VERSION 5.8 ;
BUSBITCHARS "[]" ;
DIVIDERCHAR "/" ;
UNITS
    DATABASE MICRONS 1000 ;
END UNITS

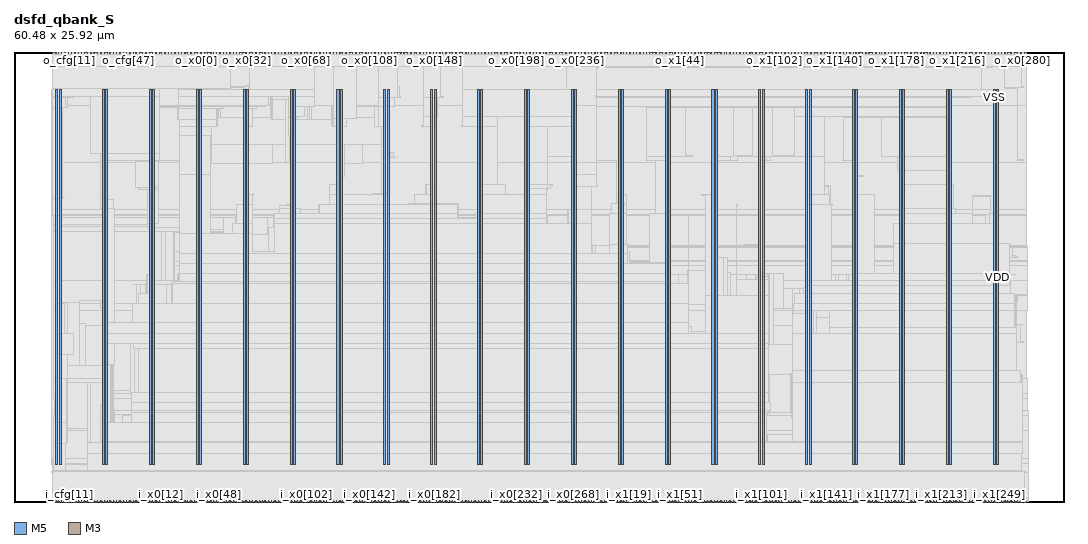
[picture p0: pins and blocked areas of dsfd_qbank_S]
MACRO dsfd_qbank_S
  FOREIGN dsfd_qbank_S 0 0 ;
  CLASS BLOCK ;
  SIZE 60.48 BY 25.92 ;
  PIN ck[0]
    DIRECTION INPUT ;
    USE SIGNAL ;
    PORT
      LAYER M5 ;
        RECT  30.24 0 30.264 0.084 ;
    END
  END ck[0]
  PIN i_cfg[0]
    DIRECTION INPUT ;
    USE SIGNAL ;
    PORT
      LAYER M5 ;
        RECT  2.208 0 2.232 0.084 ;
    END
  END i_cfg[0]
  PIN i_cfg[10]
    DIRECTION INPUT ;
    USE SIGNAL ;
    PORT
      LAYER M5 ;
        RECT  3.12 0 3.144 0.084 ;
    END
  END i_cfg[10]
  PIN i_cfg[11]
    DIRECTION INPUT ;
    USE SIGNAL ;
    PORT
      LAYER M3 ;
        RECT  3.204 0 3.222 0.038 ;
    END
  END i_cfg[11]
  PIN i_cfg[12]
    DIRECTION INPUT ;
    USE SIGNAL ;
    PORT
      LAYER M5 ;
        RECT  3.312 0 3.336 0.084 ;
    END
  END i_cfg[12]
  PIN i_cfg[13]
    DIRECTION INPUT ;
    USE SIGNAL ;
    PORT
      LAYER M3 ;
        RECT  3.42 0 3.438 0.038 ;
    END
  END i_cfg[13]
  PIN i_cfg[14]
    DIRECTION INPUT ;
    USE SIGNAL ;
    PORT
      LAYER M5 ;
        RECT  3.504 0 3.528 0.084 ;
    END
  END i_cfg[14]
  PIN i_cfg[15]
    DIRECTION INPUT ;
    USE SIGNAL ;
    PORT
      LAYER M3 ;
        RECT  3.6 0 3.618 0.038 ;
    END
  END i_cfg[15]
  PIN i_cfg[16]
    DIRECTION INPUT ;
    USE SIGNAL ;
    PORT
      LAYER M5 ;
        RECT  3.696 0 3.72 0.084 ;
    END
  END i_cfg[16]
  PIN i_cfg[17]
    DIRECTION INPUT ;
    USE SIGNAL ;
    PORT
      LAYER M3 ;
        RECT  3.78 0 3.798 0.038 ;
    END
  END i_cfg[17]
  PIN i_cfg[18]
    DIRECTION INPUT ;
    USE SIGNAL ;
    PORT
      LAYER M5 ;
        RECT  3.888 0 3.912 0.084 ;
    END
  END i_cfg[18]
  PIN i_cfg[19]
    DIRECTION INPUT ;
    USE SIGNAL ;
    PORT
      LAYER M3 ;
        RECT  3.996 0 4.014 0.038 ;
    END
  END i_cfg[19]
  PIN i_cfg[1]
    DIRECTION INPUT ;
    USE SIGNAL ;
    PORT
      LAYER M3 ;
        RECT  2.304 0 2.322 0.038 ;
    END
  END i_cfg[1]
  PIN i_cfg[20]
    DIRECTION INPUT ;
    USE SIGNAL ;
    PORT
      LAYER M5 ;
        RECT  4.032 0 4.056 0.084 ;
    END
  END i_cfg[20]
  PIN i_cfg[21]
    DIRECTION INPUT ;
    USE SIGNAL ;
    PORT
      LAYER M3 ;
        RECT  4.14 0 4.158 0.038 ;
    END
  END i_cfg[21]
  PIN i_cfg[22]
    DIRECTION INPUT ;
    USE SIGNAL ;
    PORT
      LAYER M5 ;
        RECT  4.224 0 4.248 0.084 ;
    END
  END i_cfg[22]
  PIN i_cfg[23]
    DIRECTION INPUT ;
    USE SIGNAL ;
    PORT
      LAYER M3 ;
        RECT  4.32 0 4.338 0.038 ;
    END
  END i_cfg[23]
  PIN i_cfg[24]
    DIRECTION INPUT ;
    USE SIGNAL ;
    PORT
      LAYER M5 ;
        RECT  4.416 0 4.44 0.084 ;
    END
  END i_cfg[24]
  PIN i_cfg[25]
    DIRECTION INPUT ;
    USE SIGNAL ;
    PORT
      LAYER M3 ;
        RECT  4.5 0 4.518 0.038 ;
    END
  END i_cfg[25]
  PIN i_cfg[26]
    DIRECTION INPUT ;
    USE SIGNAL ;
    PORT
      LAYER M5 ;
        RECT  4.608 0 4.632 0.084 ;
    END
  END i_cfg[26]
  PIN i_cfg[27]
    DIRECTION INPUT ;
    USE SIGNAL ;
    PORT
      LAYER M3 ;
        RECT  4.716 0 4.734 0.038 ;
    END
  END i_cfg[27]
  PIN i_cfg[28]
    DIRECTION INPUT ;
    USE SIGNAL ;
    PORT
      LAYER M5 ;
        RECT  4.8 0 4.824 0.084 ;
    END
  END i_cfg[28]
  PIN i_cfg[29]
    DIRECTION INPUT ;
    USE SIGNAL ;
    PORT
      LAYER M3 ;
        RECT  4.896 0 4.914 0.038 ;
    END
  END i_cfg[29]
  PIN i_cfg[2]
    DIRECTION INPUT ;
    USE SIGNAL ;
    PORT
      LAYER M5 ;
        RECT  2.4 0 2.424 0.084 ;
    END
  END i_cfg[2]
  PIN i_cfg[30]
    DIRECTION INPUT ;
    USE SIGNAL ;
    PORT
      LAYER M5 ;
        RECT  4.992 0 5.016 0.084 ;
    END
  END i_cfg[30]
  PIN i_cfg[31]
    DIRECTION INPUT ;
    USE SIGNAL ;
    PORT
      LAYER M3 ;
        RECT  5.076 0 5.094 0.038 ;
    END
  END i_cfg[31]
  PIN i_cfg[32]
    DIRECTION INPUT ;
    USE SIGNAL ;
    PORT
      LAYER M5 ;
        RECT  5.184 0 5.208 0.084 ;
    END
  END i_cfg[32]
  PIN i_cfg[33]
    DIRECTION INPUT ;
    USE SIGNAL ;
    PORT
      LAYER M3 ;
        RECT  5.292 0 5.31 0.038 ;
    END
  END i_cfg[33]
  PIN i_cfg[34]
    DIRECTION INPUT ;
    USE SIGNAL ;
    PORT
      LAYER M5 ;
        RECT  5.376 0 5.4 0.084 ;
    END
  END i_cfg[34]
  PIN i_cfg[35]
    DIRECTION INPUT ;
    USE SIGNAL ;
    PORT
      LAYER M3 ;
        RECT  5.472 0 5.49 0.038 ;
    END
  END i_cfg[35]
  PIN i_cfg[36]
    DIRECTION INPUT ;
    USE SIGNAL ;
    PORT
      LAYER M5 ;
        RECT  5.52 0 5.544 0.084 ;
    END
  END i_cfg[36]
  PIN i_cfg[37]
    DIRECTION INPUT ;
    USE SIGNAL ;
    PORT
      LAYER M3 ;
        RECT  5.616 0 5.634 0.038 ;
    END
  END i_cfg[37]
  PIN i_cfg[38]
    DIRECTION INPUT ;
    USE SIGNAL ;
    PORT
      LAYER M5 ;
        RECT  5.712 0 5.736 0.084 ;
    END
  END i_cfg[38]
  PIN i_cfg[39]
    DIRECTION INPUT ;
    USE SIGNAL ;
    PORT
      LAYER M3 ;
        RECT  5.796 0 5.814 0.038 ;
    END
  END i_cfg[39]
  PIN i_cfg[3]
    DIRECTION INPUT ;
    USE SIGNAL ;
    PORT
      LAYER M3 ;
        RECT  2.484 0 2.502 0.038 ;
    END
  END i_cfg[3]
  PIN i_cfg[40]
    DIRECTION INPUT ;
    USE SIGNAL ;
    PORT
      LAYER M5 ;
        RECT  5.904 0 5.928 0.084 ;
    END
  END i_cfg[40]
  PIN i_cfg[41]
    DIRECTION INPUT ;
    USE SIGNAL ;
    PORT
      LAYER M3 ;
        RECT  6.012 0 6.03 0.038 ;
    END
  END i_cfg[41]
  PIN i_cfg[42]
    DIRECTION INPUT ;
    USE SIGNAL ;
    PORT
      LAYER M5 ;
        RECT  6.096 0 6.12 0.084 ;
    END
  END i_cfg[42]
  PIN i_cfg[43]
    DIRECTION INPUT ;
    USE SIGNAL ;
    PORT
      LAYER M3 ;
        RECT  6.192 0 6.21 0.038 ;
    END
  END i_cfg[43]
  PIN i_cfg[44]
    DIRECTION INPUT ;
    USE SIGNAL ;
    PORT
      LAYER M5 ;
        RECT  6.288 0 6.312 0.084 ;
    END
  END i_cfg[44]
  PIN i_cfg[45]
    DIRECTION INPUT ;
    USE SIGNAL ;
    PORT
      LAYER M3 ;
        RECT  6.372 0 6.39 0.038 ;
    END
  END i_cfg[45]
  PIN i_cfg[46]
    DIRECTION INPUT ;
    USE SIGNAL ;
    PORT
      LAYER M5 ;
        RECT  6.48 0 6.504 0.084 ;
    END
  END i_cfg[46]
  PIN i_cfg[47]
    DIRECTION INPUT ;
    USE SIGNAL ;
    PORT
      LAYER M3 ;
        RECT  6.588 0 6.606 0.038 ;
    END
  END i_cfg[47]
  PIN i_cfg[48]
    DIRECTION INPUT ;
    USE SIGNAL ;
    PORT
      LAYER M5 ;
        RECT  6.672 0 6.696 0.084 ;
    END
  END i_cfg[48]
  PIN i_cfg[49]
    DIRECTION INPUT ;
    USE SIGNAL ;
    PORT
      LAYER M3 ;
        RECT  6.768 0 6.786 0.038 ;
    END
  END i_cfg[49]
  PIN i_cfg[4]
    DIRECTION INPUT ;
    USE SIGNAL ;
    PORT
      LAYER M5 ;
        RECT  2.544 0 2.568 0.084 ;
    END
  END i_cfg[4]
  PIN i_cfg[50]
    DIRECTION INPUT ;
    USE SIGNAL ;
    PORT
      LAYER M5 ;
        RECT  6.864 0 6.888 0.084 ;
    END
  END i_cfg[50]
  PIN i_cfg[51]
    DIRECTION INPUT ;
    USE SIGNAL ;
    PORT
      LAYER M3 ;
        RECT  6.948 0 6.966 0.038 ;
    END
  END i_cfg[51]
  PIN i_cfg[52]
    DIRECTION INPUT ;
    USE SIGNAL ;
    PORT
      LAYER M5 ;
        RECT  7.008 0 7.032 0.084 ;
    END
  END i_cfg[52]
  PIN i_cfg[53]
    DIRECTION INPUT ;
    USE SIGNAL ;
    PORT
      LAYER M3 ;
        RECT  7.092 0 7.11 0.038 ;
    END
  END i_cfg[53]
  PIN i_cfg[5]
    DIRECTION INPUT ;
    USE SIGNAL ;
    PORT
      LAYER M3 ;
        RECT  2.628 0 2.646 0.038 ;
    END
  END i_cfg[5]
  PIN i_cfg[6]
    DIRECTION INPUT ;
    USE SIGNAL ;
    PORT
      LAYER M5 ;
        RECT  2.736 0 2.76 0.084 ;
    END
  END i_cfg[6]
  PIN i_cfg[7]
    DIRECTION INPUT ;
    USE SIGNAL ;
    PORT
      LAYER M3 ;
        RECT  2.844 0 2.862 0.038 ;
    END
  END i_cfg[7]
  PIN i_cfg[8]
    DIRECTION INPUT ;
    USE SIGNAL ;
    PORT
      LAYER M5 ;
        RECT  2.928 0 2.952 0.084 ;
    END
  END i_cfg[8]
  PIN i_cfg[9]
    DIRECTION INPUT ;
    USE SIGNAL ;
    PORT
      LAYER M3 ;
        RECT  3.024 0 3.042 0.038 ;
    END
  END i_cfg[9]
  PIN i_go[0]
    DIRECTION INPUT ;
    USE SIGNAL ;
    PORT
      LAYER M5 ;
        RECT  7.2 0 7.224 0.084 ;
    END
  END i_go[0]
  PIN i_x0[0]
    DIRECTION INPUT ;
    USE SIGNAL ;
    PORT
      LAYER M3 ;
        RECT  7.308 0 7.326 0.038 ;
    END
  END i_x0[0]
  PIN i_x0[100]
    DIRECTION INPUT ;
    USE SIGNAL ;
    PORT
      LAYER M3 ;
        RECT  16.596 0 16.614 0.038 ;
    END
  END i_x0[100]
  PIN i_x0[101]
    DIRECTION INPUT ;
    USE SIGNAL ;
    PORT
      LAYER M5 ;
        RECT  16.704 0 16.728 0.084 ;
    END
  END i_x0[101]
  PIN i_x0[102]
    DIRECTION INPUT ;
    USE SIGNAL ;
    PORT
      LAYER M3 ;
        RECT  16.812 0 16.83 0.038 ;
    END
  END i_x0[102]
  PIN i_x0[103]
    DIRECTION INPUT ;
    USE SIGNAL ;
    PORT
      LAYER M5 ;
        RECT  16.896 0 16.92 0.084 ;
    END
  END i_x0[103]
  PIN i_x0[104]
    DIRECTION INPUT ;
    USE SIGNAL ;
    PORT
      LAYER M3 ;
        RECT  16.992 0 17.01 0.038 ;
    END
  END i_x0[104]
  PIN i_x0[105]
    DIRECTION INPUT ;
    USE SIGNAL ;
    PORT
      LAYER M5 ;
        RECT  17.088 0 17.112 0.084 ;
    END
  END i_x0[105]
  PIN i_x0[106]
    DIRECTION INPUT ;
    USE SIGNAL ;
    PORT
      LAYER M3 ;
        RECT  17.172 0 17.19 0.038 ;
    END
  END i_x0[106]
  PIN i_x0[107]
    DIRECTION INPUT ;
    USE SIGNAL ;
    PORT
      LAYER M5 ;
        RECT  17.28 0 17.304 0.084 ;
    END
  END i_x0[107]
  PIN i_x0[108]
    DIRECTION INPUT ;
    USE SIGNAL ;
    PORT
      LAYER M3 ;
        RECT  17.316 0 17.334 0.038 ;
    END
  END i_x0[108]
  PIN i_x0[109]
    DIRECTION INPUT ;
    USE SIGNAL ;
    PORT
      LAYER M5 ;
        RECT  17.424 0 17.448 0.084 ;
    END
  END i_x0[109]
  PIN i_x0[10]
    DIRECTION INPUT ;
    USE SIGNAL ;
    PORT
      LAYER M3 ;
        RECT  8.244 0 8.262 0.038 ;
    END
  END i_x0[10]
  PIN i_x0[110]
    DIRECTION INPUT ;
    USE SIGNAL ;
    PORT
      LAYER M3 ;
        RECT  17.532 0 17.55 0.038 ;
    END
  END i_x0[110]
  PIN i_x0[111]
    DIRECTION INPUT ;
    USE SIGNAL ;
    PORT
      LAYER M5 ;
        RECT  17.616 0 17.64 0.084 ;
    END
  END i_x0[111]
  PIN i_x0[112]
    DIRECTION INPUT ;
    USE SIGNAL ;
    PORT
      LAYER M3 ;
        RECT  17.712 0 17.73 0.038 ;
    END
  END i_x0[112]
  PIN i_x0[113]
    DIRECTION INPUT ;
    USE SIGNAL ;
    PORT
      LAYER M5 ;
        RECT  17.808 0 17.832 0.084 ;
    END
  END i_x0[113]
  PIN i_x0[114]
    DIRECTION INPUT ;
    USE SIGNAL ;
    PORT
      LAYER M3 ;
        RECT  17.892 0 17.91 0.038 ;
    END
  END i_x0[114]
  PIN i_x0[115]
    DIRECTION INPUT ;
    USE SIGNAL ;
    PORT
      LAYER M5 ;
        RECT  18 0 18.024 0.084 ;
    END
  END i_x0[115]
  PIN i_x0[116]
    DIRECTION INPUT ;
    USE SIGNAL ;
    PORT
      LAYER M3 ;
        RECT  18.108 0 18.126 0.038 ;
    END
  END i_x0[116]
  PIN i_x0[117]
    DIRECTION INPUT ;
    USE SIGNAL ;
    PORT
      LAYER M5 ;
        RECT  18.192 0 18.216 0.084 ;
    END
  END i_x0[117]
  PIN i_x0[118]
    DIRECTION INPUT ;
    USE SIGNAL ;
    PORT
      LAYER M3 ;
        RECT  18.288 0 18.306 0.038 ;
    END
  END i_x0[118]
  PIN i_x0[119]
    DIRECTION INPUT ;
    USE SIGNAL ;
    PORT
      LAYER M5 ;
        RECT  18.384 0 18.408 0.084 ;
    END
  END i_x0[119]
  PIN i_x0[11]
    DIRECTION INPUT ;
    USE SIGNAL ;
    PORT
      LAYER M5 ;
        RECT  8.352 0 8.376 0.084 ;
    END
  END i_x0[11]
  PIN i_x0[120]
    DIRECTION INPUT ;
    USE SIGNAL ;
    PORT
      LAYER M3 ;
        RECT  18.468 0 18.486 0.038 ;
    END
  END i_x0[120]
  PIN i_x0[121]
    DIRECTION INPUT ;
    USE SIGNAL ;
    PORT
      LAYER M5 ;
        RECT  18.576 0 18.6 0.084 ;
    END
  END i_x0[121]
  PIN i_x0[122]
    DIRECTION INPUT ;
    USE SIGNAL ;
    PORT
      LAYER M3 ;
        RECT  18.684 0 18.702 0.038 ;
    END
  END i_x0[122]
  PIN i_x0[123]
    DIRECTION INPUT ;
    USE SIGNAL ;
    PORT
      LAYER M5 ;
        RECT  18.768 0 18.792 0.084 ;
    END
  END i_x0[123]
  PIN i_x0[124]
    DIRECTION INPUT ;
    USE SIGNAL ;
    PORT
      LAYER M3 ;
        RECT  18.828 0 18.846 0.038 ;
    END
  END i_x0[124]
  PIN i_x0[125]
    DIRECTION INPUT ;
    USE SIGNAL ;
    PORT
      LAYER M5 ;
        RECT  18.912 0 18.936 0.084 ;
    END
  END i_x0[125]
  PIN i_x0[126]
    DIRECTION INPUT ;
    USE SIGNAL ;
    PORT
      LAYER M3 ;
        RECT  19.008 0 19.026 0.038 ;
    END
  END i_x0[126]
  PIN i_x0[127]
    DIRECTION INPUT ;
    USE SIGNAL ;
    PORT
      LAYER M5 ;
        RECT  19.104 0 19.128 0.084 ;
    END
  END i_x0[127]
  PIN i_x0[128]
    DIRECTION INPUT ;
    USE SIGNAL ;
    PORT
      LAYER M3 ;
        RECT  19.188 0 19.206 0.038 ;
    END
  END i_x0[128]
  PIN i_x0[129]
    DIRECTION INPUT ;
    USE SIGNAL ;
    PORT
      LAYER M5 ;
        RECT  19.296 0 19.32 0.084 ;
    END
  END i_x0[129]
  PIN i_x0[12]
    DIRECTION INPUT ;
    USE SIGNAL ;
    PORT
      LAYER M3 ;
        RECT  8.46 0 8.478 0.038 ;
    END
  END i_x0[12]
  PIN i_x0[130]
    DIRECTION INPUT ;
    USE SIGNAL ;
    PORT
      LAYER M3 ;
        RECT  19.404 0 19.422 0.038 ;
    END
  END i_x0[130]
  PIN i_x0[131]
    DIRECTION INPUT ;
    USE SIGNAL ;
    PORT
      LAYER M5 ;
        RECT  19.488 0 19.512 0.084 ;
    END
  END i_x0[131]
  PIN i_x0[132]
    DIRECTION INPUT ;
    USE SIGNAL ;
    PORT
      LAYER M3 ;
        RECT  19.584 0 19.602 0.038 ;
    END
  END i_x0[132]
  PIN i_x0[133]
    DIRECTION INPUT ;
    USE SIGNAL ;
    PORT
      LAYER M5 ;
        RECT  19.68 0 19.704 0.084 ;
    END
  END i_x0[133]
  PIN i_x0[134]
    DIRECTION INPUT ;
    USE SIGNAL ;
    PORT
      LAYER M3 ;
        RECT  19.764 0 19.782 0.038 ;
    END
  END i_x0[134]
  PIN i_x0[135]
    DIRECTION INPUT ;
    USE SIGNAL ;
    PORT
      LAYER M5 ;
        RECT  19.872 0 19.896 0.084 ;
    END
  END i_x0[135]
  PIN i_x0[136]
    DIRECTION INPUT ;
    USE SIGNAL ;
    PORT
      LAYER M3 ;
        RECT  19.98 0 19.998 0.038 ;
    END
  END i_x0[136]
  PIN i_x0[137]
    DIRECTION INPUT ;
    USE SIGNAL ;
    PORT
      LAYER M5 ;
        RECT  20.064 0 20.088 0.084 ;
    END
  END i_x0[137]
  PIN i_x0[138]
    DIRECTION INPUT ;
    USE SIGNAL ;
    PORT
      LAYER M3 ;
        RECT  20.16 0 20.178 0.038 ;
    END
  END i_x0[138]
  PIN i_x0[139]
    DIRECTION INPUT ;
    USE SIGNAL ;
    PORT
      LAYER M5 ;
        RECT  20.256 0 20.28 0.084 ;
    END
  END i_x0[139]
  PIN i_x0[13]
    DIRECTION INPUT ;
    USE SIGNAL ;
    PORT
      LAYER M5 ;
        RECT  8.496 0 8.52 0.084 ;
    END
  END i_x0[13]
  PIN i_x0[140]
    DIRECTION INPUT ;
    USE SIGNAL ;
    PORT
      LAYER M3 ;
        RECT  20.304 0 20.322 0.038 ;
    END
  END i_x0[140]
  PIN i_x0[141]
    DIRECTION INPUT ;
    USE SIGNAL ;
    PORT
      LAYER M5 ;
        RECT  20.4 0 20.424 0.084 ;
    END
  END i_x0[141]
  PIN i_x0[142]
    DIRECTION INPUT ;
    USE SIGNAL ;
    PORT
      LAYER M3 ;
        RECT  20.484 0 20.502 0.038 ;
    END
  END i_x0[142]
  PIN i_x0[143]
    DIRECTION INPUT ;
    USE SIGNAL ;
    PORT
      LAYER M5 ;
        RECT  20.592 0 20.616 0.084 ;
    END
  END i_x0[143]
  PIN i_x0[144]
    DIRECTION INPUT ;
    USE SIGNAL ;
    PORT
      LAYER M3 ;
        RECT  20.7 0 20.718 0.038 ;
    END
  END i_x0[144]
  PIN i_x0[145]
    DIRECTION INPUT ;
    USE SIGNAL ;
    PORT
      LAYER M5 ;
        RECT  20.784 0 20.808 0.084 ;
    END
  END i_x0[145]
  PIN i_x0[146]
    DIRECTION INPUT ;
    USE SIGNAL ;
    PORT
      LAYER M3 ;
        RECT  20.88 0 20.898 0.038 ;
    END
  END i_x0[146]
  PIN i_x0[147]
    DIRECTION INPUT ;
    USE SIGNAL ;
    PORT
      LAYER M5 ;
        RECT  20.976 0 21 0.084 ;
    END
  END i_x0[147]
  PIN i_x0[148]
    DIRECTION INPUT ;
    USE SIGNAL ;
    PORT
      LAYER M3 ;
        RECT  21.06 0 21.078 0.038 ;
    END
  END i_x0[148]
  PIN i_x0[149]
    DIRECTION INPUT ;
    USE SIGNAL ;
    PORT
      LAYER M5 ;
        RECT  21.168 0 21.192 0.084 ;
    END
  END i_x0[149]
  PIN i_x0[14]
    DIRECTION INPUT ;
    USE SIGNAL ;
    PORT
      LAYER M3 ;
        RECT  8.604 0 8.622 0.038 ;
    END
  END i_x0[14]
  PIN i_x0[150]
    DIRECTION INPUT ;
    USE SIGNAL ;
    PORT
      LAYER M3 ;
        RECT  21.276 0 21.294 0.038 ;
    END
  END i_x0[150]
  PIN i_x0[151]
    DIRECTION INPUT ;
    USE SIGNAL ;
    PORT
      LAYER M5 ;
        RECT  21.36 0 21.384 0.084 ;
    END
  END i_x0[151]
  PIN i_x0[152]
    DIRECTION INPUT ;
    USE SIGNAL ;
    PORT
      LAYER M3 ;
        RECT  21.456 0 21.474 0.038 ;
    END
  END i_x0[152]
  PIN i_x0[153]
    DIRECTION INPUT ;
    USE SIGNAL ;
    PORT
      LAYER M5 ;
        RECT  21.552 0 21.576 0.084 ;
    END
  END i_x0[153]
  PIN i_x0[154]
    DIRECTION INPUT ;
    USE SIGNAL ;
    PORT
      LAYER M3 ;
        RECT  21.636 0 21.654 0.038 ;
    END
  END i_x0[154]
  PIN i_x0[155]
    DIRECTION INPUT ;
    USE SIGNAL ;
    PORT
      LAYER M5 ;
        RECT  21.744 0 21.768 0.084 ;
    END
  END i_x0[155]
  PIN i_x0[156]
    DIRECTION INPUT ;
    USE SIGNAL ;
    PORT
      LAYER M3 ;
        RECT  21.78 0 21.798 0.038 ;
    END
  END i_x0[156]
  PIN i_x0[157]
    DIRECTION INPUT ;
    USE SIGNAL ;
    PORT
      LAYER M5 ;
        RECT  21.888 0 21.912 0.084 ;
    END
  END i_x0[157]
  PIN i_x0[158]
    DIRECTION INPUT ;
    USE SIGNAL ;
    PORT
      LAYER M3 ;
        RECT  21.996 0 22.014 0.038 ;
    END
  END i_x0[158]
  PIN i_x0[159]
    DIRECTION INPUT ;
    USE SIGNAL ;
    PORT
      LAYER M5 ;
        RECT  22.08 0 22.104 0.084 ;
    END
  END i_x0[159]
  PIN i_x0[15]
    DIRECTION INPUT ;
    USE SIGNAL ;
    PORT
      LAYER M5 ;
        RECT  8.688 0 8.712 0.084 ;
    END
  END i_x0[15]
  PIN i_x0[160]
    DIRECTION INPUT ;
    USE SIGNAL ;
    PORT
      LAYER M3 ;
        RECT  22.176 0 22.194 0.038 ;
    END
  END i_x0[160]
  PIN i_x0[161]
    DIRECTION INPUT ;
    USE SIGNAL ;
    PORT
      LAYER M5 ;
        RECT  22.272 0 22.296 0.084 ;
    END
  END i_x0[161]
  PIN i_x0[162]
    DIRECTION INPUT ;
    USE SIGNAL ;
    PORT
      LAYER M3 ;
        RECT  22.356 0 22.374 0.038 ;
    END
  END i_x0[162]
  PIN i_x0[163]
    DIRECTION INPUT ;
    USE SIGNAL ;
    PORT
      LAYER M5 ;
        RECT  22.464 0 22.488 0.084 ;
    END
  END i_x0[163]
  PIN i_x0[164]
    DIRECTION INPUT ;
    USE SIGNAL ;
    PORT
      LAYER M3 ;
        RECT  22.572 0 22.59 0.038 ;
    END
  END i_x0[164]
  PIN i_x0[165]
    DIRECTION INPUT ;
    USE SIGNAL ;
    PORT
      LAYER M5 ;
        RECT  22.656 0 22.68 0.084 ;
    END
  END i_x0[165]
  PIN i_x0[166]
    DIRECTION INPUT ;
    USE SIGNAL ;
    PORT
      LAYER M3 ;
        RECT  22.752 0 22.77 0.038 ;
    END
  END i_x0[166]
  PIN i_x0[167]
    DIRECTION INPUT ;
    USE SIGNAL ;
    PORT
      LAYER M5 ;
        RECT  22.848 0 22.872 0.084 ;
    END
  END i_x0[167]
  PIN i_x0[168]
    DIRECTION INPUT ;
    USE SIGNAL ;
    PORT
      LAYER M3 ;
        RECT  22.932 0 22.95 0.038 ;
    END
  END i_x0[168]
  PIN i_x0[169]
    DIRECTION INPUT ;
    USE SIGNAL ;
    PORT
      LAYER M5 ;
        RECT  23.04 0 23.064 0.084 ;
    END
  END i_x0[169]
  PIN i_x0[16]
    DIRECTION INPUT ;
    USE SIGNAL ;
    PORT
      LAYER M3 ;
        RECT  8.784 0 8.802 0.038 ;
    END
  END i_x0[16]
  PIN i_x0[170]
    DIRECTION INPUT ;
    USE SIGNAL ;
    PORT
      LAYER M3 ;
        RECT  23.148 0 23.166 0.038 ;
    END
  END i_x0[170]
  PIN i_x0[171]
    DIRECTION INPUT ;
    USE SIGNAL ;
    PORT
      LAYER M5 ;
        RECT  23.184 0 23.208 0.084 ;
    END
  END i_x0[171]
  PIN i_x0[172]
    DIRECTION INPUT ;
    USE SIGNAL ;
    PORT
      LAYER M3 ;
        RECT  23.292 0 23.31 0.038 ;
    END
  END i_x0[172]
  PIN i_x0[173]
    DIRECTION INPUT ;
    USE SIGNAL ;
    PORT
      LAYER M5 ;
        RECT  23.376 0 23.4 0.084 ;
    END
  END i_x0[173]
  PIN i_x0[174]
    DIRECTION INPUT ;
    USE SIGNAL ;
    PORT
      LAYER M3 ;
        RECT  23.472 0 23.49 0.038 ;
    END
  END i_x0[174]
  PIN i_x0[175]
    DIRECTION INPUT ;
    USE SIGNAL ;
    PORT
      LAYER M5 ;
        RECT  23.568 0 23.592 0.084 ;
    END
  END i_x0[175]
  PIN i_x0[176]
    DIRECTION INPUT ;
    USE SIGNAL ;
    PORT
      LAYER M3 ;
        RECT  23.652 0 23.67 0.038 ;
    END
  END i_x0[176]
  PIN i_x0[177]
    DIRECTION INPUT ;
    USE SIGNAL ;
    PORT
      LAYER M5 ;
        RECT  23.76 0 23.784 0.084 ;
    END
  END i_x0[177]
  PIN i_x0[178]
    DIRECTION INPUT ;
    USE SIGNAL ;
    PORT
      LAYER M3 ;
        RECT  23.868 0 23.886 0.038 ;
    END
  END i_x0[178]
  PIN i_x0[179]
    DIRECTION INPUT ;
    USE SIGNAL ;
    PORT
      LAYER M5 ;
        RECT  23.952 0 23.976 0.084 ;
    END
  END i_x0[179]
  PIN i_x0[17]
    DIRECTION INPUT ;
    USE SIGNAL ;
    PORT
      LAYER M5 ;
        RECT  8.88 0 8.904 0.084 ;
    END
  END i_x0[17]
  PIN i_x0[180]
    DIRECTION INPUT ;
    USE SIGNAL ;
    PORT
      LAYER M3 ;
        RECT  24.048 0 24.066 0.038 ;
    END
  END i_x0[180]
  PIN i_x0[181]
    DIRECTION INPUT ;
    USE SIGNAL ;
    PORT
      LAYER M5 ;
        RECT  24.144 0 24.168 0.084 ;
    END
  END i_x0[181]
  PIN i_x0[182]
    DIRECTION INPUT ;
    USE SIGNAL ;
    PORT
      LAYER M3 ;
        RECT  24.228 0 24.246 0.038 ;
    END
  END i_x0[182]
  PIN i_x0[183]
    DIRECTION INPUT ;
    USE SIGNAL ;
    PORT
      LAYER M5 ;
        RECT  24.336 0 24.36 0.084 ;
    END
  END i_x0[183]
  PIN i_x0[184]
    DIRECTION INPUT ;
    USE SIGNAL ;
    PORT
      LAYER M3 ;
        RECT  24.444 0 24.462 0.038 ;
    END
  END i_x0[184]
  PIN i_x0[185]
    DIRECTION INPUT ;
    USE SIGNAL ;
    PORT
      LAYER M5 ;
        RECT  24.528 0 24.552 0.084 ;
    END
  END i_x0[185]
  PIN i_x0[186]
    DIRECTION INPUT ;
    USE SIGNAL ;
    PORT
      LAYER M3 ;
        RECT  24.624 0 24.642 0.038 ;
    END
  END i_x0[186]
  PIN i_x0[187]
    DIRECTION INPUT ;
    USE SIGNAL ;
    PORT
      LAYER M5 ;
        RECT  24.672 0 24.696 0.084 ;
    END
  END i_x0[187]
  PIN i_x0[188]
    DIRECTION INPUT ;
    USE SIGNAL ;
    PORT
      LAYER M3 ;
        RECT  24.768 0 24.786 0.038 ;
    END
  END i_x0[188]
  PIN i_x0[189]
    DIRECTION INPUT ;
    USE SIGNAL ;
    PORT
      LAYER M5 ;
        RECT  24.864 0 24.888 0.084 ;
    END
  END i_x0[189]
  PIN i_x0[18]
    DIRECTION INPUT ;
    USE SIGNAL ;
    PORT
      LAYER M3 ;
        RECT  8.964 0 8.982 0.038 ;
    END
  END i_x0[18]
  PIN i_x0[190]
    DIRECTION INPUT ;
    USE SIGNAL ;
    PORT
      LAYER M3 ;
        RECT  24.948 0 24.966 0.038 ;
    END
  END i_x0[190]
  PIN i_x0[191]
    DIRECTION INPUT ;
    USE SIGNAL ;
    PORT
      LAYER M5 ;
        RECT  25.056 0 25.08 0.084 ;
    END
  END i_x0[191]
  PIN i_x0[192]
    DIRECTION INPUT ;
    USE SIGNAL ;
    PORT
      LAYER M3 ;
        RECT  25.164 0 25.182 0.038 ;
    END
  END i_x0[192]
  PIN i_x0[193]
    DIRECTION INPUT ;
    USE SIGNAL ;
    PORT
      LAYER M5 ;
        RECT  25.248 0 25.272 0.084 ;
    END
  END i_x0[193]
  PIN i_x0[194]
    DIRECTION INPUT ;
    USE SIGNAL ;
    PORT
      LAYER M3 ;
        RECT  25.344 0 25.362 0.038 ;
    END
  END i_x0[194]
  PIN i_x0[195]
    DIRECTION INPUT ;
    USE SIGNAL ;
    PORT
      LAYER M5 ;
        RECT  25.44 0 25.464 0.084 ;
    END
  END i_x0[195]
  PIN i_x0[196]
    DIRECTION INPUT ;
    USE SIGNAL ;
    PORT
      LAYER M3 ;
        RECT  25.524 0 25.542 0.038 ;
    END
  END i_x0[196]
  PIN i_x0[197]
    DIRECTION INPUT ;
    USE SIGNAL ;
    PORT
      LAYER M5 ;
        RECT  25.632 0 25.656 0.084 ;
    END
  END i_x0[197]
  PIN i_x0[198]
    DIRECTION INPUT ;
    USE SIGNAL ;
    PORT
      LAYER M3 ;
        RECT  25.74 0 25.758 0.038 ;
    END
  END i_x0[198]
  PIN i_x0[199]
    DIRECTION INPUT ;
    USE SIGNAL ;
    PORT
      LAYER M5 ;
        RECT  25.824 0 25.848 0.084 ;
    END
  END i_x0[199]
  PIN i_x0[19]
    DIRECTION INPUT ;
    USE SIGNAL ;
    PORT
      LAYER M5 ;
        RECT  9.072 0 9.096 0.084 ;
    END
  END i_x0[19]
  PIN i_x0[1]
    DIRECTION INPUT ;
    USE SIGNAL ;
    PORT
      LAYER M5 ;
        RECT  7.392 0 7.416 0.084 ;
    END
  END i_x0[1]
  PIN i_x0[200]
    DIRECTION INPUT ;
    USE SIGNAL ;
    PORT
      LAYER M3 ;
        RECT  25.92 0 25.938 0.038 ;
    END
  END i_x0[200]
  PIN i_x0[201]
    DIRECTION INPUT ;
    USE SIGNAL ;
    PORT
      LAYER M5 ;
        RECT  26.016 0 26.04 0.084 ;
    END
  END i_x0[201]
  PIN i_x0[202]
    DIRECTION INPUT ;
    USE SIGNAL ;
    PORT
      LAYER M3 ;
        RECT  26.1 0 26.118 0.038 ;
    END
  END i_x0[202]
  PIN i_x0[203]
    DIRECTION INPUT ;
    USE SIGNAL ;
    PORT
      LAYER M5 ;
        RECT  26.16 0 26.184 0.084 ;
    END
  END i_x0[203]
  PIN i_x0[204]
    DIRECTION INPUT ;
    USE SIGNAL ;
    PORT
      LAYER M3 ;
        RECT  26.244 0 26.262 0.038 ;
    END
  END i_x0[204]
  PIN i_x0[205]
    DIRECTION INPUT ;
    USE SIGNAL ;
    PORT
      LAYER M5 ;
        RECT  26.352 0 26.376 0.084 ;
    END
  END i_x0[205]
  PIN i_x0[206]
    DIRECTION INPUT ;
    USE SIGNAL ;
    PORT
      LAYER M3 ;
        RECT  26.46 0 26.478 0.038 ;
    END
  END i_x0[206]
  PIN i_x0[207]
    DIRECTION INPUT ;
    USE SIGNAL ;
    PORT
      LAYER M5 ;
        RECT  26.544 0 26.568 0.084 ;
    END
  END i_x0[207]
  PIN i_x0[208]
    DIRECTION INPUT ;
    USE SIGNAL ;
    PORT
      LAYER M3 ;
        RECT  26.64 0 26.658 0.038 ;
    END
  END i_x0[208]
  PIN i_x0[209]
    DIRECTION INPUT ;
    USE SIGNAL ;
    PORT
      LAYER M5 ;
        RECT  26.736 0 26.76 0.084 ;
    END
  END i_x0[209]
  PIN i_x0[20]
    DIRECTION INPUT ;
    USE SIGNAL ;
    PORT
      LAYER M3 ;
        RECT  9.18 0 9.198 0.038 ;
    END
  END i_x0[20]
  PIN i_x0[210]
    DIRECTION INPUT ;
    USE SIGNAL ;
    PORT
      LAYER M3 ;
        RECT  26.82 0 26.838 0.038 ;
    END
  END i_x0[210]
  PIN i_x0[211]
    DIRECTION INPUT ;
    USE SIGNAL ;
    PORT
      LAYER M5 ;
        RECT  26.928 0 26.952 0.084 ;
    END
  END i_x0[211]
  PIN i_x0[212]
    DIRECTION INPUT ;
    USE SIGNAL ;
    PORT
      LAYER M3 ;
        RECT  27.036 0 27.054 0.038 ;
    END
  END i_x0[212]
  PIN i_x0[213]
    DIRECTION INPUT ;
    USE SIGNAL ;
    PORT
      LAYER M5 ;
        RECT  27.12 0 27.144 0.084 ;
    END
  END i_x0[213]
  PIN i_x0[214]
    DIRECTION INPUT ;
    USE SIGNAL ;
    PORT
      LAYER M3 ;
        RECT  27.216 0 27.234 0.038 ;
    END
  END i_x0[214]
  PIN i_x0[215]
    DIRECTION INPUT ;
    USE SIGNAL ;
    PORT
      LAYER M5 ;
        RECT  27.312 0 27.336 0.084 ;
    END
  END i_x0[215]
  PIN i_x0[216]
    DIRECTION INPUT ;
    USE SIGNAL ;
    PORT
      LAYER M3 ;
        RECT  27.396 0 27.414 0.038 ;
    END
  END i_x0[216]
  PIN i_x0[217]
    DIRECTION INPUT ;
    USE SIGNAL ;
    PORT
      LAYER M5 ;
        RECT  27.504 0 27.528 0.084 ;
    END
  END i_x0[217]
  PIN i_x0[218]
    DIRECTION INPUT ;
    USE SIGNAL ;
    PORT
      LAYER M3 ;
        RECT  27.612 0 27.63 0.038 ;
    END
  END i_x0[218]
  PIN i_x0[219]
    DIRECTION INPUT ;
    USE SIGNAL ;
    PORT
      LAYER M5 ;
        RECT  27.648 0 27.672 0.084 ;
    END
  END i_x0[219]
  PIN i_x0[21]
    DIRECTION INPUT ;
    USE SIGNAL ;
    PORT
      LAYER M5 ;
        RECT  9.264 0 9.288 0.084 ;
    END
  END i_x0[21]
  PIN i_x0[220]
    DIRECTION INPUT ;
    USE SIGNAL ;
    PORT
      LAYER M3 ;
        RECT  27.756 0 27.774 0.038 ;
    END
  END i_x0[220]
  PIN i_x0[221]
    DIRECTION INPUT ;
    USE SIGNAL ;
    PORT
      LAYER M5 ;
        RECT  27.84 0 27.864 0.084 ;
    END
  END i_x0[221]
  PIN i_x0[222]
    DIRECTION INPUT ;
    USE SIGNAL ;
    PORT
      LAYER M3 ;
        RECT  27.936 0 27.954 0.038 ;
    END
  END i_x0[222]
  PIN i_x0[223]
    DIRECTION INPUT ;
    USE SIGNAL ;
    PORT
      LAYER M5 ;
        RECT  28.032 0 28.056 0.084 ;
    END
  END i_x0[223]
  PIN i_x0[224]
    DIRECTION INPUT ;
    USE SIGNAL ;
    PORT
      LAYER M3 ;
        RECT  28.116 0 28.134 0.038 ;
    END
  END i_x0[224]
  PIN i_x0[225]
    DIRECTION INPUT ;
    USE SIGNAL ;
    PORT
      LAYER M5 ;
        RECT  28.224 0 28.248 0.084 ;
    END
  END i_x0[225]
  PIN i_x0[226]
    DIRECTION INPUT ;
    USE SIGNAL ;
    PORT
      LAYER M3 ;
        RECT  28.332 0 28.35 0.038 ;
    END
  END i_x0[226]
  PIN i_x0[227]
    DIRECTION INPUT ;
    USE SIGNAL ;
    PORT
      LAYER M5 ;
        RECT  28.416 0 28.44 0.084 ;
    END
  END i_x0[227]
  PIN i_x0[228]
    DIRECTION INPUT ;
    USE SIGNAL ;
    PORT
      LAYER M3 ;
        RECT  28.512 0 28.53 0.038 ;
    END
  END i_x0[228]
  PIN i_x0[229]
    DIRECTION INPUT ;
    USE SIGNAL ;
    PORT
      LAYER M5 ;
        RECT  28.608 0 28.632 0.084 ;
    END
  END i_x0[229]
  PIN i_x0[22]
    DIRECTION INPUT ;
    USE SIGNAL ;
    PORT
      LAYER M3 ;
        RECT  9.36 0 9.378 0.038 ;
    END
  END i_x0[22]
  PIN i_x0[230]
    DIRECTION INPUT ;
    USE SIGNAL ;
    PORT
      LAYER M3 ;
        RECT  28.692 0 28.71 0.038 ;
    END
  END i_x0[230]
  PIN i_x0[231]
    DIRECTION INPUT ;
    USE SIGNAL ;
    PORT
      LAYER M5 ;
        RECT  28.8 0 28.824 0.084 ;
    END
  END i_x0[231]
  PIN i_x0[232]
    DIRECTION INPUT ;
    USE SIGNAL ;
    PORT
      LAYER M3 ;
        RECT  28.908 0 28.926 0.038 ;
    END
  END i_x0[232]
  PIN i_x0[233]
    DIRECTION INPUT ;
    USE SIGNAL ;
    PORT
      LAYER M5 ;
        RECT  28.992 0 29.016 0.084 ;
    END
  END i_x0[233]
  PIN i_x0[234]
    DIRECTION INPUT ;
    USE SIGNAL ;
    PORT
      LAYER M3 ;
        RECT  29.088 0 29.106 0.038 ;
    END
  END i_x0[234]
  PIN i_x0[235]
    DIRECTION INPUT ;
    USE SIGNAL ;
    PORT
      LAYER M5 ;
        RECT  29.136 0 29.16 0.084 ;
    END
  END i_x0[235]
  PIN i_x0[236]
    DIRECTION INPUT ;
    USE SIGNAL ;
    PORT
      LAYER M3 ;
        RECT  29.232 0 29.25 0.038 ;
    END
  END i_x0[236]
  PIN i_x0[237]
    DIRECTION INPUT ;
    USE SIGNAL ;
    PORT
      LAYER M5 ;
        RECT  29.328 0 29.352 0.084 ;
    END
  END i_x0[237]
  PIN i_x0[238]
    DIRECTION INPUT ;
    USE SIGNAL ;
    PORT
      LAYER M3 ;
        RECT  29.412 0 29.43 0.038 ;
    END
  END i_x0[238]
  PIN i_x0[239]
    DIRECTION INPUT ;
    USE SIGNAL ;
    PORT
      LAYER M5 ;
        RECT  29.52 0 29.544 0.084 ;
    END
  END i_x0[239]
  PIN i_x0[23]
    DIRECTION INPUT ;
    USE SIGNAL ;
    PORT
      LAYER M5 ;
        RECT  9.456 0 9.48 0.084 ;
    END
  END i_x0[23]
  PIN i_x0[240]
    DIRECTION INPUT ;
    USE SIGNAL ;
    PORT
      LAYER M3 ;
        RECT  29.628 0 29.646 0.038 ;
    END
  END i_x0[240]
  PIN i_x0[241]
    DIRECTION INPUT ;
    USE SIGNAL ;
    PORT
      LAYER M5 ;
        RECT  29.712 0 29.736 0.084 ;
    END
  END i_x0[241]
  PIN i_x0[242]
    DIRECTION INPUT ;
    USE SIGNAL ;
    PORT
      LAYER M3 ;
        RECT  29.808 0 29.826 0.038 ;
    END
  END i_x0[242]
  PIN i_x0[243]
    DIRECTION INPUT ;
    USE SIGNAL ;
    PORT
      LAYER M5 ;
        RECT  29.904 0 29.928 0.084 ;
    END
  END i_x0[243]
  PIN i_x0[244]
    DIRECTION INPUT ;
    USE SIGNAL ;
    PORT
      LAYER M3 ;
        RECT  29.988 0 30.006 0.038 ;
    END
  END i_x0[244]
  PIN i_x0[245]
    DIRECTION INPUT ;
    USE SIGNAL ;
    PORT
      LAYER M5 ;
        RECT  30.096 0 30.12 0.084 ;
    END
  END i_x0[245]
  PIN i_x0[246]
    DIRECTION INPUT ;
    USE SIGNAL ;
    PORT
      LAYER M3 ;
        RECT  30.42 0 30.438 0.038 ;
    END
  END i_x0[246]
  PIN i_x0[247]
    DIRECTION INPUT ;
    USE SIGNAL ;
    PORT
      LAYER M5 ;
        RECT  30.48 0 30.504 0.084 ;
    END
  END i_x0[247]
  PIN i_x0[248]
    DIRECTION INPUT ;
    USE SIGNAL ;
    PORT
      LAYER M3 ;
        RECT  30.528 0 30.546 0.038 ;
    END
  END i_x0[248]
  PIN i_x0[249]
    DIRECTION INPUT ;
    USE SIGNAL ;
    PORT
      LAYER M5 ;
        RECT  30.576 0 30.6 0.084 ;
    END
  END i_x0[249]
  PIN i_x0[24]
    DIRECTION INPUT ;
    USE SIGNAL ;
    PORT
      LAYER M3 ;
        RECT  9.54 0 9.558 0.038 ;
    END
  END i_x0[24]
  PIN i_x0[250]
    DIRECTION INPUT ;
    USE SIGNAL ;
    PORT
      LAYER M3 ;
        RECT  30.636 0 30.654 0.038 ;
    END
  END i_x0[250]
  PIN i_x0[251]
    DIRECTION INPUT ;
    USE SIGNAL ;
    PORT
      LAYER M5 ;
        RECT  30.672 0 30.696 0.084 ;
    END
  END i_x0[251]
  PIN i_x0[252]
    DIRECTION INPUT ;
    USE SIGNAL ;
    PORT
      LAYER M3 ;
        RECT  30.708 0 30.726 0.038 ;
    END
  END i_x0[252]
  PIN i_x0[253]
    DIRECTION INPUT ;
    USE SIGNAL ;
    PORT
      LAYER M5 ;
        RECT  30.816 0 30.84 0.084 ;
    END
  END i_x0[253]
  PIN i_x0[254]
    DIRECTION INPUT ;
    USE SIGNAL ;
    PORT
      LAYER M3 ;
        RECT  30.924 0 30.942 0.038 ;
    END
  END i_x0[254]
  PIN i_x0[255]
    DIRECTION INPUT ;
    USE SIGNAL ;
    PORT
      LAYER M5 ;
        RECT  31.008 0 31.032 0.084 ;
    END
  END i_x0[255]
  PIN i_x0[256]
    DIRECTION INPUT ;
    USE SIGNAL ;
    PORT
      LAYER M3 ;
        RECT  31.104 0 31.122 0.038 ;
    END
  END i_x0[256]
  PIN i_x0[257]
    DIRECTION INPUT ;
    USE SIGNAL ;
    PORT
      LAYER M5 ;
        RECT  31.2 0 31.224 0.084 ;
    END
  END i_x0[257]
  PIN i_x0[258]
    DIRECTION INPUT ;
    USE SIGNAL ;
    PORT
      LAYER M3 ;
        RECT  31.284 0 31.302 0.038 ;
    END
  END i_x0[258]
  PIN i_x0[259]
    DIRECTION INPUT ;
    USE SIGNAL ;
    PORT
      LAYER M5 ;
        RECT  31.392 0 31.416 0.084 ;
    END
  END i_x0[259]
  PIN i_x0[25]
    DIRECTION INPUT ;
    USE SIGNAL ;
    PORT
      LAYER M5 ;
        RECT  9.648 0 9.672 0.084 ;
    END
  END i_x0[25]
  PIN i_x0[260]
    DIRECTION INPUT ;
    USE SIGNAL ;
    PORT
      LAYER M3 ;
        RECT  31.5 0 31.518 0.038 ;
    END
  END i_x0[260]
  PIN i_x0[261]
    DIRECTION INPUT ;
    USE SIGNAL ;
    PORT
      LAYER M5 ;
        RECT  31.584 0 31.608 0.084 ;
    END
  END i_x0[261]
  PIN i_x0[262]
    DIRECTION INPUT ;
    USE SIGNAL ;
    PORT
      LAYER M3 ;
        RECT  31.68 0 31.698 0.038 ;
    END
  END i_x0[262]
  PIN i_x0[263]
    DIRECTION INPUT ;
    USE SIGNAL ;
    PORT
      LAYER M5 ;
        RECT  31.776 0 31.8 0.084 ;
    END
  END i_x0[263]
  PIN i_x0[264]
    DIRECTION INPUT ;
    USE SIGNAL ;
    PORT
      LAYER M3 ;
        RECT  31.86 0 31.878 0.038 ;
    END
  END i_x0[264]
  PIN i_x0[265]
    DIRECTION INPUT ;
    USE SIGNAL ;
    PORT
      LAYER M5 ;
        RECT  31.968 0 31.992 0.084 ;
    END
  END i_x0[265]
  PIN i_x0[266]
    DIRECTION INPUT ;
    USE SIGNAL ;
    PORT
      LAYER M3 ;
        RECT  32.076 0 32.094 0.038 ;
    END
  END i_x0[266]
  PIN i_x0[267]
    DIRECTION INPUT ;
    USE SIGNAL ;
    PORT
      LAYER M5 ;
        RECT  32.112 0 32.136 0.084 ;
    END
  END i_x0[267]
  PIN i_x0[268]
    DIRECTION INPUT ;
    USE SIGNAL ;
    PORT
      LAYER M3 ;
        RECT  32.22 0 32.238 0.038 ;
    END
  END i_x0[268]
  PIN i_x0[269]
    DIRECTION INPUT ;
    USE SIGNAL ;
    PORT
      LAYER M5 ;
        RECT  32.304 0 32.328 0.084 ;
    END
  END i_x0[269]
  PIN i_x0[26]
    DIRECTION INPUT ;
    USE SIGNAL ;
    PORT
      LAYER M3 ;
        RECT  9.756 0 9.774 0.038 ;
    END
  END i_x0[26]
  PIN i_x0[270]
    DIRECTION INPUT ;
    USE SIGNAL ;
    PORT
      LAYER M3 ;
        RECT  32.4 0 32.418 0.038 ;
    END
  END i_x0[270]
  PIN i_x0[271]
    DIRECTION INPUT ;
    USE SIGNAL ;
    PORT
      LAYER M5 ;
        RECT  32.496 0 32.52 0.084 ;
    END
  END i_x0[271]
  PIN i_x0[272]
    DIRECTION INPUT ;
    USE SIGNAL ;
    PORT
      LAYER M3 ;
        RECT  32.58 0 32.598 0.038 ;
    END
  END i_x0[272]
  PIN i_x0[273]
    DIRECTION INPUT ;
    USE SIGNAL ;
    PORT
      LAYER M5 ;
        RECT  32.688 0 32.712 0.084 ;
    END
  END i_x0[273]
  PIN i_x0[274]
    DIRECTION INPUT ;
    USE SIGNAL ;
    PORT
      LAYER M3 ;
        RECT  32.796 0 32.814 0.038 ;
    END
  END i_x0[274]
  PIN i_x0[275]
    DIRECTION INPUT ;
    USE SIGNAL ;
    PORT
      LAYER M5 ;
        RECT  32.88 0 32.904 0.084 ;
    END
  END i_x0[275]
  PIN i_x0[276]
    DIRECTION INPUT ;
    USE SIGNAL ;
    PORT
      LAYER M3 ;
        RECT  32.976 0 32.994 0.038 ;
    END
  END i_x0[276]
  PIN i_x0[277]
    DIRECTION INPUT ;
    USE SIGNAL ;
    PORT
      LAYER M5 ;
        RECT  33.072 0 33.096 0.084 ;
    END
  END i_x0[277]
  PIN i_x0[278]
    DIRECTION INPUT ;
    USE SIGNAL ;
    PORT
      LAYER M3 ;
        RECT  33.156 0 33.174 0.038 ;
    END
  END i_x0[278]
  PIN i_x0[279]
    DIRECTION INPUT ;
    USE SIGNAL ;
    PORT
      LAYER M5 ;
        RECT  33.264 0 33.288 0.084 ;
    END
  END i_x0[279]
  PIN i_x0[27]
    DIRECTION INPUT ;
    USE SIGNAL ;
    PORT
      LAYER M5 ;
        RECT  9.84 0 9.864 0.084 ;
    END
  END i_x0[27]
  PIN i_x0[280]
    DIRECTION INPUT ;
    USE SIGNAL ;
    PORT
      LAYER M3 ;
        RECT  33.372 0 33.39 0.038 ;
    END
  END i_x0[280]
  PIN i_x0[281]
    DIRECTION INPUT ;
    USE SIGNAL ;
    PORT
      LAYER M5 ;
        RECT  33.456 0 33.48 0.084 ;
    END
  END i_x0[281]
  PIN i_x0[282]
    DIRECTION INPUT ;
    USE SIGNAL ;
    PORT
      LAYER M3 ;
        RECT  33.552 0 33.57 0.038 ;
    END
  END i_x0[282]
  PIN i_x0[28]
    DIRECTION INPUT ;
    USE SIGNAL ;
    PORT
      LAYER M3 ;
        RECT  9.9 0 9.918 0.038 ;
    END
  END i_x0[28]
  PIN i_x0[29]
    DIRECTION INPUT ;
    USE SIGNAL ;
    PORT
      LAYER M5 ;
        RECT  9.984 0 10.008 0.084 ;
    END
  END i_x0[29]
  PIN i_x0[2]
    DIRECTION INPUT ;
    USE SIGNAL ;
    PORT
      LAYER M3 ;
        RECT  7.488 0 7.506 0.038 ;
    END
  END i_x0[2]
  PIN i_x0[30]
    DIRECTION INPUT ;
    USE SIGNAL ;
    PORT
      LAYER M3 ;
        RECT  10.08 0 10.098 0.038 ;
    END
  END i_x0[30]
  PIN i_x0[31]
    DIRECTION INPUT ;
    USE SIGNAL ;
    PORT
      LAYER M5 ;
        RECT  10.176 0 10.2 0.084 ;
    END
  END i_x0[31]
  PIN i_x0[32]
    DIRECTION INPUT ;
    USE SIGNAL ;
    PORT
      LAYER M3 ;
        RECT  10.26 0 10.278 0.038 ;
    END
  END i_x0[32]
  PIN i_x0[33]
    DIRECTION INPUT ;
    USE SIGNAL ;
    PORT
      LAYER M5 ;
        RECT  10.368 0 10.392 0.084 ;
    END
  END i_x0[33]
  PIN i_x0[34]
    DIRECTION INPUT ;
    USE SIGNAL ;
    PORT
      LAYER M3 ;
        RECT  10.476 0 10.494 0.038 ;
    END
  END i_x0[34]
  PIN i_x0[35]
    DIRECTION INPUT ;
    USE SIGNAL ;
    PORT
      LAYER M5 ;
        RECT  10.56 0 10.584 0.084 ;
    END
  END i_x0[35]
  PIN i_x0[36]
    DIRECTION INPUT ;
    USE SIGNAL ;
    PORT
      LAYER M3 ;
        RECT  10.656 0 10.674 0.038 ;
    END
  END i_x0[36]
  PIN i_x0[37]
    DIRECTION INPUT ;
    USE SIGNAL ;
    PORT
      LAYER M5 ;
        RECT  10.752 0 10.776 0.084 ;
    END
  END i_x0[37]
  PIN i_x0[38]
    DIRECTION INPUT ;
    USE SIGNAL ;
    PORT
      LAYER M3 ;
        RECT  10.836 0 10.854 0.038 ;
    END
  END i_x0[38]
  PIN i_x0[39]
    DIRECTION INPUT ;
    USE SIGNAL ;
    PORT
      LAYER M5 ;
        RECT  10.944 0 10.968 0.084 ;
    END
  END i_x0[39]
  PIN i_x0[3]
    DIRECTION INPUT ;
    USE SIGNAL ;
    PORT
      LAYER M5 ;
        RECT  7.584 0 7.608 0.084 ;
    END
  END i_x0[3]
  PIN i_x0[40]
    DIRECTION INPUT ;
    USE SIGNAL ;
    PORT
      LAYER M3 ;
        RECT  11.052 0 11.07 0.038 ;
    END
  END i_x0[40]
  PIN i_x0[41]
    DIRECTION INPUT ;
    USE SIGNAL ;
    PORT
      LAYER M5 ;
        RECT  11.136 0 11.16 0.084 ;
    END
  END i_x0[41]
  PIN i_x0[42]
    DIRECTION INPUT ;
    USE SIGNAL ;
    PORT
      LAYER M3 ;
        RECT  11.232 0 11.25 0.038 ;
    END
  END i_x0[42]
  PIN i_x0[43]
    DIRECTION INPUT ;
    USE SIGNAL ;
    PORT
      LAYER M5 ;
        RECT  11.328 0 11.352 0.084 ;
    END
  END i_x0[43]
  PIN i_x0[44]
    DIRECTION INPUT ;
    USE SIGNAL ;
    PORT
      LAYER M3 ;
        RECT  11.376 0 11.394 0.038 ;
    END
  END i_x0[44]
  PIN i_x0[45]
    DIRECTION INPUT ;
    USE SIGNAL ;
    PORT
      LAYER M5 ;
        RECT  11.472 0 11.496 0.084 ;
    END
  END i_x0[45]
  PIN i_x0[46]
    DIRECTION INPUT ;
    USE SIGNAL ;
    PORT
      LAYER M3 ;
        RECT  11.556 0 11.574 0.038 ;
    END
  END i_x0[46]
  PIN i_x0[47]
    DIRECTION INPUT ;
    USE SIGNAL ;
    PORT
      LAYER M5 ;
        RECT  11.664 0 11.688 0.084 ;
    END
  END i_x0[47]
  PIN i_x0[48]
    DIRECTION INPUT ;
    USE SIGNAL ;
    PORT
      LAYER M3 ;
        RECT  11.772 0 11.79 0.038 ;
    END
  END i_x0[48]
  PIN i_x0[49]
    DIRECTION INPUT ;
    USE SIGNAL ;
    PORT
      LAYER M5 ;
        RECT  11.856 0 11.88 0.084 ;
    END
  END i_x0[49]
  PIN i_x0[4]
    DIRECTION INPUT ;
    USE SIGNAL ;
    PORT
      LAYER M3 ;
        RECT  7.668 0 7.686 0.038 ;
    END
  END i_x0[4]
  PIN i_x0[50]
    DIRECTION INPUT ;
    USE SIGNAL ;
    PORT
      LAYER M3 ;
        RECT  11.952 0 11.97 0.038 ;
    END
  END i_x0[50]
  PIN i_x0[51]
    DIRECTION INPUT ;
    USE SIGNAL ;
    PORT
      LAYER M5 ;
        RECT  12.048 0 12.072 0.084 ;
    END
  END i_x0[51]
  PIN i_x0[52]
    DIRECTION INPUT ;
    USE SIGNAL ;
    PORT
      LAYER M3 ;
        RECT  12.132 0 12.15 0.038 ;
    END
  END i_x0[52]
  PIN i_x0[53]
    DIRECTION INPUT ;
    USE SIGNAL ;
    PORT
      LAYER M5 ;
        RECT  12.24 0 12.264 0.084 ;
    END
  END i_x0[53]
  PIN i_x0[54]
    DIRECTION INPUT ;
    USE SIGNAL ;
    PORT
      LAYER M3 ;
        RECT  12.348 0 12.366 0.038 ;
    END
  END i_x0[54]
  PIN i_x0[55]
    DIRECTION INPUT ;
    USE SIGNAL ;
    PORT
      LAYER M5 ;
        RECT  12.432 0 12.456 0.084 ;
    END
  END i_x0[55]
  PIN i_x0[56]
    DIRECTION INPUT ;
    USE SIGNAL ;
    PORT
      LAYER M3 ;
        RECT  12.528 0 12.546 0.038 ;
    END
  END i_x0[56]
  PIN i_x0[57]
    DIRECTION INPUT ;
    USE SIGNAL ;
    PORT
      LAYER M5 ;
        RECT  12.624 0 12.648 0.084 ;
    END
  END i_x0[57]
  PIN i_x0[58]
    DIRECTION INPUT ;
    USE SIGNAL ;
    PORT
      LAYER M3 ;
        RECT  12.708 0 12.726 0.038 ;
    END
  END i_x0[58]
  PIN i_x0[59]
    DIRECTION INPUT ;
    USE SIGNAL ;
    PORT
      LAYER M5 ;
        RECT  12.816 0 12.84 0.084 ;
    END
  END i_x0[59]
  PIN i_x0[5]
    DIRECTION INPUT ;
    USE SIGNAL ;
    PORT
      LAYER M5 ;
        RECT  7.776 0 7.8 0.084 ;
    END
  END i_x0[5]
  PIN i_x0[60]
    DIRECTION INPUT ;
    USE SIGNAL ;
    PORT
      LAYER M3 ;
        RECT  12.852 0 12.87 0.038 ;
    END
  END i_x0[60]
  PIN i_x0[61]
    DIRECTION INPUT ;
    USE SIGNAL ;
    PORT
      LAYER M5 ;
        RECT  12.96 0 12.984 0.084 ;
    END
  END i_x0[61]
  PIN i_x0[62]
    DIRECTION INPUT ;
    USE SIGNAL ;
    PORT
      LAYER M3 ;
        RECT  13.068 0 13.086 0.038 ;
    END
  END i_x0[62]
  PIN i_x0[63]
    DIRECTION INPUT ;
    USE SIGNAL ;
    PORT
      LAYER M5 ;
        RECT  13.152 0 13.176 0.084 ;
    END
  END i_x0[63]
  PIN i_x0[64]
    DIRECTION INPUT ;
    USE SIGNAL ;
    PORT
      LAYER M3 ;
        RECT  13.248 0 13.266 0.038 ;
    END
  END i_x0[64]
  PIN i_x0[65]
    DIRECTION INPUT ;
    USE SIGNAL ;
    PORT
      LAYER M5 ;
        RECT  13.344 0 13.368 0.084 ;
    END
  END i_x0[65]
  PIN i_x0[66]
    DIRECTION INPUT ;
    USE SIGNAL ;
    PORT
      LAYER M3 ;
        RECT  13.428 0 13.446 0.038 ;
    END
  END i_x0[66]
  PIN i_x0[67]
    DIRECTION INPUT ;
    USE SIGNAL ;
    PORT
      LAYER M5 ;
        RECT  13.536 0 13.56 0.084 ;
    END
  END i_x0[67]
  PIN i_x0[68]
    DIRECTION INPUT ;
    USE SIGNAL ;
    PORT
      LAYER M3 ;
        RECT  13.644 0 13.662 0.038 ;
    END
  END i_x0[68]
  PIN i_x0[69]
    DIRECTION INPUT ;
    USE SIGNAL ;
    PORT
      LAYER M5 ;
        RECT  13.728 0 13.752 0.084 ;
    END
  END i_x0[69]
  PIN i_x0[6]
    DIRECTION INPUT ;
    USE SIGNAL ;
    PORT
      LAYER M3 ;
        RECT  7.884 0 7.902 0.038 ;
    END
  END i_x0[6]
  PIN i_x0[70]
    DIRECTION INPUT ;
    USE SIGNAL ;
    PORT
      LAYER M3 ;
        RECT  13.824 0 13.842 0.038 ;
    END
  END i_x0[70]
  PIN i_x0[71]
    DIRECTION INPUT ;
    USE SIGNAL ;
    PORT
      LAYER M5 ;
        RECT  13.92 0 13.944 0.084 ;
    END
  END i_x0[71]
  PIN i_x0[72]
    DIRECTION INPUT ;
    USE SIGNAL ;
    PORT
      LAYER M3 ;
        RECT  14.004 0 14.022 0.038 ;
    END
  END i_x0[72]
  PIN i_x0[73]
    DIRECTION INPUT ;
    USE SIGNAL ;
    PORT
      LAYER M5 ;
        RECT  14.112 0 14.136 0.084 ;
    END
  END i_x0[73]
  PIN i_x0[74]
    DIRECTION INPUT ;
    USE SIGNAL ;
    PORT
      LAYER M3 ;
        RECT  14.22 0 14.238 0.038 ;
    END
  END i_x0[74]
  PIN i_x0[75]
    DIRECTION INPUT ;
    USE SIGNAL ;
    PORT
      LAYER M5 ;
        RECT  14.304 0 14.328 0.084 ;
    END
  END i_x0[75]
  PIN i_x0[76]
    DIRECTION INPUT ;
    USE SIGNAL ;
    PORT
      LAYER M3 ;
        RECT  14.364 0 14.382 0.038 ;
    END
  END i_x0[76]
  PIN i_x0[77]
    DIRECTION INPUT ;
    USE SIGNAL ;
    PORT
      LAYER M5 ;
        RECT  14.448 0 14.472 0.084 ;
    END
  END i_x0[77]
  PIN i_x0[78]
    DIRECTION INPUT ;
    USE SIGNAL ;
    PORT
      LAYER M3 ;
        RECT  14.544 0 14.562 0.038 ;
    END
  END i_x0[78]
  PIN i_x0[79]
    DIRECTION INPUT ;
    USE SIGNAL ;
    PORT
      LAYER M5 ;
        RECT  14.64 0 14.664 0.084 ;
    END
  END i_x0[79]
  PIN i_x0[7]
    DIRECTION INPUT ;
    USE SIGNAL ;
    PORT
      LAYER M5 ;
        RECT  7.968 0 7.992 0.084 ;
    END
  END i_x0[7]
  PIN i_x0[80]
    DIRECTION INPUT ;
    USE SIGNAL ;
    PORT
      LAYER M3 ;
        RECT  14.724 0 14.742 0.038 ;
    END
  END i_x0[80]
  PIN i_x0[81]
    DIRECTION INPUT ;
    USE SIGNAL ;
    PORT
      LAYER M5 ;
        RECT  14.832 0 14.856 0.084 ;
    END
  END i_x0[81]
  PIN i_x0[82]
    DIRECTION INPUT ;
    USE SIGNAL ;
    PORT
      LAYER M3 ;
        RECT  14.94 0 14.958 0.038 ;
    END
  END i_x0[82]
  PIN i_x0[83]
    DIRECTION INPUT ;
    USE SIGNAL ;
    PORT
      LAYER M5 ;
        RECT  15.024 0 15.048 0.084 ;
    END
  END i_x0[83]
  PIN i_x0[84]
    DIRECTION INPUT ;
    USE SIGNAL ;
    PORT
      LAYER M3 ;
        RECT  15.12 0 15.138 0.038 ;
    END
  END i_x0[84]
  PIN i_x0[85]
    DIRECTION INPUT ;
    USE SIGNAL ;
    PORT
      LAYER M5 ;
        RECT  15.216 0 15.24 0.084 ;
    END
  END i_x0[85]
  PIN i_x0[86]
    DIRECTION INPUT ;
    USE SIGNAL ;
    PORT
      LAYER M3 ;
        RECT  15.3 0 15.318 0.038 ;
    END
  END i_x0[86]
  PIN i_x0[87]
    DIRECTION INPUT ;
    USE SIGNAL ;
    PORT
      LAYER M5 ;
        RECT  15.408 0 15.432 0.084 ;
    END
  END i_x0[87]
  PIN i_x0[88]
    DIRECTION INPUT ;
    USE SIGNAL ;
    PORT
      LAYER M3 ;
        RECT  15.516 0 15.534 0.038 ;
    END
  END i_x0[88]
  PIN i_x0[89]
    DIRECTION INPUT ;
    USE SIGNAL ;
    PORT
      LAYER M5 ;
        RECT  15.6 0 15.624 0.084 ;
    END
  END i_x0[89]
  PIN i_x0[8]
    DIRECTION INPUT ;
    USE SIGNAL ;
    PORT
      LAYER M3 ;
        RECT  8.064 0 8.082 0.038 ;
    END
  END i_x0[8]
  PIN i_x0[90]
    DIRECTION INPUT ;
    USE SIGNAL ;
    PORT
      LAYER M3 ;
        RECT  15.696 0 15.714 0.038 ;
    END
  END i_x0[90]
  PIN i_x0[91]
    DIRECTION INPUT ;
    USE SIGNAL ;
    PORT
      LAYER M5 ;
        RECT  15.792 0 15.816 0.084 ;
    END
  END i_x0[91]
  PIN i_x0[92]
    DIRECTION INPUT ;
    USE SIGNAL ;
    PORT
      LAYER M3 ;
        RECT  15.84 0 15.858 0.038 ;
    END
  END i_x0[92]
  PIN i_x0[93]
    DIRECTION INPUT ;
    USE SIGNAL ;
    PORT
      LAYER M5 ;
        RECT  15.936 0 15.96 0.084 ;
    END
  END i_x0[93]
  PIN i_x0[94]
    DIRECTION INPUT ;
    USE SIGNAL ;
    PORT
      LAYER M3 ;
        RECT  16.02 0 16.038 0.038 ;
    END
  END i_x0[94]
  PIN i_x0[95]
    DIRECTION INPUT ;
    USE SIGNAL ;
    PORT
      LAYER M5 ;
        RECT  16.128 0 16.152 0.084 ;
    END
  END i_x0[95]
  PIN i_x0[96]
    DIRECTION INPUT ;
    USE SIGNAL ;
    PORT
      LAYER M3 ;
        RECT  16.236 0 16.254 0.038 ;
    END
  END i_x0[96]
  PIN i_x0[97]
    DIRECTION INPUT ;
    USE SIGNAL ;
    PORT
      LAYER M5 ;
        RECT  16.32 0 16.344 0.084 ;
    END
  END i_x0[97]
  PIN i_x0[98]
    DIRECTION INPUT ;
    USE SIGNAL ;
    PORT
      LAYER M3 ;
        RECT  16.416 0 16.434 0.038 ;
    END
  END i_x0[98]
  PIN i_x0[99]
    DIRECTION INPUT ;
    USE SIGNAL ;
    PORT
      LAYER M5 ;
        RECT  16.512 0 16.536 0.084 ;
    END
  END i_x0[99]
  PIN i_x0[9]
    DIRECTION INPUT ;
    USE SIGNAL ;
    PORT
      LAYER M5 ;
        RECT  8.16 0 8.184 0.084 ;
    END
  END i_x0[9]
  PIN i_x1[0]
    DIRECTION INPUT ;
    USE SIGNAL ;
    PORT
      LAYER M5 ;
        RECT  33.6 0 33.624 0.084 ;
    END
  END i_x1[0]
  PIN i_x1[100]
    DIRECTION INPUT ;
    USE SIGNAL ;
    PORT
      LAYER M5 ;
        RECT  42.912 0 42.936 0.084 ;
    END
  END i_x1[100]
  PIN i_x1[101]
    DIRECTION INPUT ;
    USE SIGNAL ;
    PORT
      LAYER M3 ;
        RECT  43.02 0 43.038 0.038 ;
    END
  END i_x1[101]
  PIN i_x1[102]
    DIRECTION INPUT ;
    USE SIGNAL ;
    PORT
      LAYER M5 ;
        RECT  43.104 0 43.128 0.084 ;
    END
  END i_x1[102]
  PIN i_x1[103]
    DIRECTION INPUT ;
    USE SIGNAL ;
    PORT
      LAYER M3 ;
        RECT  43.2 0 43.218 0.038 ;
    END
  END i_x1[103]
  PIN i_x1[104]
    DIRECTION INPUT ;
    USE SIGNAL ;
    PORT
      LAYER M5 ;
        RECT  43.296 0 43.32 0.084 ;
    END
  END i_x1[104]
  PIN i_x1[105]
    DIRECTION INPUT ;
    USE SIGNAL ;
    PORT
      LAYER M3 ;
        RECT  43.38 0 43.398 0.038 ;
    END
  END i_x1[105]
  PIN i_x1[106]
    DIRECTION INPUT ;
    USE SIGNAL ;
    PORT
      LAYER M5 ;
        RECT  43.488 0 43.512 0.084 ;
    END
  END i_x1[106]
  PIN i_x1[107]
    DIRECTION INPUT ;
    USE SIGNAL ;
    PORT
      LAYER M3 ;
        RECT  43.596 0 43.614 0.038 ;
    END
  END i_x1[107]
  PIN i_x1[108]
    DIRECTION INPUT ;
    USE SIGNAL ;
    PORT
      LAYER M5 ;
        RECT  43.68 0 43.704 0.084 ;
    END
  END i_x1[108]
  PIN i_x1[109]
    DIRECTION INPUT ;
    USE SIGNAL ;
    PORT
      LAYER M3 ;
        RECT  43.776 0 43.794 0.038 ;
    END
  END i_x1[109]
  PIN i_x1[10]
    DIRECTION INPUT ;
    USE SIGNAL ;
    PORT
      LAYER M5 ;
        RECT  34.56 0 34.584 0.084 ;
    END
  END i_x1[10]
  PIN i_x1[110]
    DIRECTION INPUT ;
    USE SIGNAL ;
    PORT
      LAYER M5 ;
        RECT  43.872 0 43.896 0.084 ;
    END
  END i_x1[110]
  PIN i_x1[111]
    DIRECTION INPUT ;
    USE SIGNAL ;
    PORT
      LAYER M3 ;
        RECT  43.92 0 43.938 0.038 ;
    END
  END i_x1[111]
  PIN i_x1[112]
    DIRECTION INPUT ;
    USE SIGNAL ;
    PORT
      LAYER M5 ;
        RECT  44.016 0 44.04 0.084 ;
    END
  END i_x1[112]
  PIN i_x1[113]
    DIRECTION INPUT ;
    USE SIGNAL ;
    PORT
      LAYER M3 ;
        RECT  44.1 0 44.118 0.038 ;
    END
  END i_x1[113]
  PIN i_x1[114]
    DIRECTION INPUT ;
    USE SIGNAL ;
    PORT
      LAYER M5 ;
        RECT  44.208 0 44.232 0.084 ;
    END
  END i_x1[114]
  PIN i_x1[115]
    DIRECTION INPUT ;
    USE SIGNAL ;
    PORT
      LAYER M3 ;
        RECT  44.316 0 44.334 0.038 ;
    END
  END i_x1[115]
  PIN i_x1[116]
    DIRECTION INPUT ;
    USE SIGNAL ;
    PORT
      LAYER M5 ;
        RECT  44.4 0 44.424 0.084 ;
    END
  END i_x1[116]
  PIN i_x1[117]
    DIRECTION INPUT ;
    USE SIGNAL ;
    PORT
      LAYER M3 ;
        RECT  44.496 0 44.514 0.038 ;
    END
  END i_x1[117]
  PIN i_x1[118]
    DIRECTION INPUT ;
    USE SIGNAL ;
    PORT
      LAYER M5 ;
        RECT  44.592 0 44.616 0.084 ;
    END
  END i_x1[118]
  PIN i_x1[119]
    DIRECTION INPUT ;
    USE SIGNAL ;
    PORT
      LAYER M3 ;
        RECT  44.676 0 44.694 0.038 ;
    END
  END i_x1[119]
  PIN i_x1[11]
    DIRECTION INPUT ;
    USE SIGNAL ;
    PORT
      LAYER M3 ;
        RECT  34.668 0 34.686 0.038 ;
    END
  END i_x1[11]
  PIN i_x1[120]
    DIRECTION INPUT ;
    USE SIGNAL ;
    PORT
      LAYER M5 ;
        RECT  44.784 0 44.808 0.084 ;
    END
  END i_x1[120]
  PIN i_x1[121]
    DIRECTION INPUT ;
    USE SIGNAL ;
    PORT
      LAYER M3 ;
        RECT  44.892 0 44.91 0.038 ;
    END
  END i_x1[121]
  PIN i_x1[122]
    DIRECTION INPUT ;
    USE SIGNAL ;
    PORT
      LAYER M5 ;
        RECT  44.976 0 45 0.084 ;
    END
  END i_x1[122]
  PIN i_x1[123]
    DIRECTION INPUT ;
    USE SIGNAL ;
    PORT
      LAYER M3 ;
        RECT  45.072 0 45.09 0.038 ;
    END
  END i_x1[123]
  PIN i_x1[124]
    DIRECTION INPUT ;
    USE SIGNAL ;
    PORT
      LAYER M5 ;
        RECT  45.168 0 45.192 0.084 ;
    END
  END i_x1[124]
  PIN i_x1[125]
    DIRECTION INPUT ;
    USE SIGNAL ;
    PORT
      LAYER M3 ;
        RECT  45.252 0 45.27 0.038 ;
    END
  END i_x1[125]
  PIN i_x1[126]
    DIRECTION INPUT ;
    USE SIGNAL ;
    PORT
      LAYER M5 ;
        RECT  45.36 0 45.384 0.084 ;
    END
  END i_x1[126]
  PIN i_x1[127]
    DIRECTION INPUT ;
    USE SIGNAL ;
    PORT
      LAYER M3 ;
        RECT  45.396 0 45.414 0.038 ;
    END
  END i_x1[127]
  PIN i_x1[128]
    DIRECTION INPUT ;
    USE SIGNAL ;
    PORT
      LAYER M5 ;
        RECT  45.504 0 45.528 0.084 ;
    END
  END i_x1[128]
  PIN i_x1[129]
    DIRECTION INPUT ;
    USE SIGNAL ;
    PORT
      LAYER M3 ;
        RECT  45.612 0 45.63 0.038 ;
    END
  END i_x1[129]
  PIN i_x1[12]
    DIRECTION INPUT ;
    USE SIGNAL ;
    PORT
      LAYER M5 ;
        RECT  34.752 0 34.776 0.084 ;
    END
  END i_x1[12]
  PIN i_x1[130]
    DIRECTION INPUT ;
    USE SIGNAL ;
    PORT
      LAYER M5 ;
        RECT  45.696 0 45.72 0.084 ;
    END
  END i_x1[130]
  PIN i_x1[131]
    DIRECTION INPUT ;
    USE SIGNAL ;
    PORT
      LAYER M3 ;
        RECT  45.792 0 45.81 0.038 ;
    END
  END i_x1[131]
  PIN i_x1[132]
    DIRECTION INPUT ;
    USE SIGNAL ;
    PORT
      LAYER M5 ;
        RECT  45.888 0 45.912 0.084 ;
    END
  END i_x1[132]
  PIN i_x1[133]
    DIRECTION INPUT ;
    USE SIGNAL ;
    PORT
      LAYER M3 ;
        RECT  45.972 0 45.99 0.038 ;
    END
  END i_x1[133]
  PIN i_x1[134]
    DIRECTION INPUT ;
    USE SIGNAL ;
    PORT
      LAYER M5 ;
        RECT  46.08 0 46.104 0.084 ;
    END
  END i_x1[134]
  PIN i_x1[135]
    DIRECTION INPUT ;
    USE SIGNAL ;
    PORT
      LAYER M3 ;
        RECT  46.188 0 46.206 0.038 ;
    END
  END i_x1[135]
  PIN i_x1[136]
    DIRECTION INPUT ;
    USE SIGNAL ;
    PORT
      LAYER M5 ;
        RECT  46.272 0 46.296 0.084 ;
    END
  END i_x1[136]
  PIN i_x1[137]
    DIRECTION INPUT ;
    USE SIGNAL ;
    PORT
      LAYER M3 ;
        RECT  46.368 0 46.386 0.038 ;
    END
  END i_x1[137]
  PIN i_x1[138]
    DIRECTION INPUT ;
    USE SIGNAL ;
    PORT
      LAYER M5 ;
        RECT  46.464 0 46.488 0.084 ;
    END
  END i_x1[138]
  PIN i_x1[139]
    DIRECTION INPUT ;
    USE SIGNAL ;
    PORT
      LAYER M3 ;
        RECT  46.548 0 46.566 0.038 ;
    END
  END i_x1[139]
  PIN i_x1[13]
    DIRECTION INPUT ;
    USE SIGNAL ;
    PORT
      LAYER M3 ;
        RECT  34.848 0 34.866 0.038 ;
    END
  END i_x1[13]
  PIN i_x1[140]
    DIRECTION INPUT ;
    USE SIGNAL ;
    PORT
      LAYER M5 ;
        RECT  46.656 0 46.68 0.084 ;
    END
  END i_x1[140]
  PIN i_x1[141]
    DIRECTION INPUT ;
    USE SIGNAL ;
    PORT
      LAYER M3 ;
        RECT  46.764 0 46.782 0.038 ;
    END
  END i_x1[141]
  PIN i_x1[142]
    DIRECTION INPUT ;
    USE SIGNAL ;
    PORT
      LAYER M5 ;
        RECT  46.848 0 46.872 0.084 ;
    END
  END i_x1[142]
  PIN i_x1[143]
    DIRECTION INPUT ;
    USE SIGNAL ;
    PORT
      LAYER M3 ;
        RECT  46.908 0 46.926 0.038 ;
    END
  END i_x1[143]
  PIN i_x1[144]
    DIRECTION INPUT ;
    USE SIGNAL ;
    PORT
      LAYER M5 ;
        RECT  46.992 0 47.016 0.084 ;
    END
  END i_x1[144]
  PIN i_x1[145]
    DIRECTION INPUT ;
    USE SIGNAL ;
    PORT
      LAYER M3 ;
        RECT  47.088 0 47.106 0.038 ;
    END
  END i_x1[145]
  PIN i_x1[146]
    DIRECTION INPUT ;
    USE SIGNAL ;
    PORT
      LAYER M5 ;
        RECT  47.184 0 47.208 0.084 ;
    END
  END i_x1[146]
  PIN i_x1[147]
    DIRECTION INPUT ;
    USE SIGNAL ;
    PORT
      LAYER M3 ;
        RECT  47.268 0 47.286 0.038 ;
    END
  END i_x1[147]
  PIN i_x1[148]
    DIRECTION INPUT ;
    USE SIGNAL ;
    PORT
      LAYER M5 ;
        RECT  47.376 0 47.4 0.084 ;
    END
  END i_x1[148]
  PIN i_x1[149]
    DIRECTION INPUT ;
    USE SIGNAL ;
    PORT
      LAYER M3 ;
        RECT  47.484 0 47.502 0.038 ;
    END
  END i_x1[149]
  PIN i_x1[14]
    DIRECTION INPUT ;
    USE SIGNAL ;
    PORT
      LAYER M5 ;
        RECT  34.944 0 34.968 0.084 ;
    END
  END i_x1[14]
  PIN i_x1[150]
    DIRECTION INPUT ;
    USE SIGNAL ;
    PORT
      LAYER M5 ;
        RECT  47.568 0 47.592 0.084 ;
    END
  END i_x1[150]
  PIN i_x1[151]
    DIRECTION INPUT ;
    USE SIGNAL ;
    PORT
      LAYER M3 ;
        RECT  47.664 0 47.682 0.038 ;
    END
  END i_x1[151]
  PIN i_x1[152]
    DIRECTION INPUT ;
    USE SIGNAL ;
    PORT
      LAYER M5 ;
        RECT  47.76 0 47.784 0.084 ;
    END
  END i_x1[152]
  PIN i_x1[153]
    DIRECTION INPUT ;
    USE SIGNAL ;
    PORT
      LAYER M3 ;
        RECT  47.844 0 47.862 0.038 ;
    END
  END i_x1[153]
  PIN i_x1[154]
    DIRECTION INPUT ;
    USE SIGNAL ;
    PORT
      LAYER M5 ;
        RECT  47.952 0 47.976 0.084 ;
    END
  END i_x1[154]
  PIN i_x1[155]
    DIRECTION INPUT ;
    USE SIGNAL ;
    PORT
      LAYER M3 ;
        RECT  48.06 0 48.078 0.038 ;
    END
  END i_x1[155]
  PIN i_x1[156]
    DIRECTION INPUT ;
    USE SIGNAL ;
    PORT
      LAYER M5 ;
        RECT  48.144 0 48.168 0.084 ;
    END
  END i_x1[156]
  PIN i_x1[157]
    DIRECTION INPUT ;
    USE SIGNAL ;
    PORT
      LAYER M3 ;
        RECT  48.24 0 48.258 0.038 ;
    END
  END i_x1[157]
  PIN i_x1[158]
    DIRECTION INPUT ;
    USE SIGNAL ;
    PORT
      LAYER M5 ;
        RECT  48.336 0 48.36 0.084 ;
    END
  END i_x1[158]
  PIN i_x1[159]
    DIRECTION INPUT ;
    USE SIGNAL ;
    PORT
      LAYER M3 ;
        RECT  48.384 0 48.402 0.038 ;
    END
  END i_x1[159]
  PIN i_x1[15]
    DIRECTION INPUT ;
    USE SIGNAL ;
    PORT
      LAYER M3 ;
        RECT  35.028 0 35.046 0.038 ;
    END
  END i_x1[15]
  PIN i_x1[160]
    DIRECTION INPUT ;
    USE SIGNAL ;
    PORT
      LAYER M5 ;
        RECT  48.48 0 48.504 0.084 ;
    END
  END i_x1[160]
  PIN i_x1[161]
    DIRECTION INPUT ;
    USE SIGNAL ;
    PORT
      LAYER M3 ;
        RECT  48.564 0 48.582 0.038 ;
    END
  END i_x1[161]
  PIN i_x1[162]
    DIRECTION INPUT ;
    USE SIGNAL ;
    PORT
      LAYER M5 ;
        RECT  48.672 0 48.696 0.084 ;
    END
  END i_x1[162]
  PIN i_x1[163]
    DIRECTION INPUT ;
    USE SIGNAL ;
    PORT
      LAYER M3 ;
        RECT  48.78 0 48.798 0.038 ;
    END
  END i_x1[163]
  PIN i_x1[164]
    DIRECTION INPUT ;
    USE SIGNAL ;
    PORT
      LAYER M5 ;
        RECT  48.864 0 48.888 0.084 ;
    END
  END i_x1[164]
  PIN i_x1[165]
    DIRECTION INPUT ;
    USE SIGNAL ;
    PORT
      LAYER M3 ;
        RECT  48.96 0 48.978 0.038 ;
    END
  END i_x1[165]
  PIN i_x1[166]
    DIRECTION INPUT ;
    USE SIGNAL ;
    PORT
      LAYER M5 ;
        RECT  49.056 0 49.08 0.084 ;
    END
  END i_x1[166]
  PIN i_x1[167]
    DIRECTION INPUT ;
    USE SIGNAL ;
    PORT
      LAYER M3 ;
        RECT  49.14 0 49.158 0.038 ;
    END
  END i_x1[167]
  PIN i_x1[168]
    DIRECTION INPUT ;
    USE SIGNAL ;
    PORT
      LAYER M5 ;
        RECT  49.248 0 49.272 0.084 ;
    END
  END i_x1[168]
  PIN i_x1[169]
    DIRECTION INPUT ;
    USE SIGNAL ;
    PORT
      LAYER M3 ;
        RECT  49.356 0 49.374 0.038 ;
    END
  END i_x1[169]
  PIN i_x1[16]
    DIRECTION INPUT ;
    USE SIGNAL ;
    PORT
      LAYER M5 ;
        RECT  35.088 0 35.112 0.084 ;
    END
  END i_x1[16]
  PIN i_x1[170]
    DIRECTION INPUT ;
    USE SIGNAL ;
    PORT
      LAYER M5 ;
        RECT  49.44 0 49.464 0.084 ;
    END
  END i_x1[170]
  PIN i_x1[171]
    DIRECTION INPUT ;
    USE SIGNAL ;
    PORT
      LAYER M3 ;
        RECT  49.536 0 49.554 0.038 ;
    END
  END i_x1[171]
  PIN i_x1[172]
    DIRECTION INPUT ;
    USE SIGNAL ;
    PORT
      LAYER M5 ;
        RECT  49.632 0 49.656 0.084 ;
    END
  END i_x1[172]
  PIN i_x1[173]
    DIRECTION INPUT ;
    USE SIGNAL ;
    PORT
      LAYER M3 ;
        RECT  49.716 0 49.734 0.038 ;
    END
  END i_x1[173]
  PIN i_x1[174]
    DIRECTION INPUT ;
    USE SIGNAL ;
    PORT
      LAYER M5 ;
        RECT  49.824 0 49.848 0.084 ;
    END
  END i_x1[174]
  PIN i_x1[175]
    DIRECTION INPUT ;
    USE SIGNAL ;
    PORT
      LAYER M3 ;
        RECT  49.86 0 49.878 0.038 ;
    END
  END i_x1[175]
  PIN i_x1[176]
    DIRECTION INPUT ;
    USE SIGNAL ;
    PORT
      LAYER M5 ;
        RECT  49.968 0 49.992 0.084 ;
    END
  END i_x1[176]
  PIN i_x1[177]
    DIRECTION INPUT ;
    USE SIGNAL ;
    PORT
      LAYER M3 ;
        RECT  50.076 0 50.094 0.038 ;
    END
  END i_x1[177]
  PIN i_x1[178]
    DIRECTION INPUT ;
    USE SIGNAL ;
    PORT
      LAYER M5 ;
        RECT  50.16 0 50.184 0.084 ;
    END
  END i_x1[178]
  PIN i_x1[179]
    DIRECTION INPUT ;
    USE SIGNAL ;
    PORT
      LAYER M3 ;
        RECT  50.256 0 50.274 0.038 ;
    END
  END i_x1[179]
  PIN i_x1[17]
    DIRECTION INPUT ;
    USE SIGNAL ;
    PORT
      LAYER M3 ;
        RECT  35.172 0 35.19 0.038 ;
    END
  END i_x1[17]
  PIN i_x1[180]
    DIRECTION INPUT ;
    USE SIGNAL ;
    PORT
      LAYER M5 ;
        RECT  50.352 0 50.376 0.084 ;
    END
  END i_x1[180]
  PIN i_x1[181]
    DIRECTION INPUT ;
    USE SIGNAL ;
    PORT
      LAYER M3 ;
        RECT  50.436 0 50.454 0.038 ;
    END
  END i_x1[181]
  PIN i_x1[182]
    DIRECTION INPUT ;
    USE SIGNAL ;
    PORT
      LAYER M5 ;
        RECT  50.544 0 50.568 0.084 ;
    END
  END i_x1[182]
  PIN i_x1[183]
    DIRECTION INPUT ;
    USE SIGNAL ;
    PORT
      LAYER M3 ;
        RECT  50.652 0 50.67 0.038 ;
    END
  END i_x1[183]
  PIN i_x1[184]
    DIRECTION INPUT ;
    USE SIGNAL ;
    PORT
      LAYER M5 ;
        RECT  50.736 0 50.76 0.084 ;
    END
  END i_x1[184]
  PIN i_x1[185]
    DIRECTION INPUT ;
    USE SIGNAL ;
    PORT
      LAYER M3 ;
        RECT  50.832 0 50.85 0.038 ;
    END
  END i_x1[185]
  PIN i_x1[186]
    DIRECTION INPUT ;
    USE SIGNAL ;
    PORT
      LAYER M5 ;
        RECT  50.928 0 50.952 0.084 ;
    END
  END i_x1[186]
  PIN i_x1[187]
    DIRECTION INPUT ;
    USE SIGNAL ;
    PORT
      LAYER M3 ;
        RECT  51.012 0 51.03 0.038 ;
    END
  END i_x1[187]
  PIN i_x1[188]
    DIRECTION INPUT ;
    USE SIGNAL ;
    PORT
      LAYER M5 ;
        RECT  51.12 0 51.144 0.084 ;
    END
  END i_x1[188]
  PIN i_x1[189]
    DIRECTION INPUT ;
    USE SIGNAL ;
    PORT
      LAYER M3 ;
        RECT  51.228 0 51.246 0.038 ;
    END
  END i_x1[189]
  PIN i_x1[18]
    DIRECTION INPUT ;
    USE SIGNAL ;
    PORT
      LAYER M5 ;
        RECT  35.28 0 35.304 0.084 ;
    END
  END i_x1[18]
  PIN i_x1[190]
    DIRECTION INPUT ;
    USE SIGNAL ;
    PORT
      LAYER M5 ;
        RECT  51.264 0 51.288 0.084 ;
    END
  END i_x1[190]
  PIN i_x1[191]
    DIRECTION INPUT ;
    USE SIGNAL ;
    PORT
      LAYER M3 ;
        RECT  51.372 0 51.39 0.038 ;
    END
  END i_x1[191]
  PIN i_x1[192]
    DIRECTION INPUT ;
    USE SIGNAL ;
    PORT
      LAYER M5 ;
        RECT  51.456 0 51.48 0.084 ;
    END
  END i_x1[192]
  PIN i_x1[193]
    DIRECTION INPUT ;
    USE SIGNAL ;
    PORT
      LAYER M3 ;
        RECT  51.552 0 51.57 0.038 ;
    END
  END i_x1[193]
  PIN i_x1[194]
    DIRECTION INPUT ;
    USE SIGNAL ;
    PORT
      LAYER M5 ;
        RECT  51.648 0 51.672 0.084 ;
    END
  END i_x1[194]
  PIN i_x1[195]
    DIRECTION INPUT ;
    USE SIGNAL ;
    PORT
      LAYER M3 ;
        RECT  51.732 0 51.75 0.038 ;
    END
  END i_x1[195]
  PIN i_x1[196]
    DIRECTION INPUT ;
    USE SIGNAL ;
    PORT
      LAYER M5 ;
        RECT  51.84 0 51.864 0.084 ;
    END
  END i_x1[196]
  PIN i_x1[197]
    DIRECTION INPUT ;
    USE SIGNAL ;
    PORT
      LAYER M3 ;
        RECT  51.948 0 51.966 0.038 ;
    END
  END i_x1[197]
  PIN i_x1[198]
    DIRECTION INPUT ;
    USE SIGNAL ;
    PORT
      LAYER M5 ;
        RECT  52.032 0 52.056 0.084 ;
    END
  END i_x1[198]
  PIN i_x1[199]
    DIRECTION INPUT ;
    USE SIGNAL ;
    PORT
      LAYER M3 ;
        RECT  52.128 0 52.146 0.038 ;
    END
  END i_x1[199]
  PIN i_x1[19]
    DIRECTION INPUT ;
    USE SIGNAL ;
    PORT
      LAYER M3 ;
        RECT  35.388 0 35.406 0.038 ;
    END
  END i_x1[19]
  PIN i_x1[1]
    DIRECTION INPUT ;
    USE SIGNAL ;
    PORT
      LAYER M3 ;
        RECT  33.696 0 33.714 0.038 ;
    END
  END i_x1[1]
  PIN i_x1[200]
    DIRECTION INPUT ;
    USE SIGNAL ;
    PORT
      LAYER M5 ;
        RECT  52.224 0 52.248 0.084 ;
    END
  END i_x1[200]
  PIN i_x1[201]
    DIRECTION INPUT ;
    USE SIGNAL ;
    PORT
      LAYER M3 ;
        RECT  52.308 0 52.326 0.038 ;
    END
  END i_x1[201]
  PIN i_x1[202]
    DIRECTION INPUT ;
    USE SIGNAL ;
    PORT
      LAYER M5 ;
        RECT  52.416 0 52.44 0.084 ;
    END
  END i_x1[202]
  PIN i_x1[203]
    DIRECTION INPUT ;
    USE SIGNAL ;
    PORT
      LAYER M3 ;
        RECT  52.524 0 52.542 0.038 ;
    END
  END i_x1[203]
  PIN i_x1[204]
    DIRECTION INPUT ;
    USE SIGNAL ;
    PORT
      LAYER M5 ;
        RECT  52.608 0 52.632 0.084 ;
    END
  END i_x1[204]
  PIN i_x1[205]
    DIRECTION INPUT ;
    USE SIGNAL ;
    PORT
      LAYER M3 ;
        RECT  52.704 0 52.722 0.038 ;
    END
  END i_x1[205]
  PIN i_x1[206]
    DIRECTION INPUT ;
    USE SIGNAL ;
    PORT
      LAYER M5 ;
        RECT  52.752 0 52.776 0.084 ;
    END
  END i_x1[206]
  PIN i_x1[207]
    DIRECTION INPUT ;
    USE SIGNAL ;
    PORT
      LAYER M3 ;
        RECT  52.848 0 52.866 0.038 ;
    END
  END i_x1[207]
  PIN i_x1[208]
    DIRECTION INPUT ;
    USE SIGNAL ;
    PORT
      LAYER M5 ;
        RECT  52.944 0 52.968 0.084 ;
    END
  END i_x1[208]
  PIN i_x1[209]
    DIRECTION INPUT ;
    USE SIGNAL ;
    PORT
      LAYER M3 ;
        RECT  53.028 0 53.046 0.038 ;
    END
  END i_x1[209]
  PIN i_x1[20]
    DIRECTION INPUT ;
    USE SIGNAL ;
    PORT
      LAYER M5 ;
        RECT  35.472 0 35.496 0.084 ;
    END
  END i_x1[20]
  PIN i_x1[210]
    DIRECTION INPUT ;
    USE SIGNAL ;
    PORT
      LAYER M5 ;
        RECT  53.136 0 53.16 0.084 ;
    END
  END i_x1[210]
  PIN i_x1[211]
    DIRECTION INPUT ;
    USE SIGNAL ;
    PORT
      LAYER M3 ;
        RECT  53.244 0 53.262 0.038 ;
    END
  END i_x1[211]
  PIN i_x1[212]
    DIRECTION INPUT ;
    USE SIGNAL ;
    PORT
      LAYER M5 ;
        RECT  53.328 0 53.352 0.084 ;
    END
  END i_x1[212]
  PIN i_x1[213]
    DIRECTION INPUT ;
    USE SIGNAL ;
    PORT
      LAYER M3 ;
        RECT  53.424 0 53.442 0.038 ;
    END
  END i_x1[213]
  PIN i_x1[214]
    DIRECTION INPUT ;
    USE SIGNAL ;
    PORT
      LAYER M5 ;
        RECT  53.52 0 53.544 0.084 ;
    END
  END i_x1[214]
  PIN i_x1[215]
    DIRECTION INPUT ;
    USE SIGNAL ;
    PORT
      LAYER M3 ;
        RECT  53.604 0 53.622 0.038 ;
    END
  END i_x1[215]
  PIN i_x1[216]
    DIRECTION INPUT ;
    USE SIGNAL ;
    PORT
      LAYER M5 ;
        RECT  53.712 0 53.736 0.084 ;
    END
  END i_x1[216]
  PIN i_x1[217]
    DIRECTION INPUT ;
    USE SIGNAL ;
    PORT
      LAYER M3 ;
        RECT  53.82 0 53.838 0.038 ;
    END
  END i_x1[217]
  PIN i_x1[218]
    DIRECTION INPUT ;
    USE SIGNAL ;
    PORT
      LAYER M5 ;
        RECT  53.904 0 53.928 0.084 ;
    END
  END i_x1[218]
  PIN i_x1[219]
    DIRECTION INPUT ;
    USE SIGNAL ;
    PORT
      LAYER M3 ;
        RECT  54 0 54.018 0.038 ;
    END
  END i_x1[219]
  PIN i_x1[21]
    DIRECTION INPUT ;
    USE SIGNAL ;
    PORT
      LAYER M3 ;
        RECT  35.568 0 35.586 0.038 ;
    END
  END i_x1[21]
  PIN i_x1[220]
    DIRECTION INPUT ;
    USE SIGNAL ;
    PORT
      LAYER M5 ;
        RECT  54.096 0 54.12 0.084 ;
    END
  END i_x1[220]
  PIN i_x1[221]
    DIRECTION INPUT ;
    USE SIGNAL ;
    PORT
      LAYER M3 ;
        RECT  54.18 0 54.198 0.038 ;
    END
  END i_x1[221]
  PIN i_x1[222]
    DIRECTION INPUT ;
    USE SIGNAL ;
    PORT
      LAYER M5 ;
        RECT  54.24 0 54.264 0.084 ;
    END
  END i_x1[222]
  PIN i_x1[223]
    DIRECTION INPUT ;
    USE SIGNAL ;
    PORT
      LAYER M3 ;
        RECT  54.324 0 54.342 0.038 ;
    END
  END i_x1[223]
  PIN i_x1[224]
    DIRECTION INPUT ;
    USE SIGNAL ;
    PORT
      LAYER M5 ;
        RECT  54.432 0 54.456 0.084 ;
    END
  END i_x1[224]
  PIN i_x1[225]
    DIRECTION INPUT ;
    USE SIGNAL ;
    PORT
      LAYER M3 ;
        RECT  54.54 0 54.558 0.038 ;
    END
  END i_x1[225]
  PIN i_x1[226]
    DIRECTION INPUT ;
    USE SIGNAL ;
    PORT
      LAYER M5 ;
        RECT  54.624 0 54.648 0.084 ;
    END
  END i_x1[226]
  PIN i_x1[227]
    DIRECTION INPUT ;
    USE SIGNAL ;
    PORT
      LAYER M3 ;
        RECT  54.72 0 54.738 0.038 ;
    END
  END i_x1[227]
  PIN i_x1[228]
    DIRECTION INPUT ;
    USE SIGNAL ;
    PORT
      LAYER M5 ;
        RECT  54.816 0 54.84 0.084 ;
    END
  END i_x1[228]
  PIN i_x1[229]
    DIRECTION INPUT ;
    USE SIGNAL ;
    PORT
      LAYER M3 ;
        RECT  54.9 0 54.918 0.038 ;
    END
  END i_x1[229]
  PIN i_x1[22]
    DIRECTION INPUT ;
    USE SIGNAL ;
    PORT
      LAYER M5 ;
        RECT  35.664 0 35.688 0.084 ;
    END
  END i_x1[22]
  PIN i_x1[230]
    DIRECTION INPUT ;
    USE SIGNAL ;
    PORT
      LAYER M5 ;
        RECT  55.008 0 55.032 0.084 ;
    END
  END i_x1[230]
  PIN i_x1[231]
    DIRECTION INPUT ;
    USE SIGNAL ;
    PORT
      LAYER M3 ;
        RECT  55.116 0 55.134 0.038 ;
    END
  END i_x1[231]
  PIN i_x1[232]
    DIRECTION INPUT ;
    USE SIGNAL ;
    PORT
      LAYER M5 ;
        RECT  55.2 0 55.224 0.084 ;
    END
  END i_x1[232]
  PIN i_x1[233]
    DIRECTION INPUT ;
    USE SIGNAL ;
    PORT
      LAYER M3 ;
        RECT  55.296 0 55.314 0.038 ;
    END
  END i_x1[233]
  PIN i_x1[234]
    DIRECTION INPUT ;
    USE SIGNAL ;
    PORT
      LAYER M5 ;
        RECT  55.392 0 55.416 0.084 ;
    END
  END i_x1[234]
  PIN i_x1[235]
    DIRECTION INPUT ;
    USE SIGNAL ;
    PORT
      LAYER M3 ;
        RECT  55.476 0 55.494 0.038 ;
    END
  END i_x1[235]
  PIN i_x1[236]
    DIRECTION INPUT ;
    USE SIGNAL ;
    PORT
      LAYER M5 ;
        RECT  55.584 0 55.608 0.084 ;
    END
  END i_x1[236]
  PIN i_x1[237]
    DIRECTION INPUT ;
    USE SIGNAL ;
    PORT
      LAYER M3 ;
        RECT  55.692 0 55.71 0.038 ;
    END
  END i_x1[237]
  PIN i_x1[238]
    DIRECTION INPUT ;
    USE SIGNAL ;
    PORT
      LAYER M5 ;
        RECT  55.728 0 55.752 0.084 ;
    END
  END i_x1[238]
  PIN i_x1[239]
    DIRECTION INPUT ;
    USE SIGNAL ;
    PORT
      LAYER M3 ;
        RECT  55.836 0 55.854 0.038 ;
    END
  END i_x1[239]
  PIN i_x1[23]
    DIRECTION INPUT ;
    USE SIGNAL ;
    PORT
      LAYER M3 ;
        RECT  35.748 0 35.766 0.038 ;
    END
  END i_x1[23]
  PIN i_x1[240]
    DIRECTION INPUT ;
    USE SIGNAL ;
    PORT
      LAYER M5 ;
        RECT  55.92 0 55.944 0.084 ;
    END
  END i_x1[240]
  PIN i_x1[241]
    DIRECTION INPUT ;
    USE SIGNAL ;
    PORT
      LAYER M3 ;
        RECT  56.016 0 56.034 0.038 ;
    END
  END i_x1[241]
  PIN i_x1[242]
    DIRECTION INPUT ;
    USE SIGNAL ;
    PORT
      LAYER M5 ;
        RECT  56.112 0 56.136 0.084 ;
    END
  END i_x1[242]
  PIN i_x1[243]
    DIRECTION INPUT ;
    USE SIGNAL ;
    PORT
      LAYER M3 ;
        RECT  56.196 0 56.214 0.038 ;
    END
  END i_x1[243]
  PIN i_x1[244]
    DIRECTION INPUT ;
    USE SIGNAL ;
    PORT
      LAYER M5 ;
        RECT  56.304 0 56.328 0.084 ;
    END
  END i_x1[244]
  PIN i_x1[245]
    DIRECTION INPUT ;
    USE SIGNAL ;
    PORT
      LAYER M3 ;
        RECT  56.412 0 56.43 0.038 ;
    END
  END i_x1[245]
  PIN i_x1[246]
    DIRECTION INPUT ;
    USE SIGNAL ;
    PORT
      LAYER M5 ;
        RECT  56.496 0 56.52 0.084 ;
    END
  END i_x1[246]
  PIN i_x1[247]
    DIRECTION INPUT ;
    USE SIGNAL ;
    PORT
      LAYER M3 ;
        RECT  56.592 0 56.61 0.038 ;
    END
  END i_x1[247]
  PIN i_x1[248]
    DIRECTION INPUT ;
    USE SIGNAL ;
    PORT
      LAYER M5 ;
        RECT  56.688 0 56.712 0.084 ;
    END
  END i_x1[248]
  PIN i_x1[249]
    DIRECTION INPUT ;
    USE SIGNAL ;
    PORT
      LAYER M3 ;
        RECT  56.772 0 56.79 0.038 ;
    END
  END i_x1[249]
  PIN i_x1[24]
    DIRECTION INPUT ;
    USE SIGNAL ;
    PORT
      LAYER M5 ;
        RECT  35.856 0 35.88 0.084 ;
    END
  END i_x1[24]
  PIN i_x1[250]
    DIRECTION INPUT ;
    USE SIGNAL ;
    PORT
      LAYER M5 ;
        RECT  56.88 0 56.904 0.084 ;
    END
  END i_x1[250]
  PIN i_x1[251]
    DIRECTION INPUT ;
    USE SIGNAL ;
    PORT
      LAYER M3 ;
        RECT  56.988 0 57.006 0.038 ;
    END
  END i_x1[251]
  PIN i_x1[252]
    DIRECTION INPUT ;
    USE SIGNAL ;
    PORT
      LAYER M5 ;
        RECT  57.072 0 57.096 0.084 ;
    END
  END i_x1[252]
  PIN i_x1[253]
    DIRECTION INPUT ;
    USE SIGNAL ;
    PORT
      LAYER M3 ;
        RECT  57.168 0 57.186 0.038 ;
    END
  END i_x1[253]
  PIN i_x1[254]
    DIRECTION INPUT ;
    USE SIGNAL ;
    PORT
      LAYER M5 ;
        RECT  57.216 0 57.24 0.084 ;
    END
  END i_x1[254]
  PIN i_x1[255]
    DIRECTION INPUT ;
    USE SIGNAL ;
    PORT
      LAYER M3 ;
        RECT  57.312 0 57.33 0.038 ;
    END
  END i_x1[255]
  PIN i_x1[256]
    DIRECTION INPUT ;
    USE SIGNAL ;
    PORT
      LAYER M5 ;
        RECT  57.408 0 57.432 0.084 ;
    END
  END i_x1[256]
  PIN i_x1[257]
    DIRECTION INPUT ;
    USE SIGNAL ;
    PORT
      LAYER M3 ;
        RECT  57.492 0 57.51 0.038 ;
    END
  END i_x1[257]
  PIN i_x1[258]
    DIRECTION INPUT ;
    USE SIGNAL ;
    PORT
      LAYER M5 ;
        RECT  57.6 0 57.624 0.084 ;
    END
  END i_x1[258]
  PIN i_x1[259]
    DIRECTION INPUT ;
    USE SIGNAL ;
    PORT
      LAYER M3 ;
        RECT  57.708 0 57.726 0.038 ;
    END
  END i_x1[259]
  PIN i_x1[25]
    DIRECTION INPUT ;
    USE SIGNAL ;
    PORT
      LAYER M3 ;
        RECT  35.964 0 35.982 0.038 ;
    END
  END i_x1[25]
  PIN i_x1[260]
    DIRECTION INPUT ;
    USE SIGNAL ;
    PORT
      LAYER M5 ;
        RECT  57.792 0 57.816 0.084 ;
    END
  END i_x1[260]
  PIN i_x1[261]
    DIRECTION INPUT ;
    USE SIGNAL ;
    PORT
      LAYER M3 ;
        RECT  57.888 0 57.906 0.038 ;
    END
  END i_x1[261]
  PIN i_x1[262]
    DIRECTION INPUT ;
    USE SIGNAL ;
    PORT
      LAYER M5 ;
        RECT  57.984 0 58.008 0.084 ;
    END
  END i_x1[262]
  PIN i_x1[263]
    DIRECTION INPUT ;
    USE SIGNAL ;
    PORT
      LAYER M3 ;
        RECT  58.068 0 58.086 0.038 ;
    END
  END i_x1[263]
  PIN i_x1[264]
    DIRECTION INPUT ;
    USE SIGNAL ;
    PORT
      LAYER M5 ;
        RECT  58.176 0 58.2 0.084 ;
    END
  END i_x1[264]
  PIN i_x1[265]
    DIRECTION INPUT ;
    USE SIGNAL ;
    PORT
      LAYER M3 ;
        RECT  58.284 0 58.302 0.038 ;
    END
  END i_x1[265]
  PIN i_x1[26]
    DIRECTION INPUT ;
    USE SIGNAL ;
    PORT
      LAYER M5 ;
        RECT  36.048 0 36.072 0.084 ;
    END
  END i_x1[26]
  PIN i_x1[27]
    DIRECTION INPUT ;
    USE SIGNAL ;
    PORT
      LAYER M3 ;
        RECT  36.144 0 36.162 0.038 ;
    END
  END i_x1[27]
  PIN i_x1[28]
    DIRECTION INPUT ;
    USE SIGNAL ;
    PORT
      LAYER M5 ;
        RECT  36.24 0 36.264 0.084 ;
    END
  END i_x1[28]
  PIN i_x1[29]
    DIRECTION INPUT ;
    USE SIGNAL ;
    PORT
      LAYER M3 ;
        RECT  36.324 0 36.342 0.038 ;
    END
  END i_x1[29]
  PIN i_x1[2]
    DIRECTION INPUT ;
    USE SIGNAL ;
    PORT
      LAYER M5 ;
        RECT  33.792 0 33.816 0.084 ;
    END
  END i_x1[2]
  PIN i_x1[30]
    DIRECTION INPUT ;
    USE SIGNAL ;
    PORT
      LAYER M5 ;
        RECT  36.432 0 36.456 0.084 ;
    END
  END i_x1[30]
  PIN i_x1[31]
    DIRECTION INPUT ;
    USE SIGNAL ;
    PORT
      LAYER M3 ;
        RECT  36.54 0 36.558 0.038 ;
    END
  END i_x1[31]
  PIN i_x1[32]
    DIRECTION INPUT ;
    USE SIGNAL ;
    PORT
      LAYER M5 ;
        RECT  36.576 0 36.6 0.084 ;
    END
  END i_x1[32]
  PIN i_x1[33]
    DIRECTION INPUT ;
    USE SIGNAL ;
    PORT
      LAYER M3 ;
        RECT  36.684 0 36.702 0.038 ;
    END
  END i_x1[33]
  PIN i_x1[34]
    DIRECTION INPUT ;
    USE SIGNAL ;
    PORT
      LAYER M5 ;
        RECT  36.768 0 36.792 0.084 ;
    END
  END i_x1[34]
  PIN i_x1[35]
    DIRECTION INPUT ;
    USE SIGNAL ;
    PORT
      LAYER M3 ;
        RECT  36.864 0 36.882 0.038 ;
    END
  END i_x1[35]
  PIN i_x1[36]
    DIRECTION INPUT ;
    USE SIGNAL ;
    PORT
      LAYER M5 ;
        RECT  36.96 0 36.984 0.084 ;
    END
  END i_x1[36]
  PIN i_x1[37]
    DIRECTION INPUT ;
    USE SIGNAL ;
    PORT
      LAYER M3 ;
        RECT  37.044 0 37.062 0.038 ;
    END
  END i_x1[37]
  PIN i_x1[38]
    DIRECTION INPUT ;
    USE SIGNAL ;
    PORT
      LAYER M5 ;
        RECT  37.152 0 37.176 0.084 ;
    END
  END i_x1[38]
  PIN i_x1[39]
    DIRECTION INPUT ;
    USE SIGNAL ;
    PORT
      LAYER M3 ;
        RECT  37.26 0 37.278 0.038 ;
    END
  END i_x1[39]
  PIN i_x1[3]
    DIRECTION INPUT ;
    USE SIGNAL ;
    PORT
      LAYER M3 ;
        RECT  33.876 0 33.894 0.038 ;
    END
  END i_x1[3]
  PIN i_x1[40]
    DIRECTION INPUT ;
    USE SIGNAL ;
    PORT
      LAYER M5 ;
        RECT  37.344 0 37.368 0.084 ;
    END
  END i_x1[40]
  PIN i_x1[41]
    DIRECTION INPUT ;
    USE SIGNAL ;
    PORT
      LAYER M3 ;
        RECT  37.44 0 37.458 0.038 ;
    END
  END i_x1[41]
  PIN i_x1[42]
    DIRECTION INPUT ;
    USE SIGNAL ;
    PORT
      LAYER M5 ;
        RECT  37.536 0 37.56 0.084 ;
    END
  END i_x1[42]
  PIN i_x1[43]
    DIRECTION INPUT ;
    USE SIGNAL ;
    PORT
      LAYER M3 ;
        RECT  37.62 0 37.638 0.038 ;
    END
  END i_x1[43]
  PIN i_x1[44]
    DIRECTION INPUT ;
    USE SIGNAL ;
    PORT
      LAYER M5 ;
        RECT  37.728 0 37.752 0.084 ;
    END
  END i_x1[44]
  PIN i_x1[45]
    DIRECTION INPUT ;
    USE SIGNAL ;
    PORT
      LAYER M3 ;
        RECT  37.836 0 37.854 0.038 ;
    END
  END i_x1[45]
  PIN i_x1[46]
    DIRECTION INPUT ;
    USE SIGNAL ;
    PORT
      LAYER M5 ;
        RECT  37.92 0 37.944 0.084 ;
    END
  END i_x1[46]
  PIN i_x1[47]
    DIRECTION INPUT ;
    USE SIGNAL ;
    PORT
      LAYER M3 ;
        RECT  37.98 0 37.998 0.038 ;
    END
  END i_x1[47]
  PIN i_x1[48]
    DIRECTION INPUT ;
    USE SIGNAL ;
    PORT
      LAYER M5 ;
        RECT  38.064 0 38.088 0.084 ;
    END
  END i_x1[48]
  PIN i_x1[49]
    DIRECTION INPUT ;
    USE SIGNAL ;
    PORT
      LAYER M3 ;
        RECT  38.16 0 38.178 0.038 ;
    END
  END i_x1[49]
  PIN i_x1[4]
    DIRECTION INPUT ;
    USE SIGNAL ;
    PORT
      LAYER M5 ;
        RECT  33.984 0 34.008 0.084 ;
    END
  END i_x1[4]
  PIN i_x1[50]
    DIRECTION INPUT ;
    USE SIGNAL ;
    PORT
      LAYER M5 ;
        RECT  38.256 0 38.28 0.084 ;
    END
  END i_x1[50]
  PIN i_x1[51]
    DIRECTION INPUT ;
    USE SIGNAL ;
    PORT
      LAYER M3 ;
        RECT  38.34 0 38.358 0.038 ;
    END
  END i_x1[51]
  PIN i_x1[52]
    DIRECTION INPUT ;
    USE SIGNAL ;
    PORT
      LAYER M5 ;
        RECT  38.448 0 38.472 0.084 ;
    END
  END i_x1[52]
  PIN i_x1[53]
    DIRECTION INPUT ;
    USE SIGNAL ;
    PORT
      LAYER M3 ;
        RECT  38.556 0 38.574 0.038 ;
    END
  END i_x1[53]
  PIN i_x1[54]
    DIRECTION INPUT ;
    USE SIGNAL ;
    PORT
      LAYER M5 ;
        RECT  38.64 0 38.664 0.084 ;
    END
  END i_x1[54]
  PIN i_x1[55]
    DIRECTION INPUT ;
    USE SIGNAL ;
    PORT
      LAYER M3 ;
        RECT  38.736 0 38.754 0.038 ;
    END
  END i_x1[55]
  PIN i_x1[56]
    DIRECTION INPUT ;
    USE SIGNAL ;
    PORT
      LAYER M5 ;
        RECT  38.832 0 38.856 0.084 ;
    END
  END i_x1[56]
  PIN i_x1[57]
    DIRECTION INPUT ;
    USE SIGNAL ;
    PORT
      LAYER M3 ;
        RECT  38.916 0 38.934 0.038 ;
    END
  END i_x1[57]
  PIN i_x1[58]
    DIRECTION INPUT ;
    USE SIGNAL ;
    PORT
      LAYER M5 ;
        RECT  39.024 0 39.048 0.084 ;
    END
  END i_x1[58]
  PIN i_x1[59]
    DIRECTION INPUT ;
    USE SIGNAL ;
    PORT
      LAYER M3 ;
        RECT  39.132 0 39.15 0.038 ;
    END
  END i_x1[59]
  PIN i_x1[5]
    DIRECTION INPUT ;
    USE SIGNAL ;
    PORT
      LAYER M3 ;
        RECT  34.092 0 34.11 0.038 ;
    END
  END i_x1[5]
  PIN i_x1[60]
    DIRECTION INPUT ;
    USE SIGNAL ;
    PORT
      LAYER M5 ;
        RECT  39.216 0 39.24 0.084 ;
    END
  END i_x1[60]
  PIN i_x1[61]
    DIRECTION INPUT ;
    USE SIGNAL ;
    PORT
      LAYER M3 ;
        RECT  39.312 0 39.33 0.038 ;
    END
  END i_x1[61]
  PIN i_x1[62]
    DIRECTION INPUT ;
    USE SIGNAL ;
    PORT
      LAYER M5 ;
        RECT  39.408 0 39.432 0.084 ;
    END
  END i_x1[62]
  PIN i_x1[63]
    DIRECTION INPUT ;
    USE SIGNAL ;
    PORT
      LAYER M3 ;
        RECT  39.456 0 39.474 0.038 ;
    END
  END i_x1[63]
  PIN i_x1[64]
    DIRECTION INPUT ;
    USE SIGNAL ;
    PORT
      LAYER M5 ;
        RECT  39.552 0 39.576 0.084 ;
    END
  END i_x1[64]
  PIN i_x1[65]
    DIRECTION INPUT ;
    USE SIGNAL ;
    PORT
      LAYER M3 ;
        RECT  39.636 0 39.654 0.038 ;
    END
  END i_x1[65]
  PIN i_x1[66]
    DIRECTION INPUT ;
    USE SIGNAL ;
    PORT
      LAYER M5 ;
        RECT  39.744 0 39.768 0.084 ;
    END
  END i_x1[66]
  PIN i_x1[67]
    DIRECTION INPUT ;
    USE SIGNAL ;
    PORT
      LAYER M3 ;
        RECT  39.852 0 39.87 0.038 ;
    END
  END i_x1[67]
  PIN i_x1[68]
    DIRECTION INPUT ;
    USE SIGNAL ;
    PORT
      LAYER M5 ;
        RECT  39.936 0 39.96 0.084 ;
    END
  END i_x1[68]
  PIN i_x1[69]
    DIRECTION INPUT ;
    USE SIGNAL ;
    PORT
      LAYER M3 ;
        RECT  40.032 0 40.05 0.038 ;
    END
  END i_x1[69]
  PIN i_x1[6]
    DIRECTION INPUT ;
    USE SIGNAL ;
    PORT
      LAYER M5 ;
        RECT  34.176 0 34.2 0.084 ;
    END
  END i_x1[6]
  PIN i_x1[70]
    DIRECTION INPUT ;
    USE SIGNAL ;
    PORT
      LAYER M5 ;
        RECT  40.128 0 40.152 0.084 ;
    END
  END i_x1[70]
  PIN i_x1[71]
    DIRECTION INPUT ;
    USE SIGNAL ;
    PORT
      LAYER M3 ;
        RECT  40.212 0 40.23 0.038 ;
    END
  END i_x1[71]
  PIN i_x1[72]
    DIRECTION INPUT ;
    USE SIGNAL ;
    PORT
      LAYER M5 ;
        RECT  40.32 0 40.344 0.084 ;
    END
  END i_x1[72]
  PIN i_x1[73]
    DIRECTION INPUT ;
    USE SIGNAL ;
    PORT
      LAYER M3 ;
        RECT  40.428 0 40.446 0.038 ;
    END
  END i_x1[73]
  PIN i_x1[74]
    DIRECTION INPUT ;
    USE SIGNAL ;
    PORT
      LAYER M5 ;
        RECT  40.512 0 40.536 0.084 ;
    END
  END i_x1[74]
  PIN i_x1[75]
    DIRECTION INPUT ;
    USE SIGNAL ;
    PORT
      LAYER M3 ;
        RECT  40.608 0 40.626 0.038 ;
    END
  END i_x1[75]
  PIN i_x1[76]
    DIRECTION INPUT ;
    USE SIGNAL ;
    PORT
      LAYER M5 ;
        RECT  40.704 0 40.728 0.084 ;
    END
  END i_x1[76]
  PIN i_x1[77]
    DIRECTION INPUT ;
    USE SIGNAL ;
    PORT
      LAYER M3 ;
        RECT  40.788 0 40.806 0.038 ;
    END
  END i_x1[77]
  PIN i_x1[78]
    DIRECTION INPUT ;
    USE SIGNAL ;
    PORT
      LAYER M5 ;
        RECT  40.896 0 40.92 0.084 ;
    END
  END i_x1[78]
  PIN i_x1[79]
    DIRECTION INPUT ;
    USE SIGNAL ;
    PORT
      LAYER M3 ;
        RECT  40.932 0 40.95 0.038 ;
    END
  END i_x1[79]
  PIN i_x1[7]
    DIRECTION INPUT ;
    USE SIGNAL ;
    PORT
      LAYER M3 ;
        RECT  34.272 0 34.29 0.038 ;
    END
  END i_x1[7]
  PIN i_x1[80]
    DIRECTION INPUT ;
    USE SIGNAL ;
    PORT
      LAYER M5 ;
        RECT  41.04 0 41.064 0.084 ;
    END
  END i_x1[80]
  PIN i_x1[81]
    DIRECTION INPUT ;
    USE SIGNAL ;
    PORT
      LAYER M3 ;
        RECT  41.148 0 41.166 0.038 ;
    END
  END i_x1[81]
  PIN i_x1[82]
    DIRECTION INPUT ;
    USE SIGNAL ;
    PORT
      LAYER M5 ;
        RECT  41.232 0 41.256 0.084 ;
    END
  END i_x1[82]
  PIN i_x1[83]
    DIRECTION INPUT ;
    USE SIGNAL ;
    PORT
      LAYER M3 ;
        RECT  41.328 0 41.346 0.038 ;
    END
  END i_x1[83]
  PIN i_x1[84]
    DIRECTION INPUT ;
    USE SIGNAL ;
    PORT
      LAYER M5 ;
        RECT  41.424 0 41.448 0.084 ;
    END
  END i_x1[84]
  PIN i_x1[85]
    DIRECTION INPUT ;
    USE SIGNAL ;
    PORT
      LAYER M3 ;
        RECT  41.508 0 41.526 0.038 ;
    END
  END i_x1[85]
  PIN i_x1[86]
    DIRECTION INPUT ;
    USE SIGNAL ;
    PORT
      LAYER M5 ;
        RECT  41.616 0 41.64 0.084 ;
    END
  END i_x1[86]
  PIN i_x1[87]
    DIRECTION INPUT ;
    USE SIGNAL ;
    PORT
      LAYER M3 ;
        RECT  41.724 0 41.742 0.038 ;
    END
  END i_x1[87]
  PIN i_x1[88]
    DIRECTION INPUT ;
    USE SIGNAL ;
    PORT
      LAYER M5 ;
        RECT  41.808 0 41.832 0.084 ;
    END
  END i_x1[88]
  PIN i_x1[89]
    DIRECTION INPUT ;
    USE SIGNAL ;
    PORT
      LAYER M3 ;
        RECT  41.904 0 41.922 0.038 ;
    END
  END i_x1[89]
  PIN i_x1[8]
    DIRECTION INPUT ;
    USE SIGNAL ;
    PORT
      LAYER M5 ;
        RECT  34.368 0 34.392 0.084 ;
    END
  END i_x1[8]
  PIN i_x1[90]
    DIRECTION INPUT ;
    USE SIGNAL ;
    PORT
      LAYER M5 ;
        RECT  42 0 42.024 0.084 ;
    END
  END i_x1[90]
  PIN i_x1[91]
    DIRECTION INPUT ;
    USE SIGNAL ;
    PORT
      LAYER M3 ;
        RECT  42.084 0 42.102 0.038 ;
    END
  END i_x1[91]
  PIN i_x1[92]
    DIRECTION INPUT ;
    USE SIGNAL ;
    PORT
      LAYER M5 ;
        RECT  42.192 0 42.216 0.084 ;
    END
  END i_x1[92]
  PIN i_x1[93]
    DIRECTION INPUT ;
    USE SIGNAL ;
    PORT
      LAYER M3 ;
        RECT  42.3 0 42.318 0.038 ;
    END
  END i_x1[93]
  PIN i_x1[94]
    DIRECTION INPUT ;
    USE SIGNAL ;
    PORT
      LAYER M5 ;
        RECT  42.384 0 42.408 0.084 ;
    END
  END i_x1[94]
  PIN i_x1[95]
    DIRECTION INPUT ;
    USE SIGNAL ;
    PORT
      LAYER M3 ;
        RECT  42.444 0 42.462 0.038 ;
    END
  END i_x1[95]
  PIN i_x1[96]
    DIRECTION INPUT ;
    USE SIGNAL ;
    PORT
      LAYER M5 ;
        RECT  42.528 0 42.552 0.084 ;
    END
  END i_x1[96]
  PIN i_x1[97]
    DIRECTION INPUT ;
    USE SIGNAL ;
    PORT
      LAYER M3 ;
        RECT  42.624 0 42.642 0.038 ;
    END
  END i_x1[97]
  PIN i_x1[98]
    DIRECTION INPUT ;
    USE SIGNAL ;
    PORT
      LAYER M5 ;
        RECT  42.72 0 42.744 0.084 ;
    END
  END i_x1[98]
  PIN i_x1[99]
    DIRECTION INPUT ;
    USE SIGNAL ;
    PORT
      LAYER M3 ;
        RECT  42.804 0 42.822 0.038 ;
    END
  END i_x1[99]
  PIN i_x1[9]
    DIRECTION INPUT ;
    USE SIGNAL ;
    PORT
      LAYER M3 ;
        RECT  34.452 0 34.47 0.038 ;
    END
  END i_x1[9]
  PIN o_cfg[0]
    DIRECTION OUTPUT ;
    USE SIGNAL ;
    PORT
      LAYER M5 ;
        RECT  2.208 25.836 2.232 25.92 ;
    END
  END o_cfg[0]
  PIN o_cfg[10]
    DIRECTION OUTPUT ;
    USE SIGNAL ;
    PORT
      LAYER M5 ;
        RECT  3.12 25.836 3.144 25.92 ;
    END
  END o_cfg[10]
  PIN o_cfg[11]
    DIRECTION OUTPUT ;
    USE SIGNAL ;
    PORT
      LAYER M3 ;
        RECT  3.204 25.882 3.222 25.92 ;
    END
  END o_cfg[11]
  PIN o_cfg[12]
    DIRECTION OUTPUT ;
    USE SIGNAL ;
    PORT
      LAYER M5 ;
        RECT  3.312 25.836 3.336 25.92 ;
    END
  END o_cfg[12]
  PIN o_cfg[13]
    DIRECTION OUTPUT ;
    USE SIGNAL ;
    PORT
      LAYER M3 ;
        RECT  3.42 25.882 3.438 25.92 ;
    END
  END o_cfg[13]
  PIN o_cfg[14]
    DIRECTION OUTPUT ;
    USE SIGNAL ;
    PORT
      LAYER M5 ;
        RECT  3.504 25.836 3.528 25.92 ;
    END
  END o_cfg[14]
  PIN o_cfg[15]
    DIRECTION OUTPUT ;
    USE SIGNAL ;
    PORT
      LAYER M3 ;
        RECT  3.6 25.882 3.618 25.92 ;
    END
  END o_cfg[15]
  PIN o_cfg[16]
    DIRECTION OUTPUT ;
    USE SIGNAL ;
    PORT
      LAYER M5 ;
        RECT  3.696 25.836 3.72 25.92 ;
    END
  END o_cfg[16]
  PIN o_cfg[17]
    DIRECTION OUTPUT ;
    USE SIGNAL ;
    PORT
      LAYER M3 ;
        RECT  3.78 25.882 3.798 25.92 ;
    END
  END o_cfg[17]
  PIN o_cfg[18]
    DIRECTION OUTPUT ;
    USE SIGNAL ;
    PORT
      LAYER M5 ;
        RECT  3.888 25.836 3.912 25.92 ;
    END
  END o_cfg[18]
  PIN o_cfg[19]
    DIRECTION OUTPUT ;
    USE SIGNAL ;
    PORT
      LAYER M3 ;
        RECT  3.996 25.882 4.014 25.92 ;
    END
  END o_cfg[19]
  PIN o_cfg[1]
    DIRECTION OUTPUT ;
    USE SIGNAL ;
    PORT
      LAYER M3 ;
        RECT  2.304 25.882 2.322 25.92 ;
    END
  END o_cfg[1]
  PIN o_cfg[20]
    DIRECTION OUTPUT ;
    USE SIGNAL ;
    PORT
      LAYER M5 ;
        RECT  4.032 25.836 4.056 25.92 ;
    END
  END o_cfg[20]
  PIN o_cfg[21]
    DIRECTION OUTPUT ;
    USE SIGNAL ;
    PORT
      LAYER M3 ;
        RECT  4.14 25.882 4.158 25.92 ;
    END
  END o_cfg[21]
  PIN o_cfg[22]
    DIRECTION OUTPUT ;
    USE SIGNAL ;
    PORT
      LAYER M5 ;
        RECT  4.224 25.836 4.248 25.92 ;
    END
  END o_cfg[22]
  PIN o_cfg[23]
    DIRECTION OUTPUT ;
    USE SIGNAL ;
    PORT
      LAYER M3 ;
        RECT  4.32 25.882 4.338 25.92 ;
    END
  END o_cfg[23]
  PIN o_cfg[24]
    DIRECTION OUTPUT ;
    USE SIGNAL ;
    PORT
      LAYER M5 ;
        RECT  4.416 25.836 4.44 25.92 ;
    END
  END o_cfg[24]
  PIN o_cfg[25]
    DIRECTION OUTPUT ;
    USE SIGNAL ;
    PORT
      LAYER M3 ;
        RECT  4.5 25.882 4.518 25.92 ;
    END
  END o_cfg[25]
  PIN o_cfg[26]
    DIRECTION OUTPUT ;
    USE SIGNAL ;
    PORT
      LAYER M5 ;
        RECT  4.608 25.836 4.632 25.92 ;
    END
  END o_cfg[26]
  PIN o_cfg[27]
    DIRECTION OUTPUT ;
    USE SIGNAL ;
    PORT
      LAYER M3 ;
        RECT  4.716 25.882 4.734 25.92 ;
    END
  END o_cfg[27]
  PIN o_cfg[28]
    DIRECTION OUTPUT ;
    USE SIGNAL ;
    PORT
      LAYER M5 ;
        RECT  4.8 25.836 4.824 25.92 ;
    END
  END o_cfg[28]
  PIN o_cfg[29]
    DIRECTION OUTPUT ;
    USE SIGNAL ;
    PORT
      LAYER M3 ;
        RECT  4.896 25.882 4.914 25.92 ;
    END
  END o_cfg[29]
  PIN o_cfg[2]
    DIRECTION OUTPUT ;
    USE SIGNAL ;
    PORT
      LAYER M5 ;
        RECT  2.4 25.836 2.424 25.92 ;
    END
  END o_cfg[2]
  PIN o_cfg[30]
    DIRECTION OUTPUT ;
    USE SIGNAL ;
    PORT
      LAYER M5 ;
        RECT  4.992 25.836 5.016 25.92 ;
    END
  END o_cfg[30]
  PIN o_cfg[31]
    DIRECTION OUTPUT ;
    USE SIGNAL ;
    PORT
      LAYER M3 ;
        RECT  5.076 25.882 5.094 25.92 ;
    END
  END o_cfg[31]
  PIN o_cfg[32]
    DIRECTION OUTPUT ;
    USE SIGNAL ;
    PORT
      LAYER M5 ;
        RECT  5.184 25.836 5.208 25.92 ;
    END
  END o_cfg[32]
  PIN o_cfg[33]
    DIRECTION OUTPUT ;
    USE SIGNAL ;
    PORT
      LAYER M3 ;
        RECT  5.292 25.882 5.31 25.92 ;
    END
  END o_cfg[33]
  PIN o_cfg[34]
    DIRECTION OUTPUT ;
    USE SIGNAL ;
    PORT
      LAYER M5 ;
        RECT  5.376 25.836 5.4 25.92 ;
    END
  END o_cfg[34]
  PIN o_cfg[35]
    DIRECTION OUTPUT ;
    USE SIGNAL ;
    PORT
      LAYER M3 ;
        RECT  5.472 25.882 5.49 25.92 ;
    END
  END o_cfg[35]
  PIN o_cfg[36]
    DIRECTION OUTPUT ;
    USE SIGNAL ;
    PORT
      LAYER M5 ;
        RECT  5.52 25.836 5.544 25.92 ;
    END
  END o_cfg[36]
  PIN o_cfg[37]
    DIRECTION OUTPUT ;
    USE SIGNAL ;
    PORT
      LAYER M3 ;
        RECT  5.616 25.882 5.634 25.92 ;
    END
  END o_cfg[37]
  PIN o_cfg[38]
    DIRECTION OUTPUT ;
    USE SIGNAL ;
    PORT
      LAYER M5 ;
        RECT  5.712 25.836 5.736 25.92 ;
    END
  END o_cfg[38]
  PIN o_cfg[39]
    DIRECTION OUTPUT ;
    USE SIGNAL ;
    PORT
      LAYER M3 ;
        RECT  5.796 25.882 5.814 25.92 ;
    END
  END o_cfg[39]
  PIN o_cfg[3]
    DIRECTION OUTPUT ;
    USE SIGNAL ;
    PORT
      LAYER M3 ;
        RECT  2.484 25.882 2.502 25.92 ;
    END
  END o_cfg[3]
  PIN o_cfg[40]
    DIRECTION OUTPUT ;
    USE SIGNAL ;
    PORT
      LAYER M5 ;
        RECT  5.904 25.836 5.928 25.92 ;
    END
  END o_cfg[40]
  PIN o_cfg[41]
    DIRECTION OUTPUT ;
    USE SIGNAL ;
    PORT
      LAYER M3 ;
        RECT  6.012 25.882 6.03 25.92 ;
    END
  END o_cfg[41]
  PIN o_cfg[42]
    DIRECTION OUTPUT ;
    USE SIGNAL ;
    PORT
      LAYER M5 ;
        RECT  6.096 25.836 6.12 25.92 ;
    END
  END o_cfg[42]
  PIN o_cfg[43]
    DIRECTION OUTPUT ;
    USE SIGNAL ;
    PORT
      LAYER M3 ;
        RECT  6.192 25.882 6.21 25.92 ;
    END
  END o_cfg[43]
  PIN o_cfg[44]
    DIRECTION OUTPUT ;
    USE SIGNAL ;
    PORT
      LAYER M5 ;
        RECT  6.288 25.836 6.312 25.92 ;
    END
  END o_cfg[44]
  PIN o_cfg[45]
    DIRECTION OUTPUT ;
    USE SIGNAL ;
    PORT
      LAYER M3 ;
        RECT  6.372 25.882 6.39 25.92 ;
    END
  END o_cfg[45]
  PIN o_cfg[46]
    DIRECTION OUTPUT ;
    USE SIGNAL ;
    PORT
      LAYER M5 ;
        RECT  6.48 25.836 6.504 25.92 ;
    END
  END o_cfg[46]
  PIN o_cfg[47]
    DIRECTION OUTPUT ;
    USE SIGNAL ;
    PORT
      LAYER M3 ;
        RECT  6.588 25.882 6.606 25.92 ;
    END
  END o_cfg[47]
  PIN o_cfg[48]
    DIRECTION OUTPUT ;
    USE SIGNAL ;
    PORT
      LAYER M5 ;
        RECT  6.672 25.836 6.696 25.92 ;
    END
  END o_cfg[48]
  PIN o_cfg[49]
    DIRECTION OUTPUT ;
    USE SIGNAL ;
    PORT
      LAYER M3 ;
        RECT  6.768 25.882 6.786 25.92 ;
    END
  END o_cfg[49]
  PIN o_cfg[4]
    DIRECTION OUTPUT ;
    USE SIGNAL ;
    PORT
      LAYER M5 ;
        RECT  2.544 25.836 2.568 25.92 ;
    END
  END o_cfg[4]
  PIN o_cfg[50]
    DIRECTION OUTPUT ;
    USE SIGNAL ;
    PORT
      LAYER M5 ;
        RECT  6.864 25.836 6.888 25.92 ;
    END
  END o_cfg[50]
  PIN o_cfg[51]
    DIRECTION OUTPUT ;
    USE SIGNAL ;
    PORT
      LAYER M3 ;
        RECT  6.948 25.882 6.966 25.92 ;
    END
  END o_cfg[51]
  PIN o_cfg[52]
    DIRECTION OUTPUT ;
    USE SIGNAL ;
    PORT
      LAYER M5 ;
        RECT  7.008 25.836 7.032 25.92 ;
    END
  END o_cfg[52]
  PIN o_cfg[53]
    DIRECTION OUTPUT ;
    USE SIGNAL ;
    PORT
      LAYER M3 ;
        RECT  7.092 25.882 7.11 25.92 ;
    END
  END o_cfg[53]
  PIN o_cfg[5]
    DIRECTION OUTPUT ;
    USE SIGNAL ;
    PORT
      LAYER M3 ;
        RECT  2.628 25.882 2.646 25.92 ;
    END
  END o_cfg[5]
  PIN o_cfg[6]
    DIRECTION OUTPUT ;
    USE SIGNAL ;
    PORT
      LAYER M5 ;
        RECT  2.736 25.836 2.76 25.92 ;
    END
  END o_cfg[6]
  PIN o_cfg[7]
    DIRECTION OUTPUT ;
    USE SIGNAL ;
    PORT
      LAYER M3 ;
        RECT  2.844 25.882 2.862 25.92 ;
    END
  END o_cfg[7]
  PIN o_cfg[8]
    DIRECTION OUTPUT ;
    USE SIGNAL ;
    PORT
      LAYER M5 ;
        RECT  2.928 25.836 2.952 25.92 ;
    END
  END o_cfg[8]
  PIN o_cfg[9]
    DIRECTION OUTPUT ;
    USE SIGNAL ;
    PORT
      LAYER M3 ;
        RECT  3.024 25.882 3.042 25.92 ;
    END
  END o_cfg[9]
  PIN o_go[0]
    DIRECTION OUTPUT ;
    USE SIGNAL ;
    PORT
      LAYER M5 ;
        RECT  7.2 25.836 7.224 25.92 ;
    END
  END o_go[0]
  PIN o_x0[0]
    DIRECTION OUTPUT ;
    USE SIGNAL ;
    PORT
      LAYER M3 ;
        RECT  10.476 25.882 10.494 25.92 ;
    END
  END o_x0[0]
  PIN o_x0[100]
    DIRECTION OUTPUT ;
    USE SIGNAL ;
    PORT
      LAYER M3 ;
        RECT  19.764 25.882 19.782 25.92 ;
    END
  END o_x0[100]
  PIN o_x0[101]
    DIRECTION OUTPUT ;
    USE SIGNAL ;
    PORT
      LAYER M5 ;
        RECT  19.872 25.836 19.896 25.92 ;
    END
  END o_x0[101]
  PIN o_x0[102]
    DIRECTION OUTPUT ;
    USE SIGNAL ;
    PORT
      LAYER M3 ;
        RECT  19.98 25.882 19.998 25.92 ;
    END
  END o_x0[102]
  PIN o_x0[103]
    DIRECTION OUTPUT ;
    USE SIGNAL ;
    PORT
      LAYER M5 ;
        RECT  20.064 25.836 20.088 25.92 ;
    END
  END o_x0[103]
  PIN o_x0[104]
    DIRECTION OUTPUT ;
    USE SIGNAL ;
    PORT
      LAYER M3 ;
        RECT  20.16 25.882 20.178 25.92 ;
    END
  END o_x0[104]
  PIN o_x0[105]
    DIRECTION OUTPUT ;
    USE SIGNAL ;
    PORT
      LAYER M5 ;
        RECT  20.256 25.836 20.28 25.92 ;
    END
  END o_x0[105]
  PIN o_x0[106]
    DIRECTION OUTPUT ;
    USE SIGNAL ;
    PORT
      LAYER M3 ;
        RECT  20.304 25.882 20.322 25.92 ;
    END
  END o_x0[106]
  PIN o_x0[107]
    DIRECTION OUTPUT ;
    USE SIGNAL ;
    PORT
      LAYER M5 ;
        RECT  20.4 25.836 20.424 25.92 ;
    END
  END o_x0[107]
  PIN o_x0[108]
    DIRECTION OUTPUT ;
    USE SIGNAL ;
    PORT
      LAYER M3 ;
        RECT  20.484 25.882 20.502 25.92 ;
    END
  END o_x0[108]
  PIN o_x0[109]
    DIRECTION OUTPUT ;
    USE SIGNAL ;
    PORT
      LAYER M5 ;
        RECT  20.592 25.836 20.616 25.92 ;
    END
  END o_x0[109]
  PIN o_x0[10]
    DIRECTION OUTPUT ;
    USE SIGNAL ;
    PORT
      LAYER M3 ;
        RECT  11.376 25.882 11.394 25.92 ;
    END
  END o_x0[10]
  PIN o_x0[110]
    DIRECTION OUTPUT ;
    USE SIGNAL ;
    PORT
      LAYER M3 ;
        RECT  20.7 25.882 20.718 25.92 ;
    END
  END o_x0[110]
  PIN o_x0[111]
    DIRECTION OUTPUT ;
    USE SIGNAL ;
    PORT
      LAYER M5 ;
        RECT  20.784 25.836 20.808 25.92 ;
    END
  END o_x0[111]
  PIN o_x0[112]
    DIRECTION OUTPUT ;
    USE SIGNAL ;
    PORT
      LAYER M3 ;
        RECT  20.88 25.882 20.898 25.92 ;
    END
  END o_x0[112]
  PIN o_x0[113]
    DIRECTION OUTPUT ;
    USE SIGNAL ;
    PORT
      LAYER M5 ;
        RECT  20.976 25.836 21 25.92 ;
    END
  END o_x0[113]
  PIN o_x0[114]
    DIRECTION OUTPUT ;
    USE SIGNAL ;
    PORT
      LAYER M3 ;
        RECT  21.06 25.882 21.078 25.92 ;
    END
  END o_x0[114]
  PIN o_x0[115]
    DIRECTION OUTPUT ;
    USE SIGNAL ;
    PORT
      LAYER M5 ;
        RECT  21.168 25.836 21.192 25.92 ;
    END
  END o_x0[115]
  PIN o_x0[116]
    DIRECTION OUTPUT ;
    USE SIGNAL ;
    PORT
      LAYER M3 ;
        RECT  21.276 25.882 21.294 25.92 ;
    END
  END o_x0[116]
  PIN o_x0[117]
    DIRECTION OUTPUT ;
    USE SIGNAL ;
    PORT
      LAYER M5 ;
        RECT  21.36 25.836 21.384 25.92 ;
    END
  END o_x0[117]
  PIN o_x0[118]
    DIRECTION OUTPUT ;
    USE SIGNAL ;
    PORT
      LAYER M3 ;
        RECT  21.456 25.882 21.474 25.92 ;
    END
  END o_x0[118]
  PIN o_x0[119]
    DIRECTION OUTPUT ;
    USE SIGNAL ;
    PORT
      LAYER M5 ;
        RECT  21.552 25.836 21.576 25.92 ;
    END
  END o_x0[119]
  PIN o_x0[11]
    DIRECTION OUTPUT ;
    USE SIGNAL ;
    PORT
      LAYER M5 ;
        RECT  11.472 25.836 11.496 25.92 ;
    END
  END o_x0[11]
  PIN o_x0[120]
    DIRECTION OUTPUT ;
    USE SIGNAL ;
    PORT
      LAYER M3 ;
        RECT  21.636 25.882 21.654 25.92 ;
    END
  END o_x0[120]
  PIN o_x0[121]
    DIRECTION OUTPUT ;
    USE SIGNAL ;
    PORT
      LAYER M5 ;
        RECT  21.744 25.836 21.768 25.92 ;
    END
  END o_x0[121]
  PIN o_x0[122]
    DIRECTION OUTPUT ;
    USE SIGNAL ;
    PORT
      LAYER M3 ;
        RECT  21.78 25.882 21.798 25.92 ;
    END
  END o_x0[122]
  PIN o_x0[123]
    DIRECTION OUTPUT ;
    USE SIGNAL ;
    PORT
      LAYER M5 ;
        RECT  21.888 25.836 21.912 25.92 ;
    END
  END o_x0[123]
  PIN o_x0[124]
    DIRECTION OUTPUT ;
    USE SIGNAL ;
    PORT
      LAYER M3 ;
        RECT  21.996 25.882 22.014 25.92 ;
    END
  END o_x0[124]
  PIN o_x0[125]
    DIRECTION OUTPUT ;
    USE SIGNAL ;
    PORT
      LAYER M5 ;
        RECT  22.08 25.836 22.104 25.92 ;
    END
  END o_x0[125]
  PIN o_x0[126]
    DIRECTION OUTPUT ;
    USE SIGNAL ;
    PORT
      LAYER M3 ;
        RECT  22.176 25.882 22.194 25.92 ;
    END
  END o_x0[126]
  PIN o_x0[127]
    DIRECTION OUTPUT ;
    USE SIGNAL ;
    PORT
      LAYER M5 ;
        RECT  22.272 25.836 22.296 25.92 ;
    END
  END o_x0[127]
  PIN o_x0[128]
    DIRECTION OUTPUT ;
    USE SIGNAL ;
    PORT
      LAYER M3 ;
        RECT  22.356 25.882 22.374 25.92 ;
    END
  END o_x0[128]
  PIN o_x0[129]
    DIRECTION OUTPUT ;
    USE SIGNAL ;
    PORT
      LAYER M5 ;
        RECT  22.464 25.836 22.488 25.92 ;
    END
  END o_x0[129]
  PIN o_x0[12]
    DIRECTION OUTPUT ;
    USE SIGNAL ;
    PORT
      LAYER M3 ;
        RECT  11.556 25.882 11.574 25.92 ;
    END
  END o_x0[12]
  PIN o_x0[130]
    DIRECTION OUTPUT ;
    USE SIGNAL ;
    PORT
      LAYER M3 ;
        RECT  22.572 25.882 22.59 25.92 ;
    END
  END o_x0[130]
  PIN o_x0[131]
    DIRECTION OUTPUT ;
    USE SIGNAL ;
    PORT
      LAYER M5 ;
        RECT  22.656 25.836 22.68 25.92 ;
    END
  END o_x0[131]
  PIN o_x0[132]
    DIRECTION OUTPUT ;
    USE SIGNAL ;
    PORT
      LAYER M3 ;
        RECT  22.752 25.882 22.77 25.92 ;
    END
  END o_x0[132]
  PIN o_x0[133]
    DIRECTION OUTPUT ;
    USE SIGNAL ;
    PORT
      LAYER M5 ;
        RECT  22.848 25.836 22.872 25.92 ;
    END
  END o_x0[133]
  PIN o_x0[134]
    DIRECTION OUTPUT ;
    USE SIGNAL ;
    PORT
      LAYER M3 ;
        RECT  22.932 25.882 22.95 25.92 ;
    END
  END o_x0[134]
  PIN o_x0[135]
    DIRECTION OUTPUT ;
    USE SIGNAL ;
    PORT
      LAYER M5 ;
        RECT  23.04 25.836 23.064 25.92 ;
    END
  END o_x0[135]
  PIN o_x0[136]
    DIRECTION OUTPUT ;
    USE SIGNAL ;
    PORT
      LAYER M3 ;
        RECT  23.148 25.882 23.166 25.92 ;
    END
  END o_x0[136]
  PIN o_x0[137]
    DIRECTION OUTPUT ;
    USE SIGNAL ;
    PORT
      LAYER M5 ;
        RECT  23.184 25.836 23.208 25.92 ;
    END
  END o_x0[137]
  PIN o_x0[138]
    DIRECTION OUTPUT ;
    USE SIGNAL ;
    PORT
      LAYER M3 ;
        RECT  23.292 25.882 23.31 25.92 ;
    END
  END o_x0[138]
  PIN o_x0[139]
    DIRECTION OUTPUT ;
    USE SIGNAL ;
    PORT
      LAYER M5 ;
        RECT  23.376 25.836 23.4 25.92 ;
    END
  END o_x0[139]
  PIN o_x0[13]
    DIRECTION OUTPUT ;
    USE SIGNAL ;
    PORT
      LAYER M5 ;
        RECT  11.664 25.836 11.688 25.92 ;
    END
  END o_x0[13]
  PIN o_x0[140]
    DIRECTION OUTPUT ;
    USE SIGNAL ;
    PORT
      LAYER M3 ;
        RECT  23.472 25.882 23.49 25.92 ;
    END
  END o_x0[140]
  PIN o_x0[141]
    DIRECTION OUTPUT ;
    USE SIGNAL ;
    PORT
      LAYER M5 ;
        RECT  23.568 25.836 23.592 25.92 ;
    END
  END o_x0[141]
  PIN o_x0[142]
    DIRECTION OUTPUT ;
    USE SIGNAL ;
    PORT
      LAYER M3 ;
        RECT  23.652 25.882 23.67 25.92 ;
    END
  END o_x0[142]
  PIN o_x0[143]
    DIRECTION OUTPUT ;
    USE SIGNAL ;
    PORT
      LAYER M5 ;
        RECT  23.76 25.836 23.784 25.92 ;
    END
  END o_x0[143]
  PIN o_x0[144]
    DIRECTION OUTPUT ;
    USE SIGNAL ;
    PORT
      LAYER M3 ;
        RECT  23.868 25.882 23.886 25.92 ;
    END
  END o_x0[144]
  PIN o_x0[145]
    DIRECTION OUTPUT ;
    USE SIGNAL ;
    PORT
      LAYER M5 ;
        RECT  23.952 25.836 23.976 25.92 ;
    END
  END o_x0[145]
  PIN o_x0[146]
    DIRECTION OUTPUT ;
    USE SIGNAL ;
    PORT
      LAYER M3 ;
        RECT  24.048 25.882 24.066 25.92 ;
    END
  END o_x0[146]
  PIN o_x0[147]
    DIRECTION OUTPUT ;
    USE SIGNAL ;
    PORT
      LAYER M5 ;
        RECT  24.144 25.836 24.168 25.92 ;
    END
  END o_x0[147]
  PIN o_x0[148]
    DIRECTION OUTPUT ;
    USE SIGNAL ;
    PORT
      LAYER M3 ;
        RECT  24.228 25.882 24.246 25.92 ;
    END
  END o_x0[148]
  PIN o_x0[149]
    DIRECTION OUTPUT ;
    USE SIGNAL ;
    PORT
      LAYER M5 ;
        RECT  24.336 25.836 24.36 25.92 ;
    END
  END o_x0[149]
  PIN o_x0[14]
    DIRECTION OUTPUT ;
    USE SIGNAL ;
    PORT
      LAYER M3 ;
        RECT  11.772 25.882 11.79 25.92 ;
    END
  END o_x0[14]
  PIN o_x0[150]
    DIRECTION OUTPUT ;
    USE SIGNAL ;
    PORT
      LAYER M3 ;
        RECT  24.444 25.882 24.462 25.92 ;
    END
  END o_x0[150]
  PIN o_x0[151]
    DIRECTION OUTPUT ;
    USE SIGNAL ;
    PORT
      LAYER M5 ;
        RECT  24.528 25.836 24.552 25.92 ;
    END
  END o_x0[151]
  PIN o_x0[152]
    DIRECTION OUTPUT ;
    USE SIGNAL ;
    PORT
      LAYER M3 ;
        RECT  24.624 25.882 24.642 25.92 ;
    END
  END o_x0[152]
  PIN o_x0[153]
    DIRECTION OUTPUT ;
    USE SIGNAL ;
    PORT
      LAYER M5 ;
        RECT  24.672 25.836 24.696 25.92 ;
    END
  END o_x0[153]
  PIN o_x0[154]
    DIRECTION OUTPUT ;
    USE SIGNAL ;
    PORT
      LAYER M3 ;
        RECT  24.768 25.882 24.786 25.92 ;
    END
  END o_x0[154]
  PIN o_x0[155]
    DIRECTION OUTPUT ;
    USE SIGNAL ;
    PORT
      LAYER M5 ;
        RECT  24.864 25.836 24.888 25.92 ;
    END
  END o_x0[155]
  PIN o_x0[156]
    DIRECTION OUTPUT ;
    USE SIGNAL ;
    PORT
      LAYER M3 ;
        RECT  24.948 25.882 24.966 25.92 ;
    END
  END o_x0[156]
  PIN o_x0[157]
    DIRECTION OUTPUT ;
    USE SIGNAL ;
    PORT
      LAYER M5 ;
        RECT  25.056 25.836 25.08 25.92 ;
    END
  END o_x0[157]
  PIN o_x0[158]
    DIRECTION OUTPUT ;
    USE SIGNAL ;
    PORT
      LAYER M3 ;
        RECT  25.164 25.882 25.182 25.92 ;
    END
  END o_x0[158]
  PIN o_x0[159]
    DIRECTION OUTPUT ;
    USE SIGNAL ;
    PORT
      LAYER M5 ;
        RECT  25.248 25.836 25.272 25.92 ;
    END
  END o_x0[159]
  PIN o_x0[15]
    DIRECTION OUTPUT ;
    USE SIGNAL ;
    PORT
      LAYER M5 ;
        RECT  11.856 25.836 11.88 25.92 ;
    END
  END o_x0[15]
  PIN o_x0[160]
    DIRECTION OUTPUT ;
    USE SIGNAL ;
    PORT
      LAYER M3 ;
        RECT  25.344 25.882 25.362 25.92 ;
    END
  END o_x0[160]
  PIN o_x0[161]
    DIRECTION OUTPUT ;
    USE SIGNAL ;
    PORT
      LAYER M5 ;
        RECT  25.44 25.836 25.464 25.92 ;
    END
  END o_x0[161]
  PIN o_x0[162]
    DIRECTION OUTPUT ;
    USE SIGNAL ;
    PORT
      LAYER M3 ;
        RECT  25.524 25.882 25.542 25.92 ;
    END
  END o_x0[162]
  PIN o_x0[163]
    DIRECTION OUTPUT ;
    USE SIGNAL ;
    PORT
      LAYER M5 ;
        RECT  25.632 25.836 25.656 25.92 ;
    END
  END o_x0[163]
  PIN o_x0[164]
    DIRECTION OUTPUT ;
    USE SIGNAL ;
    PORT
      LAYER M3 ;
        RECT  25.74 25.882 25.758 25.92 ;
    END
  END o_x0[164]
  PIN o_x0[165]
    DIRECTION OUTPUT ;
    USE SIGNAL ;
    PORT
      LAYER M5 ;
        RECT  25.824 25.836 25.848 25.92 ;
    END
  END o_x0[165]
  PIN o_x0[166]
    DIRECTION OUTPUT ;
    USE SIGNAL ;
    PORT
      LAYER M3 ;
        RECT  25.92 25.882 25.938 25.92 ;
    END
  END o_x0[166]
  PIN o_x0[167]
    DIRECTION OUTPUT ;
    USE SIGNAL ;
    PORT
      LAYER M5 ;
        RECT  26.016 25.836 26.04 25.92 ;
    END
  END o_x0[167]
  PIN o_x0[168]
    DIRECTION OUTPUT ;
    USE SIGNAL ;
    PORT
      LAYER M3 ;
        RECT  26.1 25.882 26.118 25.92 ;
    END
  END o_x0[168]
  PIN o_x0[169]
    DIRECTION OUTPUT ;
    USE SIGNAL ;
    PORT
      LAYER M5 ;
        RECT  26.16 25.836 26.184 25.92 ;
    END
  END o_x0[169]
  PIN o_x0[16]
    DIRECTION OUTPUT ;
    USE SIGNAL ;
    PORT
      LAYER M3 ;
        RECT  11.952 25.882 11.97 25.92 ;
    END
  END o_x0[16]
  PIN o_x0[170]
    DIRECTION OUTPUT ;
    USE SIGNAL ;
    PORT
      LAYER M3 ;
        RECT  26.244 25.882 26.262 25.92 ;
    END
  END o_x0[170]
  PIN o_x0[171]
    DIRECTION OUTPUT ;
    USE SIGNAL ;
    PORT
      LAYER M5 ;
        RECT  26.352 25.836 26.376 25.92 ;
    END
  END o_x0[171]
  PIN o_x0[172]
    DIRECTION OUTPUT ;
    USE SIGNAL ;
    PORT
      LAYER M3 ;
        RECT  26.46 25.882 26.478 25.92 ;
    END
  END o_x0[172]
  PIN o_x0[173]
    DIRECTION OUTPUT ;
    USE SIGNAL ;
    PORT
      LAYER M5 ;
        RECT  26.544 25.836 26.568 25.92 ;
    END
  END o_x0[173]
  PIN o_x0[174]
    DIRECTION OUTPUT ;
    USE SIGNAL ;
    PORT
      LAYER M3 ;
        RECT  26.64 25.882 26.658 25.92 ;
    END
  END o_x0[174]
  PIN o_x0[175]
    DIRECTION OUTPUT ;
    USE SIGNAL ;
    PORT
      LAYER M5 ;
        RECT  26.736 25.836 26.76 25.92 ;
    END
  END o_x0[175]
  PIN o_x0[176]
    DIRECTION OUTPUT ;
    USE SIGNAL ;
    PORT
      LAYER M3 ;
        RECT  26.82 25.882 26.838 25.92 ;
    END
  END o_x0[176]
  PIN o_x0[177]
    DIRECTION OUTPUT ;
    USE SIGNAL ;
    PORT
      LAYER M5 ;
        RECT  26.928 25.836 26.952 25.92 ;
    END
  END o_x0[177]
  PIN o_x0[178]
    DIRECTION OUTPUT ;
    USE SIGNAL ;
    PORT
      LAYER M3 ;
        RECT  27.036 25.882 27.054 25.92 ;
    END
  END o_x0[178]
  PIN o_x0[179]
    DIRECTION OUTPUT ;
    USE SIGNAL ;
    PORT
      LAYER M5 ;
        RECT  27.12 25.836 27.144 25.92 ;
    END
  END o_x0[179]
  PIN o_x0[17]
    DIRECTION OUTPUT ;
    USE SIGNAL ;
    PORT
      LAYER M5 ;
        RECT  12.048 25.836 12.072 25.92 ;
    END
  END o_x0[17]
  PIN o_x0[180]
    DIRECTION OUTPUT ;
    USE SIGNAL ;
    PORT
      LAYER M3 ;
        RECT  27.216 25.882 27.234 25.92 ;
    END
  END o_x0[180]
  PIN o_x0[181]
    DIRECTION OUTPUT ;
    USE SIGNAL ;
    PORT
      LAYER M5 ;
        RECT  27.312 25.836 27.336 25.92 ;
    END
  END o_x0[181]
  PIN o_x0[182]
    DIRECTION OUTPUT ;
    USE SIGNAL ;
    PORT
      LAYER M3 ;
        RECT  27.396 25.882 27.414 25.92 ;
    END
  END o_x0[182]
  PIN o_x0[183]
    DIRECTION OUTPUT ;
    USE SIGNAL ;
    PORT
      LAYER M5 ;
        RECT  27.504 25.836 27.528 25.92 ;
    END
  END o_x0[183]
  PIN o_x0[184]
    DIRECTION OUTPUT ;
    USE SIGNAL ;
    PORT
      LAYER M3 ;
        RECT  27.612 25.882 27.63 25.92 ;
    END
  END o_x0[184]
  PIN o_x0[185]
    DIRECTION OUTPUT ;
    USE SIGNAL ;
    PORT
      LAYER M5 ;
        RECT  27.648 25.836 27.672 25.92 ;
    END
  END o_x0[185]
  PIN o_x0[186]
    DIRECTION OUTPUT ;
    USE SIGNAL ;
    PORT
      LAYER M3 ;
        RECT  27.756 25.882 27.774 25.92 ;
    END
  END o_x0[186]
  PIN o_x0[187]
    DIRECTION OUTPUT ;
    USE SIGNAL ;
    PORT
      LAYER M5 ;
        RECT  27.84 25.836 27.864 25.92 ;
    END
  END o_x0[187]
  PIN o_x0[188]
    DIRECTION OUTPUT ;
    USE SIGNAL ;
    PORT
      LAYER M3 ;
        RECT  27.936 25.882 27.954 25.92 ;
    END
  END o_x0[188]
  PIN o_x0[189]
    DIRECTION OUTPUT ;
    USE SIGNAL ;
    PORT
      LAYER M5 ;
        RECT  28.032 25.836 28.056 25.92 ;
    END
  END o_x0[189]
  PIN o_x0[18]
    DIRECTION OUTPUT ;
    USE SIGNAL ;
    PORT
      LAYER M3 ;
        RECT  12.132 25.882 12.15 25.92 ;
    END
  END o_x0[18]
  PIN o_x0[190]
    DIRECTION OUTPUT ;
    USE SIGNAL ;
    PORT
      LAYER M3 ;
        RECT  28.116 25.882 28.134 25.92 ;
    END
  END o_x0[190]
  PIN o_x0[191]
    DIRECTION OUTPUT ;
    USE SIGNAL ;
    PORT
      LAYER M5 ;
        RECT  28.224 25.836 28.248 25.92 ;
    END
  END o_x0[191]
  PIN o_x0[192]
    DIRECTION OUTPUT ;
    USE SIGNAL ;
    PORT
      LAYER M3 ;
        RECT  28.332 25.882 28.35 25.92 ;
    END
  END o_x0[192]
  PIN o_x0[193]
    DIRECTION OUTPUT ;
    USE SIGNAL ;
    PORT
      LAYER M5 ;
        RECT  28.416 25.836 28.44 25.92 ;
    END
  END o_x0[193]
  PIN o_x0[194]
    DIRECTION OUTPUT ;
    USE SIGNAL ;
    PORT
      LAYER M3 ;
        RECT  28.512 25.882 28.53 25.92 ;
    END
  END o_x0[194]
  PIN o_x0[195]
    DIRECTION OUTPUT ;
    USE SIGNAL ;
    PORT
      LAYER M5 ;
        RECT  28.608 25.836 28.632 25.92 ;
    END
  END o_x0[195]
  PIN o_x0[196]
    DIRECTION OUTPUT ;
    USE SIGNAL ;
    PORT
      LAYER M3 ;
        RECT  28.692 25.882 28.71 25.92 ;
    END
  END o_x0[196]
  PIN o_x0[197]
    DIRECTION OUTPUT ;
    USE SIGNAL ;
    PORT
      LAYER M5 ;
        RECT  28.8 25.836 28.824 25.92 ;
    END
  END o_x0[197]
  PIN o_x0[198]
    DIRECTION OUTPUT ;
    USE SIGNAL ;
    PORT
      LAYER M3 ;
        RECT  28.908 25.882 28.926 25.92 ;
    END
  END o_x0[198]
  PIN o_x0[199]
    DIRECTION OUTPUT ;
    USE SIGNAL ;
    PORT
      LAYER M5 ;
        RECT  28.992 25.836 29.016 25.92 ;
    END
  END o_x0[199]
  PIN o_x0[19]
    DIRECTION OUTPUT ;
    USE SIGNAL ;
    PORT
      LAYER M5 ;
        RECT  12.24 25.836 12.264 25.92 ;
    END
  END o_x0[19]
  PIN o_x0[1]
    DIRECTION OUTPUT ;
    USE SIGNAL ;
    PORT
      LAYER M5 ;
        RECT  10.56 25.836 10.584 25.92 ;
    END
  END o_x0[1]
  PIN o_x0[200]
    DIRECTION OUTPUT ;
    USE SIGNAL ;
    PORT
      LAYER M3 ;
        RECT  29.088 25.882 29.106 25.92 ;
    END
  END o_x0[200]
  PIN o_x0[201]
    DIRECTION OUTPUT ;
    USE SIGNAL ;
    PORT
      LAYER M5 ;
        RECT  29.136 25.836 29.16 25.92 ;
    END
  END o_x0[201]
  PIN o_x0[202]
    DIRECTION OUTPUT ;
    USE SIGNAL ;
    PORT
      LAYER M3 ;
        RECT  29.232 25.882 29.25 25.92 ;
    END
  END o_x0[202]
  PIN o_x0[203]
    DIRECTION OUTPUT ;
    USE SIGNAL ;
    PORT
      LAYER M5 ;
        RECT  29.328 25.836 29.352 25.92 ;
    END
  END o_x0[203]
  PIN o_x0[204]
    DIRECTION OUTPUT ;
    USE SIGNAL ;
    PORT
      LAYER M3 ;
        RECT  29.412 25.882 29.43 25.92 ;
    END
  END o_x0[204]
  PIN o_x0[205]
    DIRECTION OUTPUT ;
    USE SIGNAL ;
    PORT
      LAYER M5 ;
        RECT  29.52 25.836 29.544 25.92 ;
    END
  END o_x0[205]
  PIN o_x0[206]
    DIRECTION OUTPUT ;
    USE SIGNAL ;
    PORT
      LAYER M3 ;
        RECT  29.628 25.882 29.646 25.92 ;
    END
  END o_x0[206]
  PIN o_x0[207]
    DIRECTION OUTPUT ;
    USE SIGNAL ;
    PORT
      LAYER M5 ;
        RECT  29.712 25.836 29.736 25.92 ;
    END
  END o_x0[207]
  PIN o_x0[208]
    DIRECTION OUTPUT ;
    USE SIGNAL ;
    PORT
      LAYER M3 ;
        RECT  29.808 25.882 29.826 25.92 ;
    END
  END o_x0[208]
  PIN o_x0[209]
    DIRECTION OUTPUT ;
    USE SIGNAL ;
    PORT
      LAYER M5 ;
        RECT  29.904 25.836 29.928 25.92 ;
    END
  END o_x0[209]
  PIN o_x0[20]
    DIRECTION OUTPUT ;
    USE SIGNAL ;
    PORT
      LAYER M3 ;
        RECT  12.348 25.882 12.366 25.92 ;
    END
  END o_x0[20]
  PIN o_x0[210]
    DIRECTION OUTPUT ;
    USE SIGNAL ;
    PORT
      LAYER M3 ;
        RECT  29.988 25.882 30.006 25.92 ;
    END
  END o_x0[210]
  PIN o_x0[211]
    DIRECTION OUTPUT ;
    USE SIGNAL ;
    PORT
      LAYER M5 ;
        RECT  30.096 25.836 30.12 25.92 ;
    END
  END o_x0[211]
  PIN o_x0[212]
    DIRECTION OUTPUT ;
    USE SIGNAL ;
    PORT
      LAYER M3 ;
        RECT  30.204 25.882 30.222 25.92 ;
    END
  END o_x0[212]
  PIN o_x0[213]
    DIRECTION OUTPUT ;
    USE SIGNAL ;
    PORT
      LAYER M5 ;
        RECT  30.288 25.836 30.312 25.92 ;
    END
  END o_x0[213]
  PIN o_x0[214]
    DIRECTION OUTPUT ;
    USE SIGNAL ;
    PORT
      LAYER M3 ;
        RECT  30.384 25.882 30.402 25.92 ;
    END
  END o_x0[214]
  PIN o_x0[215]
    DIRECTION OUTPUT ;
    USE SIGNAL ;
    PORT
      LAYER M5 ;
        RECT  30.48 25.836 30.504 25.92 ;
    END
  END o_x0[215]
  PIN o_x0[216]
    DIRECTION OUTPUT ;
    USE SIGNAL ;
    PORT
      LAYER M3 ;
        RECT  30.564 25.882 30.582 25.92 ;
    END
  END o_x0[216]
  PIN o_x0[217]
    DIRECTION OUTPUT ;
    USE SIGNAL ;
    PORT
      LAYER M5 ;
        RECT  30.624 25.836 30.648 25.92 ;
    END
  END o_x0[217]
  PIN o_x0[218]
    DIRECTION OUTPUT ;
    USE SIGNAL ;
    PORT
      LAYER M3 ;
        RECT  30.708 25.882 30.726 25.92 ;
    END
  END o_x0[218]
  PIN o_x0[219]
    DIRECTION OUTPUT ;
    USE SIGNAL ;
    PORT
      LAYER M5 ;
        RECT  30.816 25.836 30.84 25.92 ;
    END
  END o_x0[219]
  PIN o_x0[21]
    DIRECTION OUTPUT ;
    USE SIGNAL ;
    PORT
      LAYER M5 ;
        RECT  12.432 25.836 12.456 25.92 ;
    END
  END o_x0[21]
  PIN o_x0[220]
    DIRECTION OUTPUT ;
    USE SIGNAL ;
    PORT
      LAYER M3 ;
        RECT  30.924 25.882 30.942 25.92 ;
    END
  END o_x0[220]
  PIN o_x0[221]
    DIRECTION OUTPUT ;
    USE SIGNAL ;
    PORT
      LAYER M5 ;
        RECT  31.008 25.836 31.032 25.92 ;
    END
  END o_x0[221]
  PIN o_x0[222]
    DIRECTION OUTPUT ;
    USE SIGNAL ;
    PORT
      LAYER M3 ;
        RECT  31.104 25.882 31.122 25.92 ;
    END
  END o_x0[222]
  PIN o_x0[223]
    DIRECTION OUTPUT ;
    USE SIGNAL ;
    PORT
      LAYER M5 ;
        RECT  31.2 25.836 31.224 25.92 ;
    END
  END o_x0[223]
  PIN o_x0[224]
    DIRECTION OUTPUT ;
    USE SIGNAL ;
    PORT
      LAYER M3 ;
        RECT  31.284 25.882 31.302 25.92 ;
    END
  END o_x0[224]
  PIN o_x0[225]
    DIRECTION OUTPUT ;
    USE SIGNAL ;
    PORT
      LAYER M5 ;
        RECT  31.392 25.836 31.416 25.92 ;
    END
  END o_x0[225]
  PIN o_x0[226]
    DIRECTION OUTPUT ;
    USE SIGNAL ;
    PORT
      LAYER M3 ;
        RECT  31.5 25.882 31.518 25.92 ;
    END
  END o_x0[226]
  PIN o_x0[227]
    DIRECTION OUTPUT ;
    USE SIGNAL ;
    PORT
      LAYER M5 ;
        RECT  31.584 25.836 31.608 25.92 ;
    END
  END o_x0[227]
  PIN o_x0[228]
    DIRECTION OUTPUT ;
    USE SIGNAL ;
    PORT
      LAYER M3 ;
        RECT  31.68 25.882 31.698 25.92 ;
    END
  END o_x0[228]
  PIN o_x0[229]
    DIRECTION OUTPUT ;
    USE SIGNAL ;
    PORT
      LAYER M5 ;
        RECT  31.776 25.836 31.8 25.92 ;
    END
  END o_x0[229]
  PIN o_x0[22]
    DIRECTION OUTPUT ;
    USE SIGNAL ;
    PORT
      LAYER M3 ;
        RECT  12.528 25.882 12.546 25.92 ;
    END
  END o_x0[22]
  PIN o_x0[230]
    DIRECTION OUTPUT ;
    USE SIGNAL ;
    PORT
      LAYER M3 ;
        RECT  31.86 25.882 31.878 25.92 ;
    END
  END o_x0[230]
  PIN o_x0[231]
    DIRECTION OUTPUT ;
    USE SIGNAL ;
    PORT
      LAYER M5 ;
        RECT  31.968 25.836 31.992 25.92 ;
    END
  END o_x0[231]
  PIN o_x0[232]
    DIRECTION OUTPUT ;
    USE SIGNAL ;
    PORT
      LAYER M3 ;
        RECT  32.076 25.882 32.094 25.92 ;
    END
  END o_x0[232]
  PIN o_x0[233]
    DIRECTION OUTPUT ;
    USE SIGNAL ;
    PORT
      LAYER M5 ;
        RECT  32.112 25.836 32.136 25.92 ;
    END
  END o_x0[233]
  PIN o_x0[234]
    DIRECTION OUTPUT ;
    USE SIGNAL ;
    PORT
      LAYER M3 ;
        RECT  32.22 25.882 32.238 25.92 ;
    END
  END o_x0[234]
  PIN o_x0[235]
    DIRECTION OUTPUT ;
    USE SIGNAL ;
    PORT
      LAYER M5 ;
        RECT  32.304 25.836 32.328 25.92 ;
    END
  END o_x0[235]
  PIN o_x0[236]
    DIRECTION OUTPUT ;
    USE SIGNAL ;
    PORT
      LAYER M3 ;
        RECT  32.4 25.882 32.418 25.92 ;
    END
  END o_x0[236]
  PIN o_x0[237]
    DIRECTION OUTPUT ;
    USE SIGNAL ;
    PORT
      LAYER M5 ;
        RECT  32.496 25.836 32.52 25.92 ;
    END
  END o_x0[237]
  PIN o_x0[238]
    DIRECTION OUTPUT ;
    USE SIGNAL ;
    PORT
      LAYER M3 ;
        RECT  32.58 25.882 32.598 25.92 ;
    END
  END o_x0[238]
  PIN o_x0[239]
    DIRECTION OUTPUT ;
    USE SIGNAL ;
    PORT
      LAYER M5 ;
        RECT  32.688 25.836 32.712 25.92 ;
    END
  END o_x0[239]
  PIN o_x0[23]
    DIRECTION OUTPUT ;
    USE SIGNAL ;
    PORT
      LAYER M5 ;
        RECT  12.624 25.836 12.648 25.92 ;
    END
  END o_x0[23]
  PIN o_x0[240]
    DIRECTION OUTPUT ;
    USE SIGNAL ;
    PORT
      LAYER M3 ;
        RECT  32.796 25.882 32.814 25.92 ;
    END
  END o_x0[240]
  PIN o_x0[241]
    DIRECTION OUTPUT ;
    USE SIGNAL ;
    PORT
      LAYER M5 ;
        RECT  32.88 25.836 32.904 25.92 ;
    END
  END o_x0[241]
  PIN o_x0[242]
    DIRECTION OUTPUT ;
    USE SIGNAL ;
    PORT
      LAYER M3 ;
        RECT  32.976 25.882 32.994 25.92 ;
    END
  END o_x0[242]
  PIN o_x0[243]
    DIRECTION OUTPUT ;
    USE SIGNAL ;
    PORT
      LAYER M5 ;
        RECT  33.072 25.836 33.096 25.92 ;
    END
  END o_x0[243]
  PIN o_x0[244]
    DIRECTION OUTPUT ;
    USE SIGNAL ;
    PORT
      LAYER M3 ;
        RECT  33.156 25.882 33.174 25.92 ;
    END
  END o_x0[244]
  PIN o_x0[245]
    DIRECTION OUTPUT ;
    USE SIGNAL ;
    PORT
      LAYER M5 ;
        RECT  33.264 25.836 33.288 25.92 ;
    END
  END o_x0[245]
  PIN o_x0[246]
    DIRECTION OUTPUT ;
    USE SIGNAL ;
    PORT
      LAYER M3 ;
        RECT  33.372 25.882 33.39 25.92 ;
    END
  END o_x0[246]
  PIN o_x0[247]
    DIRECTION OUTPUT ;
    USE SIGNAL ;
    PORT
      LAYER M5 ;
        RECT  33.456 25.836 33.48 25.92 ;
    END
  END o_x0[247]
  PIN o_x0[248]
    DIRECTION OUTPUT ;
    USE SIGNAL ;
    PORT
      LAYER M3 ;
        RECT  33.552 25.882 33.57 25.92 ;
    END
  END o_x0[248]
  PIN o_x0[249]
    DIRECTION OUTPUT ;
    USE SIGNAL ;
    PORT
      LAYER M5 ;
        RECT  33.6 25.836 33.624 25.92 ;
    END
  END o_x0[249]
  PIN o_x0[24]
    DIRECTION OUTPUT ;
    USE SIGNAL ;
    PORT
      LAYER M3 ;
        RECT  12.708 25.882 12.726 25.92 ;
    END
  END o_x0[24]
  PIN o_x0[250]
    DIRECTION OUTPUT ;
    USE SIGNAL ;
    PORT
      LAYER M3 ;
        RECT  33.696 25.882 33.714 25.92 ;
    END
  END o_x0[250]
  PIN o_x0[251]
    DIRECTION OUTPUT ;
    USE SIGNAL ;
    PORT
      LAYER M5 ;
        RECT  33.792 25.836 33.816 25.92 ;
    END
  END o_x0[251]
  PIN o_x0[252]
    DIRECTION OUTPUT ;
    USE SIGNAL ;
    PORT
      LAYER M3 ;
        RECT  33.876 25.882 33.894 25.92 ;
    END
  END o_x0[252]
  PIN o_x0[253]
    DIRECTION OUTPUT ;
    USE SIGNAL ;
    PORT
      LAYER M5 ;
        RECT  33.984 25.836 34.008 25.92 ;
    END
  END o_x0[253]
  PIN o_x0[254]
    DIRECTION OUTPUT ;
    USE SIGNAL ;
    PORT
      LAYER M3 ;
        RECT  34.092 25.882 34.11 25.92 ;
    END
  END o_x0[254]
  PIN o_x0[255]
    DIRECTION OUTPUT ;
    USE SIGNAL ;
    PORT
      LAYER M5 ;
        RECT  34.176 25.836 34.2 25.92 ;
    END
  END o_x0[255]
  PIN o_x0[256]
    DIRECTION OUTPUT ;
    USE SIGNAL ;
    PORT
      LAYER M5 ;
        RECT  7.584 25.836 7.608 25.92 ;
    END
  END o_x0[256]
  PIN o_x0[257]
    DIRECTION OUTPUT ;
    USE SIGNAL ;
    PORT
      LAYER M3 ;
        RECT  7.668 25.882 7.686 25.92 ;
    END
  END o_x0[257]
  PIN o_x0[258]
    DIRECTION OUTPUT ;
    USE SIGNAL ;
    PORT
      LAYER M5 ;
        RECT  7.776 25.836 7.8 25.92 ;
    END
  END o_x0[258]
  PIN o_x0[259]
    DIRECTION OUTPUT ;
    USE SIGNAL ;
    PORT
      LAYER M3 ;
        RECT  7.884 25.882 7.902 25.92 ;
    END
  END o_x0[259]
  PIN o_x0[25]
    DIRECTION OUTPUT ;
    USE SIGNAL ;
    PORT
      LAYER M5 ;
        RECT  12.816 25.836 12.84 25.92 ;
    END
  END o_x0[25]
  PIN o_x0[260]
    DIRECTION OUTPUT ;
    USE SIGNAL ;
    PORT
      LAYER M5 ;
        RECT  7.968 25.836 7.992 25.92 ;
    END
  END o_x0[260]
  PIN o_x0[261]
    DIRECTION OUTPUT ;
    USE SIGNAL ;
    PORT
      LAYER M3 ;
        RECT  8.064 25.882 8.082 25.92 ;
    END
  END o_x0[261]
  PIN o_x0[262]
    DIRECTION OUTPUT ;
    USE SIGNAL ;
    PORT
      LAYER M5 ;
        RECT  8.16 25.836 8.184 25.92 ;
    END
  END o_x0[262]
  PIN o_x0[263]
    DIRECTION OUTPUT ;
    USE SIGNAL ;
    PORT
      LAYER M3 ;
        RECT  8.244 25.882 8.262 25.92 ;
    END
  END o_x0[263]
  PIN o_x0[264]
    DIRECTION OUTPUT ;
    USE SIGNAL ;
    PORT
      LAYER M5 ;
        RECT  8.352 25.836 8.376 25.92 ;
    END
  END o_x0[264]
  PIN o_x0[265]
    DIRECTION OUTPUT ;
    USE SIGNAL ;
    PORT
      LAYER M3 ;
        RECT  8.46 25.882 8.478 25.92 ;
    END
  END o_x0[265]
  PIN o_x0[266]
    DIRECTION OUTPUT ;
    USE SIGNAL ;
    PORT
      LAYER M3 ;
        RECT  7.308 25.882 7.326 25.92 ;
    END
  END o_x0[266]
  PIN o_x0[267]
    DIRECTION OUTPUT ;
    USE SIGNAL ;
    PORT
      LAYER M5 ;
        RECT  7.392 25.836 7.416 25.92 ;
    END
  END o_x0[267]
  PIN o_x0[268]
    DIRECTION OUTPUT ;
    USE SIGNAL ;
    PORT
      LAYER M3 ;
        RECT  7.488 25.882 7.506 25.92 ;
    END
  END o_x0[268]
  PIN o_x0[269]
    DIRECTION OUTPUT ;
    USE SIGNAL ;
    PORT
      LAYER M5 ;
        RECT  9.456 25.836 9.48 25.92 ;
    END
  END o_x0[269]
  PIN o_x0[26]
    DIRECTION OUTPUT ;
    USE SIGNAL ;
    PORT
      LAYER M3 ;
        RECT  12.852 25.882 12.87 25.92 ;
    END
  END o_x0[26]
  PIN o_x0[270]
    DIRECTION OUTPUT ;
    USE SIGNAL ;
    PORT
      LAYER M3 ;
        RECT  9.54 25.882 9.558 25.92 ;
    END
  END o_x0[270]
  PIN o_x0[271]
    DIRECTION OUTPUT ;
    USE SIGNAL ;
    PORT
      LAYER M5 ;
        RECT  9.648 25.836 9.672 25.92 ;
    END
  END o_x0[271]
  PIN o_x0[272]
    DIRECTION OUTPUT ;
    USE SIGNAL ;
    PORT
      LAYER M3 ;
        RECT  9.756 25.882 9.774 25.92 ;
    END
  END o_x0[272]
  PIN o_x0[273]
    DIRECTION OUTPUT ;
    USE SIGNAL ;
    PORT
      LAYER M5 ;
        RECT  9.84 25.836 9.864 25.92 ;
    END
  END o_x0[273]
  PIN o_x0[274]
    DIRECTION OUTPUT ;
    USE SIGNAL ;
    PORT
      LAYER M3 ;
        RECT  9.9 25.882 9.918 25.92 ;
    END
  END o_x0[274]
  PIN o_x0[275]
    DIRECTION OUTPUT ;
    USE SIGNAL ;
    PORT
      LAYER M5 ;
        RECT  9.984 25.836 10.008 25.92 ;
    END
  END o_x0[275]
  PIN o_x0[276]
    DIRECTION OUTPUT ;
    USE SIGNAL ;
    PORT
      LAYER M3 ;
        RECT  10.08 25.882 10.098 25.92 ;
    END
  END o_x0[276]
  PIN o_x0[277]
    DIRECTION OUTPUT ;
    USE SIGNAL ;
    PORT
      LAYER M5 ;
        RECT  10.176 25.836 10.2 25.92 ;
    END
  END o_x0[277]
  PIN o_x0[278]
    DIRECTION OUTPUT ;
    USE SIGNAL ;
    PORT
      LAYER M3 ;
        RECT  10.26 25.882 10.278 25.92 ;
    END
  END o_x0[278]
  PIN o_x0[279]
    DIRECTION OUTPUT ;
    USE SIGNAL ;
    PORT
      LAYER M5 ;
        RECT  10.368 25.836 10.392 25.92 ;
    END
  END o_x0[279]
  PIN o_x0[27]
    DIRECTION OUTPUT ;
    USE SIGNAL ;
    PORT
      LAYER M5 ;
        RECT  12.96 25.836 12.984 25.92 ;
    END
  END o_x0[27]
  PIN o_x0[280]
    DIRECTION OUTPUT ;
    USE SIGNAL ;
    PORT
      LAYER M3 ;
        RECT  58.068 25.882 58.086 25.92 ;
    END
  END o_x0[280]
  PIN o_x0[281]
    DIRECTION OUTPUT ;
    USE SIGNAL ;
    PORT
      LAYER M5 ;
        RECT  58.176 25.836 58.2 25.92 ;
    END
  END o_x0[281]
  PIN o_x0[282]
    DIRECTION OUTPUT ;
    USE SIGNAL ;
    PORT
      LAYER M3 ;
        RECT  58.284 25.882 58.302 25.92 ;
    END
  END o_x0[282]
  PIN o_x0[28]
    DIRECTION OUTPUT ;
    USE SIGNAL ;
    PORT
      LAYER M3 ;
        RECT  13.068 25.882 13.086 25.92 ;
    END
  END o_x0[28]
  PIN o_x0[29]
    DIRECTION OUTPUT ;
    USE SIGNAL ;
    PORT
      LAYER M5 ;
        RECT  13.152 25.836 13.176 25.92 ;
    END
  END o_x0[29]
  PIN o_x0[2]
    DIRECTION OUTPUT ;
    USE SIGNAL ;
    PORT
      LAYER M3 ;
        RECT  10.656 25.882 10.674 25.92 ;
    END
  END o_x0[2]
  PIN o_x0[30]
    DIRECTION OUTPUT ;
    USE SIGNAL ;
    PORT
      LAYER M3 ;
        RECT  13.248 25.882 13.266 25.92 ;
    END
  END o_x0[30]
  PIN o_x0[31]
    DIRECTION OUTPUT ;
    USE SIGNAL ;
    PORT
      LAYER M5 ;
        RECT  13.344 25.836 13.368 25.92 ;
    END
  END o_x0[31]
  PIN o_x0[32]
    DIRECTION OUTPUT ;
    USE SIGNAL ;
    PORT
      LAYER M3 ;
        RECT  13.428 25.882 13.446 25.92 ;
    END
  END o_x0[32]
  PIN o_x0[33]
    DIRECTION OUTPUT ;
    USE SIGNAL ;
    PORT
      LAYER M5 ;
        RECT  13.536 25.836 13.56 25.92 ;
    END
  END o_x0[33]
  PIN o_x0[34]
    DIRECTION OUTPUT ;
    USE SIGNAL ;
    PORT
      LAYER M3 ;
        RECT  13.644 25.882 13.662 25.92 ;
    END
  END o_x0[34]
  PIN o_x0[35]
    DIRECTION OUTPUT ;
    USE SIGNAL ;
    PORT
      LAYER M5 ;
        RECT  13.728 25.836 13.752 25.92 ;
    END
  END o_x0[35]
  PIN o_x0[36]
    DIRECTION OUTPUT ;
    USE SIGNAL ;
    PORT
      LAYER M3 ;
        RECT  13.824 25.882 13.842 25.92 ;
    END
  END o_x0[36]
  PIN o_x0[37]
    DIRECTION OUTPUT ;
    USE SIGNAL ;
    PORT
      LAYER M5 ;
        RECT  13.92 25.836 13.944 25.92 ;
    END
  END o_x0[37]
  PIN o_x0[38]
    DIRECTION OUTPUT ;
    USE SIGNAL ;
    PORT
      LAYER M3 ;
        RECT  14.004 25.882 14.022 25.92 ;
    END
  END o_x0[38]
  PIN o_x0[39]
    DIRECTION OUTPUT ;
    USE SIGNAL ;
    PORT
      LAYER M5 ;
        RECT  14.112 25.836 14.136 25.92 ;
    END
  END o_x0[39]
  PIN o_x0[3]
    DIRECTION OUTPUT ;
    USE SIGNAL ;
    PORT
      LAYER M5 ;
        RECT  10.752 25.836 10.776 25.92 ;
    END
  END o_x0[3]
  PIN o_x0[40]
    DIRECTION OUTPUT ;
    USE SIGNAL ;
    PORT
      LAYER M3 ;
        RECT  14.22 25.882 14.238 25.92 ;
    END
  END o_x0[40]
  PIN o_x0[41]
    DIRECTION OUTPUT ;
    USE SIGNAL ;
    PORT
      LAYER M5 ;
        RECT  14.304 25.836 14.328 25.92 ;
    END
  END o_x0[41]
  PIN o_x0[42]
    DIRECTION OUTPUT ;
    USE SIGNAL ;
    PORT
      LAYER M3 ;
        RECT  14.364 25.882 14.382 25.92 ;
    END
  END o_x0[42]
  PIN o_x0[43]
    DIRECTION OUTPUT ;
    USE SIGNAL ;
    PORT
      LAYER M5 ;
        RECT  14.448 25.836 14.472 25.92 ;
    END
  END o_x0[43]
  PIN o_x0[44]
    DIRECTION OUTPUT ;
    USE SIGNAL ;
    PORT
      LAYER M3 ;
        RECT  14.544 25.882 14.562 25.92 ;
    END
  END o_x0[44]
  PIN o_x0[45]
    DIRECTION OUTPUT ;
    USE SIGNAL ;
    PORT
      LAYER M5 ;
        RECT  14.64 25.836 14.664 25.92 ;
    END
  END o_x0[45]
  PIN o_x0[46]
    DIRECTION OUTPUT ;
    USE SIGNAL ;
    PORT
      LAYER M3 ;
        RECT  14.724 25.882 14.742 25.92 ;
    END
  END o_x0[46]
  PIN o_x0[47]
    DIRECTION OUTPUT ;
    USE SIGNAL ;
    PORT
      LAYER M5 ;
        RECT  14.832 25.836 14.856 25.92 ;
    END
  END o_x0[47]
  PIN o_x0[48]
    DIRECTION OUTPUT ;
    USE SIGNAL ;
    PORT
      LAYER M3 ;
        RECT  14.94 25.882 14.958 25.92 ;
    END
  END o_x0[48]
  PIN o_x0[49]
    DIRECTION OUTPUT ;
    USE SIGNAL ;
    PORT
      LAYER M5 ;
        RECT  15.024 25.836 15.048 25.92 ;
    END
  END o_x0[49]
  PIN o_x0[4]
    DIRECTION OUTPUT ;
    USE SIGNAL ;
    PORT
      LAYER M3 ;
        RECT  10.836 25.882 10.854 25.92 ;
    END
  END o_x0[4]
  PIN o_x0[50]
    DIRECTION OUTPUT ;
    USE SIGNAL ;
    PORT
      LAYER M3 ;
        RECT  15.12 25.882 15.138 25.92 ;
    END
  END o_x0[50]
  PIN o_x0[51]
    DIRECTION OUTPUT ;
    USE SIGNAL ;
    PORT
      LAYER M5 ;
        RECT  15.216 25.836 15.24 25.92 ;
    END
  END o_x0[51]
  PIN o_x0[52]
    DIRECTION OUTPUT ;
    USE SIGNAL ;
    PORT
      LAYER M3 ;
        RECT  15.3 25.882 15.318 25.92 ;
    END
  END o_x0[52]
  PIN o_x0[53]
    DIRECTION OUTPUT ;
    USE SIGNAL ;
    PORT
      LAYER M5 ;
        RECT  15.408 25.836 15.432 25.92 ;
    END
  END o_x0[53]
  PIN o_x0[54]
    DIRECTION OUTPUT ;
    USE SIGNAL ;
    PORT
      LAYER M3 ;
        RECT  15.516 25.882 15.534 25.92 ;
    END
  END o_x0[54]
  PIN o_x0[55]
    DIRECTION OUTPUT ;
    USE SIGNAL ;
    PORT
      LAYER M5 ;
        RECT  15.6 25.836 15.624 25.92 ;
    END
  END o_x0[55]
  PIN o_x0[56]
    DIRECTION OUTPUT ;
    USE SIGNAL ;
    PORT
      LAYER M3 ;
        RECT  15.696 25.882 15.714 25.92 ;
    END
  END o_x0[56]
  PIN o_x0[57]
    DIRECTION OUTPUT ;
    USE SIGNAL ;
    PORT
      LAYER M5 ;
        RECT  15.792 25.836 15.816 25.92 ;
    END
  END o_x0[57]
  PIN o_x0[58]
    DIRECTION OUTPUT ;
    USE SIGNAL ;
    PORT
      LAYER M3 ;
        RECT  15.84 25.882 15.858 25.92 ;
    END
  END o_x0[58]
  PIN o_x0[59]
    DIRECTION OUTPUT ;
    USE SIGNAL ;
    PORT
      LAYER M5 ;
        RECT  15.936 25.836 15.96 25.92 ;
    END
  END o_x0[59]
  PIN o_x0[5]
    DIRECTION OUTPUT ;
    USE SIGNAL ;
    PORT
      LAYER M5 ;
        RECT  10.944 25.836 10.968 25.92 ;
    END
  END o_x0[5]
  PIN o_x0[60]
    DIRECTION OUTPUT ;
    USE SIGNAL ;
    PORT
      LAYER M3 ;
        RECT  16.02 25.882 16.038 25.92 ;
    END
  END o_x0[60]
  PIN o_x0[61]
    DIRECTION OUTPUT ;
    USE SIGNAL ;
    PORT
      LAYER M5 ;
        RECT  16.128 25.836 16.152 25.92 ;
    END
  END o_x0[61]
  PIN o_x0[62]
    DIRECTION OUTPUT ;
    USE SIGNAL ;
    PORT
      LAYER M3 ;
        RECT  16.236 25.882 16.254 25.92 ;
    END
  END o_x0[62]
  PIN o_x0[63]
    DIRECTION OUTPUT ;
    USE SIGNAL ;
    PORT
      LAYER M5 ;
        RECT  16.32 25.836 16.344 25.92 ;
    END
  END o_x0[63]
  PIN o_x0[64]
    DIRECTION OUTPUT ;
    USE SIGNAL ;
    PORT
      LAYER M3 ;
        RECT  16.416 25.882 16.434 25.92 ;
    END
  END o_x0[64]
  PIN o_x0[65]
    DIRECTION OUTPUT ;
    USE SIGNAL ;
    PORT
      LAYER M5 ;
        RECT  16.512 25.836 16.536 25.92 ;
    END
  END o_x0[65]
  PIN o_x0[66]
    DIRECTION OUTPUT ;
    USE SIGNAL ;
    PORT
      LAYER M3 ;
        RECT  16.596 25.882 16.614 25.92 ;
    END
  END o_x0[66]
  PIN o_x0[67]
    DIRECTION OUTPUT ;
    USE SIGNAL ;
    PORT
      LAYER M5 ;
        RECT  16.704 25.836 16.728 25.92 ;
    END
  END o_x0[67]
  PIN o_x0[68]
    DIRECTION OUTPUT ;
    USE SIGNAL ;
    PORT
      LAYER M3 ;
        RECT  16.812 25.882 16.83 25.92 ;
    END
  END o_x0[68]
  PIN o_x0[69]
    DIRECTION OUTPUT ;
    USE SIGNAL ;
    PORT
      LAYER M5 ;
        RECT  16.896 25.836 16.92 25.92 ;
    END
  END o_x0[69]
  PIN o_x0[6]
    DIRECTION OUTPUT ;
    USE SIGNAL ;
    PORT
      LAYER M3 ;
        RECT  11.052 25.882 11.07 25.92 ;
    END
  END o_x0[6]
  PIN o_x0[70]
    DIRECTION OUTPUT ;
    USE SIGNAL ;
    PORT
      LAYER M3 ;
        RECT  16.992 25.882 17.01 25.92 ;
    END
  END o_x0[70]
  PIN o_x0[71]
    DIRECTION OUTPUT ;
    USE SIGNAL ;
    PORT
      LAYER M5 ;
        RECT  17.088 25.836 17.112 25.92 ;
    END
  END o_x0[71]
  PIN o_x0[72]
    DIRECTION OUTPUT ;
    USE SIGNAL ;
    PORT
      LAYER M3 ;
        RECT  17.172 25.882 17.19 25.92 ;
    END
  END o_x0[72]
  PIN o_x0[73]
    DIRECTION OUTPUT ;
    USE SIGNAL ;
    PORT
      LAYER M5 ;
        RECT  17.28 25.836 17.304 25.92 ;
    END
  END o_x0[73]
  PIN o_x0[74]
    DIRECTION OUTPUT ;
    USE SIGNAL ;
    PORT
      LAYER M3 ;
        RECT  17.316 25.882 17.334 25.92 ;
    END
  END o_x0[74]
  PIN o_x0[75]
    DIRECTION OUTPUT ;
    USE SIGNAL ;
    PORT
      LAYER M5 ;
        RECT  17.424 25.836 17.448 25.92 ;
    END
  END o_x0[75]
  PIN o_x0[76]
    DIRECTION OUTPUT ;
    USE SIGNAL ;
    PORT
      LAYER M3 ;
        RECT  17.532 25.882 17.55 25.92 ;
    END
  END o_x0[76]
  PIN o_x0[77]
    DIRECTION OUTPUT ;
    USE SIGNAL ;
    PORT
      LAYER M5 ;
        RECT  17.616 25.836 17.64 25.92 ;
    END
  END o_x0[77]
  PIN o_x0[78]
    DIRECTION OUTPUT ;
    USE SIGNAL ;
    PORT
      LAYER M3 ;
        RECT  17.712 25.882 17.73 25.92 ;
    END
  END o_x0[78]
  PIN o_x0[79]
    DIRECTION OUTPUT ;
    USE SIGNAL ;
    PORT
      LAYER M5 ;
        RECT  17.808 25.836 17.832 25.92 ;
    END
  END o_x0[79]
  PIN o_x0[7]
    DIRECTION OUTPUT ;
    USE SIGNAL ;
    PORT
      LAYER M5 ;
        RECT  11.136 25.836 11.16 25.92 ;
    END
  END o_x0[7]
  PIN o_x0[80]
    DIRECTION OUTPUT ;
    USE SIGNAL ;
    PORT
      LAYER M3 ;
        RECT  17.892 25.882 17.91 25.92 ;
    END
  END o_x0[80]
  PIN o_x0[81]
    DIRECTION OUTPUT ;
    USE SIGNAL ;
    PORT
      LAYER M5 ;
        RECT  18 25.836 18.024 25.92 ;
    END
  END o_x0[81]
  PIN o_x0[82]
    DIRECTION OUTPUT ;
    USE SIGNAL ;
    PORT
      LAYER M3 ;
        RECT  18.108 25.882 18.126 25.92 ;
    END
  END o_x0[82]
  PIN o_x0[83]
    DIRECTION OUTPUT ;
    USE SIGNAL ;
    PORT
      LAYER M5 ;
        RECT  18.192 25.836 18.216 25.92 ;
    END
  END o_x0[83]
  PIN o_x0[84]
    DIRECTION OUTPUT ;
    USE SIGNAL ;
    PORT
      LAYER M3 ;
        RECT  18.288 25.882 18.306 25.92 ;
    END
  END o_x0[84]
  PIN o_x0[85]
    DIRECTION OUTPUT ;
    USE SIGNAL ;
    PORT
      LAYER M5 ;
        RECT  18.384 25.836 18.408 25.92 ;
    END
  END o_x0[85]
  PIN o_x0[86]
    DIRECTION OUTPUT ;
    USE SIGNAL ;
    PORT
      LAYER M3 ;
        RECT  18.468 25.882 18.486 25.92 ;
    END
  END o_x0[86]
  PIN o_x0[87]
    DIRECTION OUTPUT ;
    USE SIGNAL ;
    PORT
      LAYER M5 ;
        RECT  18.576 25.836 18.6 25.92 ;
    END
  END o_x0[87]
  PIN o_x0[88]
    DIRECTION OUTPUT ;
    USE SIGNAL ;
    PORT
      LAYER M3 ;
        RECT  18.684 25.882 18.702 25.92 ;
    END
  END o_x0[88]
  PIN o_x0[89]
    DIRECTION OUTPUT ;
    USE SIGNAL ;
    PORT
      LAYER M5 ;
        RECT  18.768 25.836 18.792 25.92 ;
    END
  END o_x0[89]
  PIN o_x0[8]
    DIRECTION OUTPUT ;
    USE SIGNAL ;
    PORT
      LAYER M3 ;
        RECT  11.232 25.882 11.25 25.92 ;
    END
  END o_x0[8]
  PIN o_x0[90]
    DIRECTION OUTPUT ;
    USE SIGNAL ;
    PORT
      LAYER M3 ;
        RECT  18.828 25.882 18.846 25.92 ;
    END
  END o_x0[90]
  PIN o_x0[91]
    DIRECTION OUTPUT ;
    USE SIGNAL ;
    PORT
      LAYER M5 ;
        RECT  18.912 25.836 18.936 25.92 ;
    END
  END o_x0[91]
  PIN o_x0[92]
    DIRECTION OUTPUT ;
    USE SIGNAL ;
    PORT
      LAYER M3 ;
        RECT  19.008 25.882 19.026 25.92 ;
    END
  END o_x0[92]
  PIN o_x0[93]
    DIRECTION OUTPUT ;
    USE SIGNAL ;
    PORT
      LAYER M5 ;
        RECT  19.104 25.836 19.128 25.92 ;
    END
  END o_x0[93]
  PIN o_x0[94]
    DIRECTION OUTPUT ;
    USE SIGNAL ;
    PORT
      LAYER M3 ;
        RECT  19.188 25.882 19.206 25.92 ;
    END
  END o_x0[94]
  PIN o_x0[95]
    DIRECTION OUTPUT ;
    USE SIGNAL ;
    PORT
      LAYER M5 ;
        RECT  19.296 25.836 19.32 25.92 ;
    END
  END o_x0[95]
  PIN o_x0[96]
    DIRECTION OUTPUT ;
    USE SIGNAL ;
    PORT
      LAYER M3 ;
        RECT  19.404 25.882 19.422 25.92 ;
    END
  END o_x0[96]
  PIN o_x0[97]
    DIRECTION OUTPUT ;
    USE SIGNAL ;
    PORT
      LAYER M5 ;
        RECT  19.488 25.836 19.512 25.92 ;
    END
  END o_x0[97]
  PIN o_x0[98]
    DIRECTION OUTPUT ;
    USE SIGNAL ;
    PORT
      LAYER M3 ;
        RECT  19.584 25.882 19.602 25.92 ;
    END
  END o_x0[98]
  PIN o_x0[99]
    DIRECTION OUTPUT ;
    USE SIGNAL ;
    PORT
      LAYER M5 ;
        RECT  19.68 25.836 19.704 25.92 ;
    END
  END o_x0[99]
  PIN o_x0[9]
    DIRECTION OUTPUT ;
    USE SIGNAL ;
    PORT
      LAYER M5 ;
        RECT  11.328 25.836 11.352 25.92 ;
    END
  END o_x0[9]
  PIN o_x1[0]
    DIRECTION OUTPUT ;
    USE SIGNAL ;
    PORT
      LAYER M3 ;
        RECT  34.272 25.882 34.29 25.92 ;
    END
  END o_x1[0]
  PIN o_x1[100]
    DIRECTION OUTPUT ;
    USE SIGNAL ;
    PORT
      LAYER M3 ;
        RECT  43.596 25.882 43.614 25.92 ;
    END
  END o_x1[100]
  PIN o_x1[101]
    DIRECTION OUTPUT ;
    USE SIGNAL ;
    PORT
      LAYER M5 ;
        RECT  43.68 25.836 43.704 25.92 ;
    END
  END o_x1[101]
  PIN o_x1[102]
    DIRECTION OUTPUT ;
    USE SIGNAL ;
    PORT
      LAYER M3 ;
        RECT  43.776 25.882 43.794 25.92 ;
    END
  END o_x1[102]
  PIN o_x1[103]
    DIRECTION OUTPUT ;
    USE SIGNAL ;
    PORT
      LAYER M5 ;
        RECT  43.872 25.836 43.896 25.92 ;
    END
  END o_x1[103]
  PIN o_x1[104]
    DIRECTION OUTPUT ;
    USE SIGNAL ;
    PORT
      LAYER M3 ;
        RECT  43.92 25.882 43.938 25.92 ;
    END
  END o_x1[104]
  PIN o_x1[105]
    DIRECTION OUTPUT ;
    USE SIGNAL ;
    PORT
      LAYER M5 ;
        RECT  44.016 25.836 44.04 25.92 ;
    END
  END o_x1[105]
  PIN o_x1[106]
    DIRECTION OUTPUT ;
    USE SIGNAL ;
    PORT
      LAYER M3 ;
        RECT  44.1 25.882 44.118 25.92 ;
    END
  END o_x1[106]
  PIN o_x1[107]
    DIRECTION OUTPUT ;
    USE SIGNAL ;
    PORT
      LAYER M5 ;
        RECT  44.208 25.836 44.232 25.92 ;
    END
  END o_x1[107]
  PIN o_x1[108]
    DIRECTION OUTPUT ;
    USE SIGNAL ;
    PORT
      LAYER M3 ;
        RECT  44.316 25.882 44.334 25.92 ;
    END
  END o_x1[108]
  PIN o_x1[109]
    DIRECTION OUTPUT ;
    USE SIGNAL ;
    PORT
      LAYER M5 ;
        RECT  44.4 25.836 44.424 25.92 ;
    END
  END o_x1[109]
  PIN o_x1[10]
    DIRECTION OUTPUT ;
    USE SIGNAL ;
    PORT
      LAYER M3 ;
        RECT  35.172 25.882 35.19 25.92 ;
    END
  END o_x1[10]
  PIN o_x1[110]
    DIRECTION OUTPUT ;
    USE SIGNAL ;
    PORT
      LAYER M3 ;
        RECT  44.496 25.882 44.514 25.92 ;
    END
  END o_x1[110]
  PIN o_x1[111]
    DIRECTION OUTPUT ;
    USE SIGNAL ;
    PORT
      LAYER M5 ;
        RECT  44.592 25.836 44.616 25.92 ;
    END
  END o_x1[111]
  PIN o_x1[112]
    DIRECTION OUTPUT ;
    USE SIGNAL ;
    PORT
      LAYER M3 ;
        RECT  44.676 25.882 44.694 25.92 ;
    END
  END o_x1[112]
  PIN o_x1[113]
    DIRECTION OUTPUT ;
    USE SIGNAL ;
    PORT
      LAYER M5 ;
        RECT  44.784 25.836 44.808 25.92 ;
    END
  END o_x1[113]
  PIN o_x1[114]
    DIRECTION OUTPUT ;
    USE SIGNAL ;
    PORT
      LAYER M3 ;
        RECT  44.892 25.882 44.91 25.92 ;
    END
  END o_x1[114]
  PIN o_x1[115]
    DIRECTION OUTPUT ;
    USE SIGNAL ;
    PORT
      LAYER M5 ;
        RECT  44.976 25.836 45 25.92 ;
    END
  END o_x1[115]
  PIN o_x1[116]
    DIRECTION OUTPUT ;
    USE SIGNAL ;
    PORT
      LAYER M3 ;
        RECT  45.072 25.882 45.09 25.92 ;
    END
  END o_x1[116]
  PIN o_x1[117]
    DIRECTION OUTPUT ;
    USE SIGNAL ;
    PORT
      LAYER M5 ;
        RECT  45.168 25.836 45.192 25.92 ;
    END
  END o_x1[117]
  PIN o_x1[118]
    DIRECTION OUTPUT ;
    USE SIGNAL ;
    PORT
      LAYER M3 ;
        RECT  45.252 25.882 45.27 25.92 ;
    END
  END o_x1[118]
  PIN o_x1[119]
    DIRECTION OUTPUT ;
    USE SIGNAL ;
    PORT
      LAYER M5 ;
        RECT  45.36 25.836 45.384 25.92 ;
    END
  END o_x1[119]
  PIN o_x1[11]
    DIRECTION OUTPUT ;
    USE SIGNAL ;
    PORT
      LAYER M5 ;
        RECT  35.28 25.836 35.304 25.92 ;
    END
  END o_x1[11]
  PIN o_x1[120]
    DIRECTION OUTPUT ;
    USE SIGNAL ;
    PORT
      LAYER M3 ;
        RECT  45.396 25.882 45.414 25.92 ;
    END
  END o_x1[120]
  PIN o_x1[121]
    DIRECTION OUTPUT ;
    USE SIGNAL ;
    PORT
      LAYER M5 ;
        RECT  45.504 25.836 45.528 25.92 ;
    END
  END o_x1[121]
  PIN o_x1[122]
    DIRECTION OUTPUT ;
    USE SIGNAL ;
    PORT
      LAYER M3 ;
        RECT  45.612 25.882 45.63 25.92 ;
    END
  END o_x1[122]
  PIN o_x1[123]
    DIRECTION OUTPUT ;
    USE SIGNAL ;
    PORT
      LAYER M5 ;
        RECT  45.696 25.836 45.72 25.92 ;
    END
  END o_x1[123]
  PIN o_x1[124]
    DIRECTION OUTPUT ;
    USE SIGNAL ;
    PORT
      LAYER M3 ;
        RECT  45.792 25.882 45.81 25.92 ;
    END
  END o_x1[124]
  PIN o_x1[125]
    DIRECTION OUTPUT ;
    USE SIGNAL ;
    PORT
      LAYER M5 ;
        RECT  45.888 25.836 45.912 25.92 ;
    END
  END o_x1[125]
  PIN o_x1[126]
    DIRECTION OUTPUT ;
    USE SIGNAL ;
    PORT
      LAYER M3 ;
        RECT  45.972 25.882 45.99 25.92 ;
    END
  END o_x1[126]
  PIN o_x1[127]
    DIRECTION OUTPUT ;
    USE SIGNAL ;
    PORT
      LAYER M5 ;
        RECT  46.08 25.836 46.104 25.92 ;
    END
  END o_x1[127]
  PIN o_x1[128]
    DIRECTION OUTPUT ;
    USE SIGNAL ;
    PORT
      LAYER M3 ;
        RECT  46.188 25.882 46.206 25.92 ;
    END
  END o_x1[128]
  PIN o_x1[129]
    DIRECTION OUTPUT ;
    USE SIGNAL ;
    PORT
      LAYER M5 ;
        RECT  46.272 25.836 46.296 25.92 ;
    END
  END o_x1[129]
  PIN o_x1[12]
    DIRECTION OUTPUT ;
    USE SIGNAL ;
    PORT
      LAYER M3 ;
        RECT  35.388 25.882 35.406 25.92 ;
    END
  END o_x1[12]
  PIN o_x1[130]
    DIRECTION OUTPUT ;
    USE SIGNAL ;
    PORT
      LAYER M3 ;
        RECT  46.368 25.882 46.386 25.92 ;
    END
  END o_x1[130]
  PIN o_x1[131]
    DIRECTION OUTPUT ;
    USE SIGNAL ;
    PORT
      LAYER M5 ;
        RECT  46.464 25.836 46.488 25.92 ;
    END
  END o_x1[131]
  PIN o_x1[132]
    DIRECTION OUTPUT ;
    USE SIGNAL ;
    PORT
      LAYER M3 ;
        RECT  46.548 25.882 46.566 25.92 ;
    END
  END o_x1[132]
  PIN o_x1[133]
    DIRECTION OUTPUT ;
    USE SIGNAL ;
    PORT
      LAYER M5 ;
        RECT  46.656 25.836 46.68 25.92 ;
    END
  END o_x1[133]
  PIN o_x1[134]
    DIRECTION OUTPUT ;
    USE SIGNAL ;
    PORT
      LAYER M3 ;
        RECT  46.764 25.882 46.782 25.92 ;
    END
  END o_x1[134]
  PIN o_x1[135]
    DIRECTION OUTPUT ;
    USE SIGNAL ;
    PORT
      LAYER M5 ;
        RECT  46.848 25.836 46.872 25.92 ;
    END
  END o_x1[135]
  PIN o_x1[136]
    DIRECTION OUTPUT ;
    USE SIGNAL ;
    PORT
      LAYER M3 ;
        RECT  46.908 25.882 46.926 25.92 ;
    END
  END o_x1[136]
  PIN o_x1[137]
    DIRECTION OUTPUT ;
    USE SIGNAL ;
    PORT
      LAYER M5 ;
        RECT  46.992 25.836 47.016 25.92 ;
    END
  END o_x1[137]
  PIN o_x1[138]
    DIRECTION OUTPUT ;
    USE SIGNAL ;
    PORT
      LAYER M3 ;
        RECT  47.088 25.882 47.106 25.92 ;
    END
  END o_x1[138]
  PIN o_x1[139]
    DIRECTION OUTPUT ;
    USE SIGNAL ;
    PORT
      LAYER M5 ;
        RECT  47.184 25.836 47.208 25.92 ;
    END
  END o_x1[139]
  PIN o_x1[13]
    DIRECTION OUTPUT ;
    USE SIGNAL ;
    PORT
      LAYER M5 ;
        RECT  35.472 25.836 35.496 25.92 ;
    END
  END o_x1[13]
  PIN o_x1[140]
    DIRECTION OUTPUT ;
    USE SIGNAL ;
    PORT
      LAYER M3 ;
        RECT  47.268 25.882 47.286 25.92 ;
    END
  END o_x1[140]
  PIN o_x1[141]
    DIRECTION OUTPUT ;
    USE SIGNAL ;
    PORT
      LAYER M5 ;
        RECT  47.376 25.836 47.4 25.92 ;
    END
  END o_x1[141]
  PIN o_x1[142]
    DIRECTION OUTPUT ;
    USE SIGNAL ;
    PORT
      LAYER M3 ;
        RECT  47.484 25.882 47.502 25.92 ;
    END
  END o_x1[142]
  PIN o_x1[143]
    DIRECTION OUTPUT ;
    USE SIGNAL ;
    PORT
      LAYER M5 ;
        RECT  47.568 25.836 47.592 25.92 ;
    END
  END o_x1[143]
  PIN o_x1[144]
    DIRECTION OUTPUT ;
    USE SIGNAL ;
    PORT
      LAYER M3 ;
        RECT  47.664 25.882 47.682 25.92 ;
    END
  END o_x1[144]
  PIN o_x1[145]
    DIRECTION OUTPUT ;
    USE SIGNAL ;
    PORT
      LAYER M5 ;
        RECT  47.76 25.836 47.784 25.92 ;
    END
  END o_x1[145]
  PIN o_x1[146]
    DIRECTION OUTPUT ;
    USE SIGNAL ;
    PORT
      LAYER M3 ;
        RECT  47.844 25.882 47.862 25.92 ;
    END
  END o_x1[146]
  PIN o_x1[147]
    DIRECTION OUTPUT ;
    USE SIGNAL ;
    PORT
      LAYER M5 ;
        RECT  47.952 25.836 47.976 25.92 ;
    END
  END o_x1[147]
  PIN o_x1[148]
    DIRECTION OUTPUT ;
    USE SIGNAL ;
    PORT
      LAYER M3 ;
        RECT  48.06 25.882 48.078 25.92 ;
    END
  END o_x1[148]
  PIN o_x1[149]
    DIRECTION OUTPUT ;
    USE SIGNAL ;
    PORT
      LAYER M5 ;
        RECT  48.144 25.836 48.168 25.92 ;
    END
  END o_x1[149]
  PIN o_x1[14]
    DIRECTION OUTPUT ;
    USE SIGNAL ;
    PORT
      LAYER M3 ;
        RECT  35.568 25.882 35.586 25.92 ;
    END
  END o_x1[14]
  PIN o_x1[150]
    DIRECTION OUTPUT ;
    USE SIGNAL ;
    PORT
      LAYER M3 ;
        RECT  48.24 25.882 48.258 25.92 ;
    END
  END o_x1[150]
  PIN o_x1[151]
    DIRECTION OUTPUT ;
    USE SIGNAL ;
    PORT
      LAYER M5 ;
        RECT  48.336 25.836 48.36 25.92 ;
    END
  END o_x1[151]
  PIN o_x1[152]
    DIRECTION OUTPUT ;
    USE SIGNAL ;
    PORT
      LAYER M3 ;
        RECT  48.384 25.882 48.402 25.92 ;
    END
  END o_x1[152]
  PIN o_x1[153]
    DIRECTION OUTPUT ;
    USE SIGNAL ;
    PORT
      LAYER M5 ;
        RECT  48.48 25.836 48.504 25.92 ;
    END
  END o_x1[153]
  PIN o_x1[154]
    DIRECTION OUTPUT ;
    USE SIGNAL ;
    PORT
      LAYER M3 ;
        RECT  48.564 25.882 48.582 25.92 ;
    END
  END o_x1[154]
  PIN o_x1[155]
    DIRECTION OUTPUT ;
    USE SIGNAL ;
    PORT
      LAYER M5 ;
        RECT  48.672 25.836 48.696 25.92 ;
    END
  END o_x1[155]
  PIN o_x1[156]
    DIRECTION OUTPUT ;
    USE SIGNAL ;
    PORT
      LAYER M3 ;
        RECT  48.78 25.882 48.798 25.92 ;
    END
  END o_x1[156]
  PIN o_x1[157]
    DIRECTION OUTPUT ;
    USE SIGNAL ;
    PORT
      LAYER M5 ;
        RECT  48.864 25.836 48.888 25.92 ;
    END
  END o_x1[157]
  PIN o_x1[158]
    DIRECTION OUTPUT ;
    USE SIGNAL ;
    PORT
      LAYER M3 ;
        RECT  48.96 25.882 48.978 25.92 ;
    END
  END o_x1[158]
  PIN o_x1[159]
    DIRECTION OUTPUT ;
    USE SIGNAL ;
    PORT
      LAYER M5 ;
        RECT  49.056 25.836 49.08 25.92 ;
    END
  END o_x1[159]
  PIN o_x1[15]
    DIRECTION OUTPUT ;
    USE SIGNAL ;
    PORT
      LAYER M5 ;
        RECT  35.664 25.836 35.688 25.92 ;
    END
  END o_x1[15]
  PIN o_x1[160]
    DIRECTION OUTPUT ;
    USE SIGNAL ;
    PORT
      LAYER M3 ;
        RECT  49.14 25.882 49.158 25.92 ;
    END
  END o_x1[160]
  PIN o_x1[161]
    DIRECTION OUTPUT ;
    USE SIGNAL ;
    PORT
      LAYER M5 ;
        RECT  49.248 25.836 49.272 25.92 ;
    END
  END o_x1[161]
  PIN o_x1[162]
    DIRECTION OUTPUT ;
    USE SIGNAL ;
    PORT
      LAYER M3 ;
        RECT  49.356 25.882 49.374 25.92 ;
    END
  END o_x1[162]
  PIN o_x1[163]
    DIRECTION OUTPUT ;
    USE SIGNAL ;
    PORT
      LAYER M5 ;
        RECT  49.44 25.836 49.464 25.92 ;
    END
  END o_x1[163]
  PIN o_x1[164]
    DIRECTION OUTPUT ;
    USE SIGNAL ;
    PORT
      LAYER M3 ;
        RECT  49.536 25.882 49.554 25.92 ;
    END
  END o_x1[164]
  PIN o_x1[165]
    DIRECTION OUTPUT ;
    USE SIGNAL ;
    PORT
      LAYER M5 ;
        RECT  49.632 25.836 49.656 25.92 ;
    END
  END o_x1[165]
  PIN o_x1[166]
    DIRECTION OUTPUT ;
    USE SIGNAL ;
    PORT
      LAYER M3 ;
        RECT  49.716 25.882 49.734 25.92 ;
    END
  END o_x1[166]
  PIN o_x1[167]
    DIRECTION OUTPUT ;
    USE SIGNAL ;
    PORT
      LAYER M5 ;
        RECT  49.824 25.836 49.848 25.92 ;
    END
  END o_x1[167]
  PIN o_x1[168]
    DIRECTION OUTPUT ;
    USE SIGNAL ;
    PORT
      LAYER M3 ;
        RECT  49.86 25.882 49.878 25.92 ;
    END
  END o_x1[168]
  PIN o_x1[169]
    DIRECTION OUTPUT ;
    USE SIGNAL ;
    PORT
      LAYER M5 ;
        RECT  49.968 25.836 49.992 25.92 ;
    END
  END o_x1[169]
  PIN o_x1[16]
    DIRECTION OUTPUT ;
    USE SIGNAL ;
    PORT
      LAYER M3 ;
        RECT  35.748 25.882 35.766 25.92 ;
    END
  END o_x1[16]
  PIN o_x1[170]
    DIRECTION OUTPUT ;
    USE SIGNAL ;
    PORT
      LAYER M3 ;
        RECT  50.076 25.882 50.094 25.92 ;
    END
  END o_x1[170]
  PIN o_x1[171]
    DIRECTION OUTPUT ;
    USE SIGNAL ;
    PORT
      LAYER M5 ;
        RECT  50.16 25.836 50.184 25.92 ;
    END
  END o_x1[171]
  PIN o_x1[172]
    DIRECTION OUTPUT ;
    USE SIGNAL ;
    PORT
      LAYER M3 ;
        RECT  50.256 25.882 50.274 25.92 ;
    END
  END o_x1[172]
  PIN o_x1[173]
    DIRECTION OUTPUT ;
    USE SIGNAL ;
    PORT
      LAYER M5 ;
        RECT  50.352 25.836 50.376 25.92 ;
    END
  END o_x1[173]
  PIN o_x1[174]
    DIRECTION OUTPUT ;
    USE SIGNAL ;
    PORT
      LAYER M3 ;
        RECT  50.436 25.882 50.454 25.92 ;
    END
  END o_x1[174]
  PIN o_x1[175]
    DIRECTION OUTPUT ;
    USE SIGNAL ;
    PORT
      LAYER M5 ;
        RECT  50.544 25.836 50.568 25.92 ;
    END
  END o_x1[175]
  PIN o_x1[176]
    DIRECTION OUTPUT ;
    USE SIGNAL ;
    PORT
      LAYER M3 ;
        RECT  50.652 25.882 50.67 25.92 ;
    END
  END o_x1[176]
  PIN o_x1[177]
    DIRECTION OUTPUT ;
    USE SIGNAL ;
    PORT
      LAYER M5 ;
        RECT  50.736 25.836 50.76 25.92 ;
    END
  END o_x1[177]
  PIN o_x1[178]
    DIRECTION OUTPUT ;
    USE SIGNAL ;
    PORT
      LAYER M3 ;
        RECT  50.832 25.882 50.85 25.92 ;
    END
  END o_x1[178]
  PIN o_x1[179]
    DIRECTION OUTPUT ;
    USE SIGNAL ;
    PORT
      LAYER M5 ;
        RECT  50.928 25.836 50.952 25.92 ;
    END
  END o_x1[179]
  PIN o_x1[17]
    DIRECTION OUTPUT ;
    USE SIGNAL ;
    PORT
      LAYER M5 ;
        RECT  35.856 25.836 35.88 25.92 ;
    END
  END o_x1[17]
  PIN o_x1[180]
    DIRECTION OUTPUT ;
    USE SIGNAL ;
    PORT
      LAYER M3 ;
        RECT  51.012 25.882 51.03 25.92 ;
    END
  END o_x1[180]
  PIN o_x1[181]
    DIRECTION OUTPUT ;
    USE SIGNAL ;
    PORT
      LAYER M5 ;
        RECT  51.12 25.836 51.144 25.92 ;
    END
  END o_x1[181]
  PIN o_x1[182]
    DIRECTION OUTPUT ;
    USE SIGNAL ;
    PORT
      LAYER M3 ;
        RECT  51.228 25.882 51.246 25.92 ;
    END
  END o_x1[182]
  PIN o_x1[183]
    DIRECTION OUTPUT ;
    USE SIGNAL ;
    PORT
      LAYER M5 ;
        RECT  51.264 25.836 51.288 25.92 ;
    END
  END o_x1[183]
  PIN o_x1[184]
    DIRECTION OUTPUT ;
    USE SIGNAL ;
    PORT
      LAYER M3 ;
        RECT  51.372 25.882 51.39 25.92 ;
    END
  END o_x1[184]
  PIN o_x1[185]
    DIRECTION OUTPUT ;
    USE SIGNAL ;
    PORT
      LAYER M5 ;
        RECT  51.456 25.836 51.48 25.92 ;
    END
  END o_x1[185]
  PIN o_x1[186]
    DIRECTION OUTPUT ;
    USE SIGNAL ;
    PORT
      LAYER M3 ;
        RECT  51.552 25.882 51.57 25.92 ;
    END
  END o_x1[186]
  PIN o_x1[187]
    DIRECTION OUTPUT ;
    USE SIGNAL ;
    PORT
      LAYER M5 ;
        RECT  51.648 25.836 51.672 25.92 ;
    END
  END o_x1[187]
  PIN o_x1[188]
    DIRECTION OUTPUT ;
    USE SIGNAL ;
    PORT
      LAYER M3 ;
        RECT  51.732 25.882 51.75 25.92 ;
    END
  END o_x1[188]
  PIN o_x1[189]
    DIRECTION OUTPUT ;
    USE SIGNAL ;
    PORT
      LAYER M5 ;
        RECT  51.84 25.836 51.864 25.92 ;
    END
  END o_x1[189]
  PIN o_x1[18]
    DIRECTION OUTPUT ;
    USE SIGNAL ;
    PORT
      LAYER M3 ;
        RECT  35.964 25.882 35.982 25.92 ;
    END
  END o_x1[18]
  PIN o_x1[190]
    DIRECTION OUTPUT ;
    USE SIGNAL ;
    PORT
      LAYER M3 ;
        RECT  51.948 25.882 51.966 25.92 ;
    END
  END o_x1[190]
  PIN o_x1[191]
    DIRECTION OUTPUT ;
    USE SIGNAL ;
    PORT
      LAYER M5 ;
        RECT  52.032 25.836 52.056 25.92 ;
    END
  END o_x1[191]
  PIN o_x1[192]
    DIRECTION OUTPUT ;
    USE SIGNAL ;
    PORT
      LAYER M3 ;
        RECT  52.128 25.882 52.146 25.92 ;
    END
  END o_x1[192]
  PIN o_x1[193]
    DIRECTION OUTPUT ;
    USE SIGNAL ;
    PORT
      LAYER M5 ;
        RECT  52.224 25.836 52.248 25.92 ;
    END
  END o_x1[193]
  PIN o_x1[194]
    DIRECTION OUTPUT ;
    USE SIGNAL ;
    PORT
      LAYER M3 ;
        RECT  52.308 25.882 52.326 25.92 ;
    END
  END o_x1[194]
  PIN o_x1[195]
    DIRECTION OUTPUT ;
    USE SIGNAL ;
    PORT
      LAYER M5 ;
        RECT  52.416 25.836 52.44 25.92 ;
    END
  END o_x1[195]
  PIN o_x1[196]
    DIRECTION OUTPUT ;
    USE SIGNAL ;
    PORT
      LAYER M3 ;
        RECT  52.524 25.882 52.542 25.92 ;
    END
  END o_x1[196]
  PIN o_x1[197]
    DIRECTION OUTPUT ;
    USE SIGNAL ;
    PORT
      LAYER M5 ;
        RECT  52.608 25.836 52.632 25.92 ;
    END
  END o_x1[197]
  PIN o_x1[198]
    DIRECTION OUTPUT ;
    USE SIGNAL ;
    PORT
      LAYER M3 ;
        RECT  52.704 25.882 52.722 25.92 ;
    END
  END o_x1[198]
  PIN o_x1[199]
    DIRECTION OUTPUT ;
    USE SIGNAL ;
    PORT
      LAYER M5 ;
        RECT  52.752 25.836 52.776 25.92 ;
    END
  END o_x1[199]
  PIN o_x1[19]
    DIRECTION OUTPUT ;
    USE SIGNAL ;
    PORT
      LAYER M5 ;
        RECT  36.048 25.836 36.072 25.92 ;
    END
  END o_x1[19]
  PIN o_x1[1]
    DIRECTION OUTPUT ;
    USE SIGNAL ;
    PORT
      LAYER M5 ;
        RECT  34.368 25.836 34.392 25.92 ;
    END
  END o_x1[1]
  PIN o_x1[200]
    DIRECTION OUTPUT ;
    USE SIGNAL ;
    PORT
      LAYER M3 ;
        RECT  52.848 25.882 52.866 25.92 ;
    END
  END o_x1[200]
  PIN o_x1[201]
    DIRECTION OUTPUT ;
    USE SIGNAL ;
    PORT
      LAYER M5 ;
        RECT  52.944 25.836 52.968 25.92 ;
    END
  END o_x1[201]
  PIN o_x1[202]
    DIRECTION OUTPUT ;
    USE SIGNAL ;
    PORT
      LAYER M3 ;
        RECT  53.028 25.882 53.046 25.92 ;
    END
  END o_x1[202]
  PIN o_x1[203]
    DIRECTION OUTPUT ;
    USE SIGNAL ;
    PORT
      LAYER M5 ;
        RECT  53.136 25.836 53.16 25.92 ;
    END
  END o_x1[203]
  PIN o_x1[204]
    DIRECTION OUTPUT ;
    USE SIGNAL ;
    PORT
      LAYER M3 ;
        RECT  53.244 25.882 53.262 25.92 ;
    END
  END o_x1[204]
  PIN o_x1[205]
    DIRECTION OUTPUT ;
    USE SIGNAL ;
    PORT
      LAYER M5 ;
        RECT  53.328 25.836 53.352 25.92 ;
    END
  END o_x1[205]
  PIN o_x1[206]
    DIRECTION OUTPUT ;
    USE SIGNAL ;
    PORT
      LAYER M3 ;
        RECT  53.424 25.882 53.442 25.92 ;
    END
  END o_x1[206]
  PIN o_x1[207]
    DIRECTION OUTPUT ;
    USE SIGNAL ;
    PORT
      LAYER M5 ;
        RECT  53.52 25.836 53.544 25.92 ;
    END
  END o_x1[207]
  PIN o_x1[208]
    DIRECTION OUTPUT ;
    USE SIGNAL ;
    PORT
      LAYER M3 ;
        RECT  53.604 25.882 53.622 25.92 ;
    END
  END o_x1[208]
  PIN o_x1[209]
    DIRECTION OUTPUT ;
    USE SIGNAL ;
    PORT
      LAYER M5 ;
        RECT  53.712 25.836 53.736 25.92 ;
    END
  END o_x1[209]
  PIN o_x1[20]
    DIRECTION OUTPUT ;
    USE SIGNAL ;
    PORT
      LAYER M3 ;
        RECT  36.144 25.882 36.162 25.92 ;
    END
  END o_x1[20]
  PIN o_x1[210]
    DIRECTION OUTPUT ;
    USE SIGNAL ;
    PORT
      LAYER M3 ;
        RECT  53.82 25.882 53.838 25.92 ;
    END
  END o_x1[210]
  PIN o_x1[211]
    DIRECTION OUTPUT ;
    USE SIGNAL ;
    PORT
      LAYER M5 ;
        RECT  53.904 25.836 53.928 25.92 ;
    END
  END o_x1[211]
  PIN o_x1[212]
    DIRECTION OUTPUT ;
    USE SIGNAL ;
    PORT
      LAYER M3 ;
        RECT  54 25.882 54.018 25.92 ;
    END
  END o_x1[212]
  PIN o_x1[213]
    DIRECTION OUTPUT ;
    USE SIGNAL ;
    PORT
      LAYER M5 ;
        RECT  54.096 25.836 54.12 25.92 ;
    END
  END o_x1[213]
  PIN o_x1[214]
    DIRECTION OUTPUT ;
    USE SIGNAL ;
    PORT
      LAYER M3 ;
        RECT  54.18 25.882 54.198 25.92 ;
    END
  END o_x1[214]
  PIN o_x1[215]
    DIRECTION OUTPUT ;
    USE SIGNAL ;
    PORT
      LAYER M5 ;
        RECT  54.24 25.836 54.264 25.92 ;
    END
  END o_x1[215]
  PIN o_x1[216]
    DIRECTION OUTPUT ;
    USE SIGNAL ;
    PORT
      LAYER M3 ;
        RECT  54.324 25.882 54.342 25.92 ;
    END
  END o_x1[216]
  PIN o_x1[217]
    DIRECTION OUTPUT ;
    USE SIGNAL ;
    PORT
      LAYER M5 ;
        RECT  54.432 25.836 54.456 25.92 ;
    END
  END o_x1[217]
  PIN o_x1[218]
    DIRECTION OUTPUT ;
    USE SIGNAL ;
    PORT
      LAYER M3 ;
        RECT  54.54 25.882 54.558 25.92 ;
    END
  END o_x1[218]
  PIN o_x1[219]
    DIRECTION OUTPUT ;
    USE SIGNAL ;
    PORT
      LAYER M5 ;
        RECT  54.624 25.836 54.648 25.92 ;
    END
  END o_x1[219]
  PIN o_x1[21]
    DIRECTION OUTPUT ;
    USE SIGNAL ;
    PORT
      LAYER M5 ;
        RECT  36.24 25.836 36.264 25.92 ;
    END
  END o_x1[21]
  PIN o_x1[220]
    DIRECTION OUTPUT ;
    USE SIGNAL ;
    PORT
      LAYER M3 ;
        RECT  54.72 25.882 54.738 25.92 ;
    END
  END o_x1[220]
  PIN o_x1[221]
    DIRECTION OUTPUT ;
    USE SIGNAL ;
    PORT
      LAYER M5 ;
        RECT  54.816 25.836 54.84 25.92 ;
    END
  END o_x1[221]
  PIN o_x1[222]
    DIRECTION OUTPUT ;
    USE SIGNAL ;
    PORT
      LAYER M3 ;
        RECT  54.9 25.882 54.918 25.92 ;
    END
  END o_x1[222]
  PIN o_x1[223]
    DIRECTION OUTPUT ;
    USE SIGNAL ;
    PORT
      LAYER M5 ;
        RECT  55.008 25.836 55.032 25.92 ;
    END
  END o_x1[223]
  PIN o_x1[224]
    DIRECTION OUTPUT ;
    USE SIGNAL ;
    PORT
      LAYER M3 ;
        RECT  55.116 25.882 55.134 25.92 ;
    END
  END o_x1[224]
  PIN o_x1[225]
    DIRECTION OUTPUT ;
    USE SIGNAL ;
    PORT
      LAYER M5 ;
        RECT  55.2 25.836 55.224 25.92 ;
    END
  END o_x1[225]
  PIN o_x1[226]
    DIRECTION OUTPUT ;
    USE SIGNAL ;
    PORT
      LAYER M3 ;
        RECT  55.296 25.882 55.314 25.92 ;
    END
  END o_x1[226]
  PIN o_x1[227]
    DIRECTION OUTPUT ;
    USE SIGNAL ;
    PORT
      LAYER M5 ;
        RECT  55.392 25.836 55.416 25.92 ;
    END
  END o_x1[227]
  PIN o_x1[228]
    DIRECTION OUTPUT ;
    USE SIGNAL ;
    PORT
      LAYER M3 ;
        RECT  55.476 25.882 55.494 25.92 ;
    END
  END o_x1[228]
  PIN o_x1[229]
    DIRECTION OUTPUT ;
    USE SIGNAL ;
    PORT
      LAYER M5 ;
        RECT  55.584 25.836 55.608 25.92 ;
    END
  END o_x1[229]
  PIN o_x1[22]
    DIRECTION OUTPUT ;
    USE SIGNAL ;
    PORT
      LAYER M3 ;
        RECT  36.324 25.882 36.342 25.92 ;
    END
  END o_x1[22]
  PIN o_x1[230]
    DIRECTION OUTPUT ;
    USE SIGNAL ;
    PORT
      LAYER M3 ;
        RECT  55.692 25.882 55.71 25.92 ;
    END
  END o_x1[230]
  PIN o_x1[231]
    DIRECTION OUTPUT ;
    USE SIGNAL ;
    PORT
      LAYER M5 ;
        RECT  55.728 25.836 55.752 25.92 ;
    END
  END o_x1[231]
  PIN o_x1[232]
    DIRECTION OUTPUT ;
    USE SIGNAL ;
    PORT
      LAYER M3 ;
        RECT  55.836 25.882 55.854 25.92 ;
    END
  END o_x1[232]
  PIN o_x1[233]
    DIRECTION OUTPUT ;
    USE SIGNAL ;
    PORT
      LAYER M5 ;
        RECT  55.92 25.836 55.944 25.92 ;
    END
  END o_x1[233]
  PIN o_x1[234]
    DIRECTION OUTPUT ;
    USE SIGNAL ;
    PORT
      LAYER M3 ;
        RECT  56.016 25.882 56.034 25.92 ;
    END
  END o_x1[234]
  PIN o_x1[235]
    DIRECTION OUTPUT ;
    USE SIGNAL ;
    PORT
      LAYER M5 ;
        RECT  56.112 25.836 56.136 25.92 ;
    END
  END o_x1[235]
  PIN o_x1[236]
    DIRECTION OUTPUT ;
    USE SIGNAL ;
    PORT
      LAYER M3 ;
        RECT  56.196 25.882 56.214 25.92 ;
    END
  END o_x1[236]
  PIN o_x1[237]
    DIRECTION OUTPUT ;
    USE SIGNAL ;
    PORT
      LAYER M5 ;
        RECT  56.304 25.836 56.328 25.92 ;
    END
  END o_x1[237]
  PIN o_x1[238]
    DIRECTION OUTPUT ;
    USE SIGNAL ;
    PORT
      LAYER M3 ;
        RECT  56.412 25.882 56.43 25.92 ;
    END
  END o_x1[238]
  PIN o_x1[239]
    DIRECTION OUTPUT ;
    USE SIGNAL ;
    PORT
      LAYER M5 ;
        RECT  56.496 25.836 56.52 25.92 ;
    END
  END o_x1[239]
  PIN o_x1[23]
    DIRECTION OUTPUT ;
    USE SIGNAL ;
    PORT
      LAYER M5 ;
        RECT  36.432 25.836 36.456 25.92 ;
    END
  END o_x1[23]
  PIN o_x1[240]
    DIRECTION OUTPUT ;
    USE SIGNAL ;
    PORT
      LAYER M3 ;
        RECT  56.592 25.882 56.61 25.92 ;
    END
  END o_x1[240]
  PIN o_x1[241]
    DIRECTION OUTPUT ;
    USE SIGNAL ;
    PORT
      LAYER M5 ;
        RECT  56.688 25.836 56.712 25.92 ;
    END
  END o_x1[241]
  PIN o_x1[242]
    DIRECTION OUTPUT ;
    USE SIGNAL ;
    PORT
      LAYER M3 ;
        RECT  56.772 25.882 56.79 25.92 ;
    END
  END o_x1[242]
  PIN o_x1[243]
    DIRECTION OUTPUT ;
    USE SIGNAL ;
    PORT
      LAYER M5 ;
        RECT  56.88 25.836 56.904 25.92 ;
    END
  END o_x1[243]
  PIN o_x1[244]
    DIRECTION OUTPUT ;
    USE SIGNAL ;
    PORT
      LAYER M3 ;
        RECT  56.988 25.882 57.006 25.92 ;
    END
  END o_x1[244]
  PIN o_x1[245]
    DIRECTION OUTPUT ;
    USE SIGNAL ;
    PORT
      LAYER M5 ;
        RECT  57.072 25.836 57.096 25.92 ;
    END
  END o_x1[245]
  PIN o_x1[246]
    DIRECTION OUTPUT ;
    USE SIGNAL ;
    PORT
      LAYER M3 ;
        RECT  57.168 25.882 57.186 25.92 ;
    END
  END o_x1[246]
  PIN o_x1[247]
    DIRECTION OUTPUT ;
    USE SIGNAL ;
    PORT
      LAYER M5 ;
        RECT  57.216 25.836 57.24 25.92 ;
    END
  END o_x1[247]
  PIN o_x1[248]
    DIRECTION OUTPUT ;
    USE SIGNAL ;
    PORT
      LAYER M3 ;
        RECT  57.312 25.882 57.33 25.92 ;
    END
  END o_x1[248]
  PIN o_x1[249]
    DIRECTION OUTPUT ;
    USE SIGNAL ;
    PORT
      LAYER M5 ;
        RECT  57.408 25.836 57.432 25.92 ;
    END
  END o_x1[249]
  PIN o_x1[24]
    DIRECTION OUTPUT ;
    USE SIGNAL ;
    PORT
      LAYER M3 ;
        RECT  36.54 25.882 36.558 25.92 ;
    END
  END o_x1[24]
  PIN o_x1[250]
    DIRECTION OUTPUT ;
    USE SIGNAL ;
    PORT
      LAYER M3 ;
        RECT  57.492 25.882 57.51 25.92 ;
    END
  END o_x1[250]
  PIN o_x1[251]
    DIRECTION OUTPUT ;
    USE SIGNAL ;
    PORT
      LAYER M5 ;
        RECT  57.6 25.836 57.624 25.92 ;
    END
  END o_x1[251]
  PIN o_x1[252]
    DIRECTION OUTPUT ;
    USE SIGNAL ;
    PORT
      LAYER M3 ;
        RECT  57.708 25.882 57.726 25.92 ;
    END
  END o_x1[252]
  PIN o_x1[253]
    DIRECTION OUTPUT ;
    USE SIGNAL ;
    PORT
      LAYER M5 ;
        RECT  57.792 25.836 57.816 25.92 ;
    END
  END o_x1[253]
  PIN o_x1[254]
    DIRECTION OUTPUT ;
    USE SIGNAL ;
    PORT
      LAYER M3 ;
        RECT  57.888 25.882 57.906 25.92 ;
    END
  END o_x1[254]
  PIN o_x1[255]
    DIRECTION OUTPUT ;
    USE SIGNAL ;
    PORT
      LAYER M5 ;
        RECT  57.984 25.836 58.008 25.92 ;
    END
  END o_x1[255]
  PIN o_x1[256]
    DIRECTION OUTPUT ;
    USE SIGNAL ;
    PORT
      LAYER M5 ;
        RECT  8.496 25.836 8.52 25.92 ;
    END
  END o_x1[256]
  PIN o_x1[257]
    DIRECTION OUTPUT ;
    USE SIGNAL ;
    PORT
      LAYER M3 ;
        RECT  8.604 25.882 8.622 25.92 ;
    END
  END o_x1[257]
  PIN o_x1[258]
    DIRECTION OUTPUT ;
    USE SIGNAL ;
    PORT
      LAYER M5 ;
        RECT  8.688 25.836 8.712 25.92 ;
    END
  END o_x1[258]
  PIN o_x1[259]
    DIRECTION OUTPUT ;
    USE SIGNAL ;
    PORT
      LAYER M3 ;
        RECT  8.784 25.882 8.802 25.92 ;
    END
  END o_x1[259]
  PIN o_x1[25]
    DIRECTION OUTPUT ;
    USE SIGNAL ;
    PORT
      LAYER M5 ;
        RECT  36.576 25.836 36.6 25.92 ;
    END
  END o_x1[25]
  PIN o_x1[260]
    DIRECTION OUTPUT ;
    USE SIGNAL ;
    PORT
      LAYER M5 ;
        RECT  8.88 25.836 8.904 25.92 ;
    END
  END o_x1[260]
  PIN o_x1[261]
    DIRECTION OUTPUT ;
    USE SIGNAL ;
    PORT
      LAYER M3 ;
        RECT  8.964 25.882 8.982 25.92 ;
    END
  END o_x1[261]
  PIN o_x1[262]
    DIRECTION OUTPUT ;
    USE SIGNAL ;
    PORT
      LAYER M5 ;
        RECT  9.072 25.836 9.096 25.92 ;
    END
  END o_x1[262]
  PIN o_x1[263]
    DIRECTION OUTPUT ;
    USE SIGNAL ;
    PORT
      LAYER M3 ;
        RECT  9.18 25.882 9.198 25.92 ;
    END
  END o_x1[263]
  PIN o_x1[264]
    DIRECTION OUTPUT ;
    USE SIGNAL ;
    PORT
      LAYER M5 ;
        RECT  9.264 25.836 9.288 25.92 ;
    END
  END o_x1[264]
  PIN o_x1[265]
    DIRECTION OUTPUT ;
    USE SIGNAL ;
    PORT
      LAYER M3 ;
        RECT  9.36 25.882 9.378 25.92 ;
    END
  END o_x1[265]
  PIN o_x1[26]
    DIRECTION OUTPUT ;
    USE SIGNAL ;
    PORT
      LAYER M3 ;
        RECT  36.684 25.882 36.702 25.92 ;
    END
  END o_x1[26]
  PIN o_x1[27]
    DIRECTION OUTPUT ;
    USE SIGNAL ;
    PORT
      LAYER M5 ;
        RECT  36.768 25.836 36.792 25.92 ;
    END
  END o_x1[27]
  PIN o_x1[28]
    DIRECTION OUTPUT ;
    USE SIGNAL ;
    PORT
      LAYER M3 ;
        RECT  36.864 25.882 36.882 25.92 ;
    END
  END o_x1[28]
  PIN o_x1[29]
    DIRECTION OUTPUT ;
    USE SIGNAL ;
    PORT
      LAYER M5 ;
        RECT  36.96 25.836 36.984 25.92 ;
    END
  END o_x1[29]
  PIN o_x1[2]
    DIRECTION OUTPUT ;
    USE SIGNAL ;
    PORT
      LAYER M3 ;
        RECT  34.452 25.882 34.47 25.92 ;
    END
  END o_x1[2]
  PIN o_x1[30]
    DIRECTION OUTPUT ;
    USE SIGNAL ;
    PORT
      LAYER M3 ;
        RECT  37.044 25.882 37.062 25.92 ;
    END
  END o_x1[30]
  PIN o_x1[31]
    DIRECTION OUTPUT ;
    USE SIGNAL ;
    PORT
      LAYER M5 ;
        RECT  37.152 25.836 37.176 25.92 ;
    END
  END o_x1[31]
  PIN o_x1[32]
    DIRECTION OUTPUT ;
    USE SIGNAL ;
    PORT
      LAYER M3 ;
        RECT  37.26 25.882 37.278 25.92 ;
    END
  END o_x1[32]
  PIN o_x1[33]
    DIRECTION OUTPUT ;
    USE SIGNAL ;
    PORT
      LAYER M5 ;
        RECT  37.344 25.836 37.368 25.92 ;
    END
  END o_x1[33]
  PIN o_x1[34]
    DIRECTION OUTPUT ;
    USE SIGNAL ;
    PORT
      LAYER M3 ;
        RECT  37.44 25.882 37.458 25.92 ;
    END
  END o_x1[34]
  PIN o_x1[35]
    DIRECTION OUTPUT ;
    USE SIGNAL ;
    PORT
      LAYER M5 ;
        RECT  37.536 25.836 37.56 25.92 ;
    END
  END o_x1[35]
  PIN o_x1[36]
    DIRECTION OUTPUT ;
    USE SIGNAL ;
    PORT
      LAYER M3 ;
        RECT  37.62 25.882 37.638 25.92 ;
    END
  END o_x1[36]
  PIN o_x1[37]
    DIRECTION OUTPUT ;
    USE SIGNAL ;
    PORT
      LAYER M5 ;
        RECT  37.728 25.836 37.752 25.92 ;
    END
  END o_x1[37]
  PIN o_x1[38]
    DIRECTION OUTPUT ;
    USE SIGNAL ;
    PORT
      LAYER M3 ;
        RECT  37.836 25.882 37.854 25.92 ;
    END
  END o_x1[38]
  PIN o_x1[39]
    DIRECTION OUTPUT ;
    USE SIGNAL ;
    PORT
      LAYER M5 ;
        RECT  37.92 25.836 37.944 25.92 ;
    END
  END o_x1[39]
  PIN o_x1[3]
    DIRECTION OUTPUT ;
    USE SIGNAL ;
    PORT
      LAYER M5 ;
        RECT  34.56 25.836 34.584 25.92 ;
    END
  END o_x1[3]
  PIN o_x1[40]
    DIRECTION OUTPUT ;
    USE SIGNAL ;
    PORT
      LAYER M3 ;
        RECT  37.98 25.882 37.998 25.92 ;
    END
  END o_x1[40]
  PIN o_x1[41]
    DIRECTION OUTPUT ;
    USE SIGNAL ;
    PORT
      LAYER M5 ;
        RECT  38.064 25.836 38.088 25.92 ;
    END
  END o_x1[41]
  PIN o_x1[42]
    DIRECTION OUTPUT ;
    USE SIGNAL ;
    PORT
      LAYER M3 ;
        RECT  38.16 25.882 38.178 25.92 ;
    END
  END o_x1[42]
  PIN o_x1[43]
    DIRECTION OUTPUT ;
    USE SIGNAL ;
    PORT
      LAYER M5 ;
        RECT  38.256 25.836 38.28 25.92 ;
    END
  END o_x1[43]
  PIN o_x1[44]
    DIRECTION OUTPUT ;
    USE SIGNAL ;
    PORT
      LAYER M3 ;
        RECT  38.34 25.882 38.358 25.92 ;
    END
  END o_x1[44]
  PIN o_x1[45]
    DIRECTION OUTPUT ;
    USE SIGNAL ;
    PORT
      LAYER M5 ;
        RECT  38.448 25.836 38.472 25.92 ;
    END
  END o_x1[45]
  PIN o_x1[46]
    DIRECTION OUTPUT ;
    USE SIGNAL ;
    PORT
      LAYER M3 ;
        RECT  38.556 25.882 38.574 25.92 ;
    END
  END o_x1[46]
  PIN o_x1[47]
    DIRECTION OUTPUT ;
    USE SIGNAL ;
    PORT
      LAYER M5 ;
        RECT  38.64 25.836 38.664 25.92 ;
    END
  END o_x1[47]
  PIN o_x1[48]
    DIRECTION OUTPUT ;
    USE SIGNAL ;
    PORT
      LAYER M3 ;
        RECT  38.736 25.882 38.754 25.92 ;
    END
  END o_x1[48]
  PIN o_x1[49]
    DIRECTION OUTPUT ;
    USE SIGNAL ;
    PORT
      LAYER M5 ;
        RECT  38.832 25.836 38.856 25.92 ;
    END
  END o_x1[49]
  PIN o_x1[4]
    DIRECTION OUTPUT ;
    USE SIGNAL ;
    PORT
      LAYER M3 ;
        RECT  34.668 25.882 34.686 25.92 ;
    END
  END o_x1[4]
  PIN o_x1[50]
    DIRECTION OUTPUT ;
    USE SIGNAL ;
    PORT
      LAYER M3 ;
        RECT  38.916 25.882 38.934 25.92 ;
    END
  END o_x1[50]
  PIN o_x1[51]
    DIRECTION OUTPUT ;
    USE SIGNAL ;
    PORT
      LAYER M5 ;
        RECT  39.024 25.836 39.048 25.92 ;
    END
  END o_x1[51]
  PIN o_x1[52]
    DIRECTION OUTPUT ;
    USE SIGNAL ;
    PORT
      LAYER M3 ;
        RECT  39.132 25.882 39.15 25.92 ;
    END
  END o_x1[52]
  PIN o_x1[53]
    DIRECTION OUTPUT ;
    USE SIGNAL ;
    PORT
      LAYER M5 ;
        RECT  39.216 25.836 39.24 25.92 ;
    END
  END o_x1[53]
  PIN o_x1[54]
    DIRECTION OUTPUT ;
    USE SIGNAL ;
    PORT
      LAYER M3 ;
        RECT  39.312 25.882 39.33 25.92 ;
    END
  END o_x1[54]
  PIN o_x1[55]
    DIRECTION OUTPUT ;
    USE SIGNAL ;
    PORT
      LAYER M5 ;
        RECT  39.408 25.836 39.432 25.92 ;
    END
  END o_x1[55]
  PIN o_x1[56]
    DIRECTION OUTPUT ;
    USE SIGNAL ;
    PORT
      LAYER M3 ;
        RECT  39.456 25.882 39.474 25.92 ;
    END
  END o_x1[56]
  PIN o_x1[57]
    DIRECTION OUTPUT ;
    USE SIGNAL ;
    PORT
      LAYER M5 ;
        RECT  39.552 25.836 39.576 25.92 ;
    END
  END o_x1[57]
  PIN o_x1[58]
    DIRECTION OUTPUT ;
    USE SIGNAL ;
    PORT
      LAYER M3 ;
        RECT  39.636 25.882 39.654 25.92 ;
    END
  END o_x1[58]
  PIN o_x1[59]
    DIRECTION OUTPUT ;
    USE SIGNAL ;
    PORT
      LAYER M5 ;
        RECT  39.744 25.836 39.768 25.92 ;
    END
  END o_x1[59]
  PIN o_x1[5]
    DIRECTION OUTPUT ;
    USE SIGNAL ;
    PORT
      LAYER M5 ;
        RECT  34.752 25.836 34.776 25.92 ;
    END
  END o_x1[5]
  PIN o_x1[60]
    DIRECTION OUTPUT ;
    USE SIGNAL ;
    PORT
      LAYER M3 ;
        RECT  39.852 25.882 39.87 25.92 ;
    END
  END o_x1[60]
  PIN o_x1[61]
    DIRECTION OUTPUT ;
    USE SIGNAL ;
    PORT
      LAYER M5 ;
        RECT  39.936 25.836 39.96 25.92 ;
    END
  END o_x1[61]
  PIN o_x1[62]
    DIRECTION OUTPUT ;
    USE SIGNAL ;
    PORT
      LAYER M3 ;
        RECT  40.032 25.882 40.05 25.92 ;
    END
  END o_x1[62]
  PIN o_x1[63]
    DIRECTION OUTPUT ;
    USE SIGNAL ;
    PORT
      LAYER M5 ;
        RECT  40.128 25.836 40.152 25.92 ;
    END
  END o_x1[63]
  PIN o_x1[64]
    DIRECTION OUTPUT ;
    USE SIGNAL ;
    PORT
      LAYER M3 ;
        RECT  40.212 25.882 40.23 25.92 ;
    END
  END o_x1[64]
  PIN o_x1[65]
    DIRECTION OUTPUT ;
    USE SIGNAL ;
    PORT
      LAYER M5 ;
        RECT  40.32 25.836 40.344 25.92 ;
    END
  END o_x1[65]
  PIN o_x1[66]
    DIRECTION OUTPUT ;
    USE SIGNAL ;
    PORT
      LAYER M3 ;
        RECT  40.428 25.882 40.446 25.92 ;
    END
  END o_x1[66]
  PIN o_x1[67]
    DIRECTION OUTPUT ;
    USE SIGNAL ;
    PORT
      LAYER M5 ;
        RECT  40.512 25.836 40.536 25.92 ;
    END
  END o_x1[67]
  PIN o_x1[68]
    DIRECTION OUTPUT ;
    USE SIGNAL ;
    PORT
      LAYER M3 ;
        RECT  40.608 25.882 40.626 25.92 ;
    END
  END o_x1[68]
  PIN o_x1[69]
    DIRECTION OUTPUT ;
    USE SIGNAL ;
    PORT
      LAYER M5 ;
        RECT  40.704 25.836 40.728 25.92 ;
    END
  END o_x1[69]
  PIN o_x1[6]
    DIRECTION OUTPUT ;
    USE SIGNAL ;
    PORT
      LAYER M3 ;
        RECT  34.848 25.882 34.866 25.92 ;
    END
  END o_x1[6]
  PIN o_x1[70]
    DIRECTION OUTPUT ;
    USE SIGNAL ;
    PORT
      LAYER M3 ;
        RECT  40.788 25.882 40.806 25.92 ;
    END
  END o_x1[70]
  PIN o_x1[71]
    DIRECTION OUTPUT ;
    USE SIGNAL ;
    PORT
      LAYER M5 ;
        RECT  40.896 25.836 40.92 25.92 ;
    END
  END o_x1[71]
  PIN o_x1[72]
    DIRECTION OUTPUT ;
    USE SIGNAL ;
    PORT
      LAYER M3 ;
        RECT  40.932 25.882 40.95 25.92 ;
    END
  END o_x1[72]
  PIN o_x1[73]
    DIRECTION OUTPUT ;
    USE SIGNAL ;
    PORT
      LAYER M5 ;
        RECT  41.04 25.836 41.064 25.92 ;
    END
  END o_x1[73]
  PIN o_x1[74]
    DIRECTION OUTPUT ;
    USE SIGNAL ;
    PORT
      LAYER M3 ;
        RECT  41.148 25.882 41.166 25.92 ;
    END
  END o_x1[74]
  PIN o_x1[75]
    DIRECTION OUTPUT ;
    USE SIGNAL ;
    PORT
      LAYER M5 ;
        RECT  41.232 25.836 41.256 25.92 ;
    END
  END o_x1[75]
  PIN o_x1[76]
    DIRECTION OUTPUT ;
    USE SIGNAL ;
    PORT
      LAYER M3 ;
        RECT  41.328 25.882 41.346 25.92 ;
    END
  END o_x1[76]
  PIN o_x1[77]
    DIRECTION OUTPUT ;
    USE SIGNAL ;
    PORT
      LAYER M5 ;
        RECT  41.424 25.836 41.448 25.92 ;
    END
  END o_x1[77]
  PIN o_x1[78]
    DIRECTION OUTPUT ;
    USE SIGNAL ;
    PORT
      LAYER M3 ;
        RECT  41.508 25.882 41.526 25.92 ;
    END
  END o_x1[78]
  PIN o_x1[79]
    DIRECTION OUTPUT ;
    USE SIGNAL ;
    PORT
      LAYER M5 ;
        RECT  41.616 25.836 41.64 25.92 ;
    END
  END o_x1[79]
  PIN o_x1[7]
    DIRECTION OUTPUT ;
    USE SIGNAL ;
    PORT
      LAYER M5 ;
        RECT  34.944 25.836 34.968 25.92 ;
    END
  END o_x1[7]
  PIN o_x1[80]
    DIRECTION OUTPUT ;
    USE SIGNAL ;
    PORT
      LAYER M3 ;
        RECT  41.724 25.882 41.742 25.92 ;
    END
  END o_x1[80]
  PIN o_x1[81]
    DIRECTION OUTPUT ;
    USE SIGNAL ;
    PORT
      LAYER M5 ;
        RECT  41.808 25.836 41.832 25.92 ;
    END
  END o_x1[81]
  PIN o_x1[82]
    DIRECTION OUTPUT ;
    USE SIGNAL ;
    PORT
      LAYER M3 ;
        RECT  41.904 25.882 41.922 25.92 ;
    END
  END o_x1[82]
  PIN o_x1[83]
    DIRECTION OUTPUT ;
    USE SIGNAL ;
    PORT
      LAYER M5 ;
        RECT  42 25.836 42.024 25.92 ;
    END
  END o_x1[83]
  PIN o_x1[84]
    DIRECTION OUTPUT ;
    USE SIGNAL ;
    PORT
      LAYER M3 ;
        RECT  42.084 25.882 42.102 25.92 ;
    END
  END o_x1[84]
  PIN o_x1[85]
    DIRECTION OUTPUT ;
    USE SIGNAL ;
    PORT
      LAYER M5 ;
        RECT  42.192 25.836 42.216 25.92 ;
    END
  END o_x1[85]
  PIN o_x1[86]
    DIRECTION OUTPUT ;
    USE SIGNAL ;
    PORT
      LAYER M3 ;
        RECT  42.3 25.882 42.318 25.92 ;
    END
  END o_x1[86]
  PIN o_x1[87]
    DIRECTION OUTPUT ;
    USE SIGNAL ;
    PORT
      LAYER M5 ;
        RECT  42.384 25.836 42.408 25.92 ;
    END
  END o_x1[87]
  PIN o_x1[88]
    DIRECTION OUTPUT ;
    USE SIGNAL ;
    PORT
      LAYER M3 ;
        RECT  42.444 25.882 42.462 25.92 ;
    END
  END o_x1[88]
  PIN o_x1[89]
    DIRECTION OUTPUT ;
    USE SIGNAL ;
    PORT
      LAYER M5 ;
        RECT  42.528 25.836 42.552 25.92 ;
    END
  END o_x1[89]
  PIN o_x1[8]
    DIRECTION OUTPUT ;
    USE SIGNAL ;
    PORT
      LAYER M3 ;
        RECT  35.028 25.882 35.046 25.92 ;
    END
  END o_x1[8]
  PIN o_x1[90]
    DIRECTION OUTPUT ;
    USE SIGNAL ;
    PORT
      LAYER M3 ;
        RECT  42.624 25.882 42.642 25.92 ;
    END
  END o_x1[90]
  PIN o_x1[91]
    DIRECTION OUTPUT ;
    USE SIGNAL ;
    PORT
      LAYER M5 ;
        RECT  42.72 25.836 42.744 25.92 ;
    END
  END o_x1[91]
  PIN o_x1[92]
    DIRECTION OUTPUT ;
    USE SIGNAL ;
    PORT
      LAYER M3 ;
        RECT  42.804 25.882 42.822 25.92 ;
    END
  END o_x1[92]
  PIN o_x1[93]
    DIRECTION OUTPUT ;
    USE SIGNAL ;
    PORT
      LAYER M5 ;
        RECT  42.912 25.836 42.936 25.92 ;
    END
  END o_x1[93]
  PIN o_x1[94]
    DIRECTION OUTPUT ;
    USE SIGNAL ;
    PORT
      LAYER M3 ;
        RECT  43.02 25.882 43.038 25.92 ;
    END
  END o_x1[94]
  PIN o_x1[95]
    DIRECTION OUTPUT ;
    USE SIGNAL ;
    PORT
      LAYER M5 ;
        RECT  43.104 25.836 43.128 25.92 ;
    END
  END o_x1[95]
  PIN o_x1[96]
    DIRECTION OUTPUT ;
    USE SIGNAL ;
    PORT
      LAYER M3 ;
        RECT  43.2 25.882 43.218 25.92 ;
    END
  END o_x1[96]
  PIN o_x1[97]
    DIRECTION OUTPUT ;
    USE SIGNAL ;
    PORT
      LAYER M5 ;
        RECT  43.296 25.836 43.32 25.92 ;
    END
  END o_x1[97]
  PIN o_x1[98]
    DIRECTION OUTPUT ;
    USE SIGNAL ;
    PORT
      LAYER M3 ;
        RECT  43.38 25.882 43.398 25.92 ;
    END
  END o_x1[98]
  PIN o_x1[99]
    DIRECTION OUTPUT ;
    USE SIGNAL ;
    PORT
      LAYER M5 ;
        RECT  43.488 25.836 43.512 25.92 ;
    END
  END o_x1[99]
  PIN o_x1[9]
    DIRECTION OUTPUT ;
    USE SIGNAL ;
    PORT
      LAYER M5 ;
        RECT  35.088 25.836 35.112 25.92 ;
    END
  END o_x1[9]
  PIN rs[0]
    DIRECTION INPUT ;
    USE SIGNAL ;
    PORT
      LAYER M3 ;
        RECT  30.348 0 30.366 0.038 ;
    END
  END rs[0]
  PIN VDD
    DIRECTION INOUT ;
    USE POWER ;
    PORT
      LAYER M5 ;
        RECT  56.592 2.151 56.712 23.769 ;
        RECT  53.892 2.151 54.012 23.769 ;
        RECT  51.192 2.151 51.312 23.769 ;
        RECT  48.492 2.151 48.612 23.769 ;
        RECT  45.792 2.151 45.912 23.769 ;
        RECT  43.092 2.151 43.212 23.769 ;
        RECT  40.392 2.151 40.512 23.769 ;
        RECT  37.692 2.151 37.812 23.769 ;
        RECT  34.992 2.151 35.112 23.769 ;
        RECT  32.292 2.151 32.412 23.769 ;
        RECT  29.592 2.151 29.712 23.769 ;
        RECT  26.892 2.151 27.012 23.769 ;
        RECT  24.192 2.151 24.312 23.769 ;
        RECT  21.492 2.151 21.612 23.769 ;
        RECT  18.792 2.151 18.912 23.769 ;
        RECT  16.092 2.151 16.212 23.769 ;
        RECT  13.392 2.151 13.512 23.769 ;
        RECT  10.692 2.151 10.812 23.769 ;
        RECT  7.992 2.151 8.112 23.769 ;
        RECT  5.292 2.151 5.412 23.769 ;
        RECT  2.592 2.151 2.712 23.769 ;
    END
  END VDD
  PIN VSS
    DIRECTION INOUT ;
    USE GROUND ;
    PORT
      LAYER M5 ;
        RECT  56.4 2.137 56.52 23.783 ;
        RECT  53.7 2.137 53.82 23.783 ;
        RECT  51 2.137 51.12 23.783 ;
        RECT  48.3 2.137 48.42 23.783 ;
        RECT  45.6 2.137 45.72 23.783 ;
        RECT  42.9 2.137 43.02 23.783 ;
        RECT  40.2 2.137 40.32 23.783 ;
        RECT  37.5 2.137 37.62 23.783 ;
        RECT  34.8 2.137 34.92 23.783 ;
        RECT  32.1 2.137 32.22 23.783 ;
        RECT  29.4 2.137 29.52 23.783 ;
        RECT  26.7 2.137 26.82 23.783 ;
        RECT  24 2.137 24.12 23.783 ;
        RECT  21.3 2.137 21.42 23.783 ;
        RECT  18.6 2.137 18.72 23.783 ;
        RECT  15.9 2.137 16.02 23.783 ;
        RECT  13.2 2.137 13.32 23.783 ;
        RECT  10.5 2.137 10.62 23.783 ;
        RECT  7.8 2.137 7.92 23.783 ;
        RECT  5.1 2.137 5.22 23.783 ;
        RECT  2.4 2.137 2.52 23.783 ;
    END
  END VSS
  OBS
    LAYER RVTN ;
     RECT  2.16 2.16 58.32 2.295 ;
     RECT  2.16 2.565 58.32 2.835 ;
     RECT  2.16 3.105 58.32 3.375 ;
     RECT  2.16 3.645 58.32 3.915 ;
     RECT  2.16 4.185 58.32 4.455 ;
     RECT  2.16 4.725 58.32 4.995 ;
     RECT  2.16 5.265 58.32 5.535 ;
     RECT  2.16 5.805 58.32 6.075 ;
     RECT  2.16 6.345 58.32 6.615 ;
     RECT  2.16 6.885 58.32 7.155 ;
     RECT  2.16 7.425 58.32 7.695 ;
     RECT  2.16 7.965 58.32 8.235 ;
     RECT  2.16 8.505 58.32 8.775 ;
     RECT  2.16 9.045 58.32 9.315 ;
     RECT  2.16 9.585 58.32 9.855 ;
     RECT  2.16 10.125 58.32 10.395 ;
     RECT  2.16 10.665 58.32 10.935 ;
     RECT  2.16 11.205 58.32 11.475 ;
     RECT  2.16 11.745 58.32 12.015 ;
     RECT  2.16 12.285 58.32 12.555 ;
     RECT  2.16 12.825 58.32 13.095 ;
     RECT  2.16 13.365 58.32 13.635 ;
     RECT  2.16 13.905 58.32 14.175 ;
     RECT  2.16 14.445 58.32 14.715 ;
     RECT  2.16 14.985 58.32 15.255 ;
     RECT  2.16 15.525 58.32 15.795 ;
     RECT  2.16 16.065 58.32 16.335 ;
     RECT  2.16 16.605 58.32 16.875 ;
     RECT  2.16 17.145 58.32 17.415 ;
     RECT  2.16 17.685 58.32 17.955 ;
     RECT  2.16 18.225 58.32 18.495 ;
     RECT  2.16 18.765 58.32 19.035 ;
     RECT  2.16 19.305 58.32 19.575 ;
     RECT  2.16 19.845 58.32 20.115 ;
     RECT  2.16 20.385 58.32 20.655 ;
     RECT  2.16 20.925 58.32 21.195 ;
     RECT  2.16 21.465 58.32 21.735 ;
     RECT  2.16 22.005 58.32 22.275 ;
     RECT  2.16 22.545 58.32 22.815 ;
     RECT  2.16 23.085 58.32 23.355 ;
     RECT  2.16 23.625 58.32 23.76 ;
    LAYER RVTP ;
     RECT  2.16 2.295 58.32 2.565 ;
     RECT  2.16 2.835 58.32 3.105 ;
     RECT  2.16 3.375 58.32 3.645 ;
     RECT  2.16 3.915 58.32 4.185 ;
     RECT  2.16 4.455 58.32 4.725 ;
     RECT  2.16 4.995 58.32 5.265 ;
     RECT  2.16 5.535 58.32 5.805 ;
     RECT  2.16 6.075 58.32 6.345 ;
     RECT  2.16 6.615 58.32 6.885 ;
     RECT  2.16 7.155 58.32 7.425 ;
     RECT  2.16 7.695 58.32 7.965 ;
     RECT  2.16 8.235 58.32 8.505 ;
     RECT  2.16 8.775 58.32 9.045 ;
     RECT  2.16 9.315 58.32 9.585 ;
     RECT  2.16 9.855 58.32 10.125 ;
     RECT  2.16 10.395 58.32 10.665 ;
     RECT  2.16 10.935 58.32 11.205 ;
     RECT  2.16 11.475 58.32 11.745 ;
     RECT  2.16 12.015 58.32 12.285 ;
     RECT  2.16 12.555 58.32 12.825 ;
     RECT  2.16 13.095 58.32 13.365 ;
     RECT  2.16 13.635 58.32 13.905 ;
     RECT  2.16 14.175 58.32 14.445 ;
     RECT  2.16 14.715 58.32 14.985 ;
     RECT  2.16 15.255 58.32 15.525 ;
     RECT  2.16 15.795 58.32 16.065 ;
     RECT  2.16 16.335 58.32 16.605 ;
     RECT  2.16 16.875 58.32 17.145 ;
     RECT  2.16 17.415 58.32 17.685 ;
     RECT  2.16 17.955 58.32 18.225 ;
     RECT  2.16 18.495 58.32 18.765 ;
     RECT  2.16 19.035 58.32 19.305 ;
     RECT  2.16 19.575 58.32 19.845 ;
     RECT  2.16 20.115 58.32 20.385 ;
     RECT  2.16 20.655 58.32 20.925 ;
     RECT  2.16 21.195 58.32 21.465 ;
     RECT  2.16 21.735 58.32 22.005 ;
     RECT  2.16 22.275 58.32 22.545 ;
     RECT  2.16 22.815 58.32 23.085 ;
     RECT  2.16 23.355 58.32 23.625 ;
    LAYER M1 ;
     RECT  2.16 2.151 58.32 23.769 ;
    LAYER M2 ;
     RECT  2.16 2.151 2.479 23.769 ;
     RECT  2.479 2.151 2.759 23.85 ;
     RECT  2.759 2.151 2.839 23.769 ;
     RECT  2.299 0.036 3.263 0.054 ;
     RECT  2.839 25.866 3.335 25.884 ;
     RECT  2.839 1.728 3.875 23.769 ;
     RECT  4.135 0.036 4.811 0.054 ;
     RECT  3.875 2.151 7.879 23.769 ;
     RECT  7.015 0.036 7.907 0.054 ;
     RECT  7.879 2.151 7.979 23.85 ;
     RECT  7.979 2.151 8.059 23.769 ;
     RECT  8.059 1.728 8.735 23.769 ;
     RECT  8.779 0.036 8.879 0.054 ;
     RECT  8.735 2.151 9.175 23.769 ;
     RECT  9.175 2.151 9.527 23.922 ;
     RECT  10.075 0.036 10.679 0.054 ;
     RECT  9.527 2.151 10.751 23.814 ;
     RECT  9.967 1.152 10.859 1.17 ;
     RECT  10.867 25.866 11.075 25.884 ;
     RECT  10.751 2.151 11.947 23.769 ;
     RECT  11.947 1.728 12.299 23.769 ;
     RECT  12.299 2.151 13.099 23.769 ;
     RECT  12.847 0.036 13.271 0.054 ;
     RECT  13.099 2.151 13.423 23.85 ;
     RECT  13.423 1.728 13.603 23.85 ;
     RECT  10.255 24.786 13.603 24.804 ;
     RECT  13.603 1.728 13.819 24.804 ;
     RECT  13.819 1.152 13.955 24.804 ;
     RECT  14.539 0.036 14.639 0.054 ;
     RECT  13.955 1.728 15.107 24.804 ;
     RECT  15.107 2.151 15.187 24.804 ;
     RECT  15.187 2.151 15.539 25.119 ;
     RECT  15.547 0.036 15.763 0.054 ;
     RECT  15.763 0.036 15.863 0.126 ;
     RECT  15.863 0.108 16.043 0.126 ;
     RECT  15.539 2.151 16.151 25.038 ;
     RECT  16.151 2.151 17.563 24.804 ;
     RECT  17.563 2.151 18.103 25.119 ;
     RECT  18.103 2.106 18.311 25.119 ;
     RECT  18.311 2.106 18.419 24.804 ;
     RECT  18.571 0.036 18.707 0.054 ;
     RECT  19.003 25.794 19.139 25.812 ;
     RECT  20.695 25.794 20.831 25.812 ;
     RECT  18.419 2.151 20.867 24.804 ;
     RECT  20.867 2.151 21.271 24.228 ;
     RECT  21.775 0.036 21.911 0.054 ;
     RECT  21.271 1.728 22.091 24.228 ;
     RECT  22.091 1.728 22.199 23.994 ;
     RECT  22.199 1.728 22.675 23.769 ;
     RECT  22.675 0.036 22.775 0.054 ;
     RECT  22.675 1.152 22.775 23.769 ;
     RECT  22.927 25.146 23.063 25.164 ;
     RECT  23.359 25.866 23.495 25.884 ;
     RECT  22.775 1.728 23.927 23.769 ;
     RECT  23.927 2.151 24.043 23.769 ;
     RECT  24.043 0.036 24.359 0.054 ;
     RECT  24.043 2.151 24.503 23.85 ;
     RECT  26.239 0.036 26.627 0.054 ;
     RECT  24.503 2.151 26.815 23.769 ;
     RECT  26.815 2.151 26.851 23.85 ;
     RECT  26.851 2.151 27.059 23.958 ;
     RECT  27.059 2.151 27.203 23.85 ;
     RECT  27.203 2.151 27.211 23.769 ;
     RECT  27.211 1.728 28.643 23.769 ;
     RECT  28.643 2.151 29.299 23.769 ;
     RECT  29.299 2.151 29.435 23.85 ;
     RECT  28.327 0.036 29.651 0.054 ;
     RECT  29.435 2.151 29.983 23.769 ;
     RECT  29.983 2.106 30.523 23.769 ;
     RECT  30.919 24.561 31.055 24.579 ;
     RECT  30.523 1.728 31.171 23.769 ;
     RECT  31.171 1.152 31.271 23.769 ;
     RECT  31.271 1.8 31.415 23.769 ;
     RECT  31.415 2.151 31.999 23.769 ;
     RECT  31.567 25.101 32.099 25.119 ;
     RECT  31.999 2.151 32.215 23.85 ;
     RECT  32.215 1.728 32.243 23.85 ;
     RECT  32.243 1.728 32.603 23.769 ;
     RECT  32.899 1.152 32.999 1.17 ;
     RECT  32.863 25.866 32.999 25.884 ;
     RECT  32.603 2.106 33.791 23.769 ;
     RECT  33.791 2.151 34.843 23.769 ;
     RECT  34.843 2.151 34.979 23.85 ;
     RECT  34.087 0.036 35.159 0.054 ;
     RECT  34.979 2.151 35.167 23.769 ;
     RECT  35.167 1.728 35.627 23.769 ;
     RECT  35.959 0.036 36.887 0.054 ;
     RECT  35.627 2.151 37.615 23.769 ;
     RECT  37.615 2.151 37.831 23.85 ;
     RECT  37.615 0.036 37.895 0.054 ;
     RECT  37.831 1.728 37.967 23.85 ;
     RECT  37.967 1.728 38.723 23.769 ;
     RECT  38.659 0.036 38.759 0.054 ;
     RECT  38.659 24.516 38.759 24.534 ;
     RECT  38.723 1.8 38.975 23.769 ;
     RECT  39.307 25.101 39.551 25.119 ;
     RECT  38.975 2.151 39.847 23.769 ;
     RECT  39.847 1.728 40.135 23.769 ;
     RECT  40.135 0.036 40.235 0.054 ;
     RECT  40.135 1.728 40.235 23.85 ;
     RECT  41.143 0.036 41.243 0.054 ;
     RECT  41.503 25.101 41.639 25.119 ;
     RECT  40.235 1.728 42.835 23.769 ;
     RECT  42.835 1.728 42.863 23.85 ;
     RECT  42.799 0.108 42.871 0.126 ;
     RECT  42.871 0.036 43.295 0.126 ;
     RECT  43.295 0.108 43.331 0.126 ;
     RECT  42.863 2.151 43.591 23.85 ;
     RECT  43.591 2.151 43.727 23.958 ;
     RECT  44.311 25.101 44.663 25.119 ;
     RECT  43.727 2.151 45.607 23.769 ;
     RECT  45.391 0.036 45.779 0.054 ;
     RECT  45.607 2.151 45.779 23.85 ;
     RECT  45.779 2.151 45.787 23.769 ;
     RECT  45.787 1.728 47.579 23.769 ;
     RECT  47.479 25.866 47.795 25.884 ;
     RECT  47.579 2.151 48.163 23.769 ;
     RECT  46.903 0.036 48.407 0.054 ;
     RECT  48.163 2.151 48.407 23.85 ;
     RECT  48.407 2.151 48.775 23.769 ;
     RECT  48.703 25.146 48.803 25.164 ;
     RECT  48.955 25.101 49.199 25.119 ;
     RECT  49.135 25.866 49.451 25.884 ;
     RECT  48.775 1.728 49.531 23.769 ;
     RECT  49.531 1.656 49.667 23.769 ;
     RECT  49.667 2.151 50.899 23.769 ;
     RECT  50.971 0.108 51.007 0.126 ;
     RECT  50.899 2.151 51.035 23.85 ;
     RECT  51.007 0.036 51.179 0.126 ;
     RECT  51.179 0.108 51.251 0.126 ;
     RECT  51.035 2.151 51.727 23.769 ;
     RECT  51.727 1.728 51.899 23.769 ;
     RECT  51.727 25.101 51.943 25.119 ;
     RECT  51.367 25.866 51.943 25.884 ;
     RECT  51.943 25.101 52.043 25.884 ;
     RECT  52.043 25.794 52.115 25.884 ;
     RECT  52.115 25.866 52.259 25.884 ;
     RECT  51.899 2.151 53.599 23.769 ;
     RECT  53.599 2.106 53.815 23.769 ;
     RECT  53.815 1.728 54.059 23.85 ;
     RECT  54.059 1.728 54.095 23.769 ;
     RECT  53.995 25.101 54.419 25.119 ;
     RECT  54.095 2.106 54.995 23.769 ;
     RECT  54.895 1.224 55.039 1.242 ;
     RECT  55.039 1.152 55.139 1.242 ;
     RECT  54.995 2.151 55.831 23.769 ;
     RECT  55.831 1.728 55.931 23.769 ;
     RECT  56.191 0.036 56.291 0.054 ;
     RECT  55.931 2.151 56.299 23.769 ;
     RECT  56.299 2.151 56.435 23.85 ;
     RECT  56.435 2.151 56.767 23.769 ;
     RECT  56.875 25.866 57.011 25.884 ;
     RECT  56.767 1.728 57.083 23.769 ;
     RECT  57.083 1.8 57.379 23.769 ;
     RECT  57.379 1.8 57.407 23.994 ;
     RECT  57.407 2.151 57.515 23.994 ;
     RECT  57.515 2.151 58.32 23.769 ;
     RECT  58.32 3.186 58.343 3.204 ;
     RECT  58.32 12.798 58.343 12.816 ;
     RECT  58.32 19.548 58.343 19.566 ;
     RECT  58.32 3.96 58.379 3.978 ;
     RECT  58.32 7.092 58.379 7.11 ;
     RECT  58.32 11.016 58.379 11.034 ;
     RECT  58.32 14.688 58.379 14.706 ;
     RECT  58.027 0.036 58.415 0.054 ;
     RECT  58.32 5.238 58.415 5.256 ;
    LAYER M3 ;
     RECT  2.304 0.012 58.302 0.031 ;
     RECT  2.304 0.031 58.41 0.059 ;
     RECT  2.376 0.059 58.41 0.173 ;
     RECT  16.596 0.173 58.41 0.269 ;
     RECT  16.596 0.269 32.238 0.317 ;
     RECT  19.764 0.317 32.238 0.557 ;
     RECT  32.976 0.269 58.41 0.557 ;
     RECT  26.604 0.557 32.238 1.147 ;
     RECT  32.976 0.557 51.75 1.147 ;
     RECT  2.376 0.173 15.786 1.723 ;
     RECT  16.596 0.317 19.026 1.723 ;
     RECT  19.764 0.557 25.758 1.723 ;
     RECT  26.604 1.147 51.75 1.723 ;
     RECT  53.028 0.557 53.046 1.723 ;
     RECT  53.82 0.557 58.41 1.723 ;
     RECT  2.232 1.723 15.786 2.143 ;
     RECT  16.596 1.723 25.758 2.143 ;
     RECT  2.232 2.143 25.758 2.191 ;
     RECT  26.604 1.723 58.41 2.191 ;
     RECT  2.232 2.191 58.41 2.525 ;
     RECT  2.268 2.525 58.41 4.145 ;
     RECT  2.304 4.145 58.41 4.955 ;
     RECT  2.34 4.955 58.41 5.261 ;
     RECT  2.34 5.261 58.374 5.971 ;
     RECT  2.304 5.971 58.374 6.241 ;
     RECT  2.268 6.241 58.374 7.115 ;
     RECT  2.268 7.115 58.338 11.011 ;
     RECT  2.268 11.011 58.374 12.785 ;
     RECT  9.252 12.785 58.374 13.595 ;
     RECT  9.252 13.595 29.79 13.829 ;
     RECT  30.528 13.595 58.374 13.868 ;
     RECT  30.564 13.868 58.374 13.907 ;
     RECT  9.252 13.829 29.697 14.405 ;
     RECT  9.252 14.405 15.03 14.441 ;
     RECT  30.636 13.907 58.374 14.639 ;
     RECT  30.672 14.639 58.374 14.711 ;
     RECT  30.672 14.711 58.338 14.747 ;
     RECT  9.252 14.441 14.634 15.529 ;
     RECT  2.268 12.785 8.478 15.601 ;
     RECT  9.252 15.529 14.67 15.601 ;
     RECT  2.268 15.601 14.67 15.871 ;
     RECT  2.268 15.871 15.03 15.979 ;
     RECT  15.768 14.405 29.697 15.979 ;
     RECT  2.268 15.979 29.697 16.411 ;
     RECT  2.268 16.411 29.79 16.501 ;
     RECT  30.744 14.747 58.338 16.501 ;
     RECT  2.268 16.501 58.338 16.565 ;
     RECT  2.304 16.565 58.338 16.835 ;
     RECT  2.415 16.835 58.338 19.571 ;
     RECT  2.415 19.571 58.302 22.819 ;
     RECT  2.304 22.819 58.302 25.901 ;
    LAYER M4 ;
     RECT  2.177 1.728 2.257 1.752 ;
     RECT  2.285 4.56 2.293 4.584 ;
     RECT  2.257 1.728 2.408 2.424 ;
     RECT  2.293 4.128 2.408 4.584 ;
     RECT  2.365 10.32 2.408 10.632 ;
     RECT  2.197 16.512 2.408 16.536 ;
     RECT  2.408 1.728 2.512 23.772 ;
     RECT  2.389 25.728 2.533 25.752 ;
     RECT  2.512 1.728 2.704 23.502 ;
     RECT  2.533 0.144 2.725 0.168 ;
     RECT  2.533 25.728 2.725 25.8 ;
     RECT  2.725 0.144 2.819 0.264 ;
     RECT  2.819 0.24 2.867 0.264 ;
     RECT  2.725 25.632 2.873 25.8 ;
     RECT  2.704 17.52 2.88 17.544 ;
     RECT  2.873 25.632 3.017 25.656 ;
     RECT  2.704 3.408 3.059 11.496 ;
     RECT  2.704 22.752 3.089 23.4 ;
     RECT  3.089 23.328 3.413 23.4 ;
     RECT  2.704 1.728 3.685 1.752 ;
     RECT  3.493 25.056 3.685 25.08 ;
     RECT  3.059 7.872 3.769 11.496 ;
     RECT  3.769 7.872 3.773 11.592 ;
     RECT  3.685 1.728 3.845 1.8 ;
     RECT  3.413 23.376 3.923 23.4 ;
     RECT  3.685 24.48 3.953 25.08 ;
     RECT  3.953 25.056 3.989 25.08 ;
     RECT  3.773 7.872 4.097 10.296 ;
     RECT  3.059 4.224 4.213 6.888 ;
     RECT  4.213 3.408 4.405 6.888 ;
     RECT  4.597 25.68 4.853 25.8 ;
     RECT  4.853 25.68 4.889 25.752 ;
     RECT  3.773 11.424 4.957 11.592 ;
     RECT  4.981 17.616 4.993 17.64 ;
     RECT  3.845 1.728 5.108 1.752 ;
     RECT  4.405 2.88 5.108 6.888 ;
     RECT  4.097 7.872 5.108 10.152 ;
     RECT  4.957 11.136 5.108 11.592 ;
     RECT  4.993 16.896 5.108 17.64 ;
     RECT  4.405 20.064 5.108 20.088 ;
     RECT  4.021 23.856 5.108 23.928 ;
     RECT  5.108 1.728 5.404 23.928 ;
     RECT  5.404 11.136 5.465 11.448 ;
     RECT  5.404 1.728 5.573 10.152 ;
     RECT  4.889 25.728 5.603 25.752 ;
     RECT  5.573 1.776 5.609 10.152 ;
     RECT  5.609 1.776 5.681 9.144 ;
     RECT  5.404 22.752 5.681 23.928 ;
     RECT  5.404 16.896 5.747 17.4 ;
     RECT  5.681 2.688 5.753 9.144 ;
     RECT  5.753 2.688 5.789 5.256 ;
     RECT  5.747 16.896 5.795 16.92 ;
     RECT  5.681 23.328 6.149 23.928 ;
     RECT  5.789 2.688 6.275 5.064 ;
     RECT  5.404 19.68 6.401 19.704 ;
     RECT  5.609 10.128 6.524 10.152 ;
     RECT  6.277 25.056 6.581 25.08 ;
     RECT  5.753 6.432 6.721 9.144 ;
     RECT  6.275 5.04 6.793 5.064 ;
     RECT  6.793 5.04 6.937 5.112 ;
     RECT  6.721 6.288 6.937 9.144 ;
     RECT  5.465 11.424 7.045 11.448 ;
     RECT  6.865 12.528 7.045 12.552 ;
     RECT  5.461 0.048 7.139 0.072 ;
     RECT  6.275 2.688 7.141 4.008 ;
     RECT  6.997 18.144 7.189 18.168 ;
     RECT  6.524 10.128 7.261 10.344 ;
     RECT  7.045 11.424 7.261 12.552 ;
     RECT  6.149 23.856 7.409 23.928 ;
     RECT  7.369 0.096 7.525 0.552 ;
     RECT  7.141 2.208 7.525 4.008 ;
     RECT  6.937 5.04 7.525 9.144 ;
     RECT  7.525 2.208 7.573 9.144 ;
     RECT  7.261 10.128 7.573 12.552 ;
     RECT  7.573 2.208 7.621 12.552 ;
     RECT  7.525 0.096 7.669 1.176 ;
     RECT  7.621 2.208 7.669 13.08 ;
     RECT  7.669 0.096 7.715 13.08 ;
     RECT  7.715 1.728 7.808 13.08 ;
     RECT  7.669 15.792 7.808 15.816 ;
     RECT  7.189 18 7.808 18.168 ;
     RECT  7.573 19.584 7.808 19.608 ;
     RECT  7.381 22.752 7.808 22.776 ;
     RECT  7.669 25.776 7.957 25.8 ;
     RECT  7.808 1.728 8.104 23.772 ;
     RECT  7.957 25.728 8.201 25.8 ;
     RECT  7.715 0.096 8.291 0.552 ;
     RECT  8.201 25.728 8.339 25.752 ;
     RECT  8.291 0.528 8.387 0.552 ;
     RECT  8.104 1.728 8.777 12.552 ;
     RECT  8.777 2.832 9.097 12.552 ;
     RECT  9.097 2.832 9.109 12.6 ;
     RECT  9.109 2.832 9.421 12.696 ;
     RECT  8.104 22.752 9.445 22.776 ;
     RECT  9.421 2.832 9.493 13.128 ;
     RECT  9.445 22.032 9.529 22.776 ;
     RECT  8.104 19.584 9.637 19.656 ;
     RECT  9.637 19.584 9.973 20.616 ;
     RECT  8.777 1.728 10.037 1.752 ;
     RECT  9.493 2.832 10.117 13.176 ;
     RECT  8.485 23.856 10.213 23.928 ;
     RECT  8.104 15.792 10.261 16.392 ;
     RECT  9.529 22.032 10.261 22.824 ;
     RECT  10.213 23.856 10.261 23.976 ;
     RECT  10.357 25.728 10.429 25.752 ;
     RECT  10.429 25.104 10.453 25.752 ;
     RECT  10.117 2.016 10.508 13.176 ;
     RECT  10.261 15.792 10.508 17.064 ;
     RECT  9.973 19.536 10.508 20.616 ;
     RECT  10.261 22.032 10.508 23.976 ;
     RECT  10.508 2.016 10.595 23.976 ;
     RECT  10.595 2.016 10.612 23.772 ;
     RECT  10.261 0.096 10.787 0.12 ;
     RECT  10.612 2.016 10.804 23.502 ;
     RECT  10.804 15.696 11.027 17.112 ;
     RECT  10.453 25.104 11.171 25.848 ;
     RECT  10.804 2.016 11.285 13.08 ;
     RECT  10.804 18.816 11.341 22.776 ;
     RECT  11.341 19.488 11.363 22.776 ;
     RECT  11.363 21.648 11.699 22.776 ;
     RECT  11.699 22.176 11.797 22.776 ;
     RECT  11.285 1.728 11.869 13.08 ;
     RECT  11.797 22.176 11.891 23.4 ;
     RECT  11.027 15.696 12.085 16.392 ;
     RECT  11.171 25.824 12.581 25.848 ;
     RECT  12.581 25.776 12.589 25.848 ;
     RECT  12.085 15.408 12.769 16.392 ;
     RECT  12.769 15.408 12.805 16.584 ;
     RECT  11.869 1.728 13.093 13.128 ;
     RECT  13.093 0.288 13.141 0.312 ;
     RECT  13.093 1.728 13.208 13.32 ;
     RECT  12.805 15.408 13.208 17.112 ;
     RECT  11.363 19.488 13.208 20.616 ;
     RECT  11.891 22.176 13.208 22.824 ;
     RECT  12.401 23.904 13.208 23.928 ;
     RECT  13.208 1.728 13.345 23.928 ;
     RECT  12.589 25.104 13.379 25.848 ;
     RECT  13.345 1.728 13.504 23.976 ;
     RECT  13.141 0.144 13.571 0.312 ;
     RECT  13.504 23.904 13.571 23.976 ;
     RECT  13.571 0.144 13.619 0.264 ;
     RECT  13.379 25.824 13.637 25.848 ;
     RECT  13.619 0.24 13.667 0.264 ;
     RECT  13.504 15.408 13.673 17.688 ;
     RECT  13.504 21.648 13.763 22.872 ;
     RECT  13.673 17.664 13.781 17.688 ;
     RECT  13.504 1.728 13.925 10.92 ;
     RECT  13.504 12.192 13.955 13.752 ;
     RECT  13.925 1.728 14.393 10.872 ;
     RECT  14.393 10.8 14.429 10.872 ;
     RECT  13.571 23.904 14.429 23.928 ;
     RECT  14.393 1.728 14.501 9.72 ;
     RECT  13.955 12.24 14.533 13.752 ;
     RECT  13.673 15.408 14.573 16.392 ;
     RECT  14.533 12.24 14.617 14.28 ;
     RECT  13.763 22.176 14.749 22.872 ;
     RECT  14.429 10.848 14.771 10.872 ;
     RECT  14.749 22.176 14.821 23.4 ;
     RECT  13.504 19.488 14.861 20.616 ;
     RECT  14.821 22.032 14.867 23.4 ;
     RECT  14.573 15.792 14.965 16.392 ;
     RECT  14.597 0.096 15.068 0.12 ;
     RECT  15.068 0.048 15.155 0.12 ;
     RECT  14.965 15.792 15.301 16.584 ;
     RECT  14.501 2.256 15.404 9.72 ;
     RECT  15.361 1.152 15.445 1.176 ;
     RECT  14.617 12.24 15.445 13.848 ;
     RECT  14.972 25.104 15.569 25.128 ;
     RECT  15.445 12.192 15.637 13.848 ;
     RECT  14.861 19.536 15.649 20.616 ;
     RECT  14.867 22.032 15.649 23.208 ;
     RECT  15.569 25.104 15.653 25.8 ;
     RECT  15.301 15.792 15.685 17.064 ;
     RECT  15.637 0.144 15.725 0.552 ;
     RECT  15.404 2.256 15.781 10.584 ;
     RECT  15.637 12.048 15.781 13.848 ;
     RECT  15.653 25.104 15.781 25.128 ;
     RECT  15.781 25.008 15.827 25.128 ;
     RECT  15.649 19.536 15.865 23.208 ;
     RECT  15.781 2.256 15.908 13.848 ;
     RECT  15.685 15.792 15.908 17.112 ;
     RECT  15.865 19.536 15.908 23.88 ;
     RECT  15.827 25.008 16.157 25.032 ;
     RECT  15.908 2.148 16.204 23.88 ;
     RECT  15.725 0.144 16.225 0.312 ;
     RECT  16.225 0.048 16.451 0.312 ;
     RECT  16.204 15.792 16.499 16.92 ;
     RECT  16.451 0.048 16.835 0.168 ;
     RECT  16.204 2.148 16.865 13.128 ;
     RECT  16.204 22.032 16.885 23.88 ;
     RECT  16.865 1.728 17.021 13.128 ;
     RECT  16.885 22.032 17.021 23.928 ;
     RECT  16.835 0.144 17.027 0.168 ;
     RECT  17.021 1.728 17.036 12.504 ;
     RECT  17.021 22.032 17.123 23.4 ;
     RECT  17.036 1.152 17.157 12.504 ;
     RECT  17.197 14.208 17.341 14.232 ;
     RECT  17.197 25.104 17.413 25.128 ;
     RECT  16.499 15.792 17.557 16.584 ;
     RECT  17.157 1.728 17.641 12.504 ;
     RECT  17.413 25.104 18.061 25.176 ;
     RECT  18.061 25.104 18.076 25.224 ;
     RECT  17.893 0.528 18.092 0.552 ;
     RECT  17.641 11.52 18.097 12.504 ;
     RECT  17.341 13.68 18.097 14.232 ;
     RECT  18.076 25.2 18.227 25.224 ;
     RECT  17.123 22.032 18.313 22.824 ;
     RECT  18.313 21.744 18.349 22.824 ;
     RECT  17.641 1.728 18.608 10.344 ;
     RECT  18.097 11.52 18.608 14.232 ;
     RECT  17.557 15.792 18.608 17.112 ;
     RECT  18.181 18.24 18.608 18.264 ;
     RECT  16.204 19.536 18.608 20.616 ;
     RECT  18.349 21.648 18.608 22.824 ;
     RECT  18.608 1.728 18.712 23.772 ;
     RECT  18.092 0.144 18.857 0.552 ;
     RECT  18.857 0.144 18.901 0.312 ;
     RECT  18.712 1.728 18.904 23.502 ;
     RECT  18.904 18.768 19.037 20.616 ;
     RECT  18.904 21.648 19.139 23.4 ;
     RECT  18.904 1.728 19.145 16.584 ;
     RECT  19.139 22.128 19.331 23.4 ;
     RECT  18.901 0.096 19.393 0.312 ;
     RECT  19.145 2.256 19.523 16.584 ;
     RECT  18.373 25.584 19.609 25.8 ;
     RECT  19.523 15.408 19.613 16.584 ;
     RECT  19.393 0.048 19.715 0.312 ;
     RECT  19.715 0.048 19.811 0.12 ;
     RECT  19.613 15.456 19.933 16.584 ;
     RECT  19.933 15.456 20.005 16.632 ;
     RECT  19.037 19.488 20.045 20.616 ;
     RECT  19.523 2.256 20.149 14.328 ;
     RECT  19.811 0.048 20.195 0.072 ;
     RECT  19.609 25.104 20.291 25.8 ;
     RECT  20.291 25.152 20.435 25.8 ;
     RECT  20.005 15.456 20.533 16.68 ;
     RECT  18.904 17.664 20.533 17.688 ;
     RECT  20.149 2.208 20.573 14.328 ;
     RECT  20.533 15.456 20.629 17.688 ;
     RECT  20.573 1.728 20.657 14.328 ;
     RECT  19.331 22.128 20.761 22.776 ;
     RECT  20.435 25.728 20.837 25.8 ;
     RECT  20.657 1.92 21.013 14.328 ;
     RECT  21.013 1.92 21.085 14.424 ;
     RECT  20.761 21.648 21.116 22.776 ;
     RECT  20.629 15.456 21.149 17.784 ;
     RECT  21.149 15.456 21.157 18.264 ;
     RECT  20.045 19.536 21.157 20.616 ;
     RECT  21.116 21.648 21.157 22.824 ;
     RECT  21.121 23.856 21.157 23.88 ;
     RECT  21.085 1.92 21.308 14.472 ;
     RECT  21.157 15.456 21.308 20.616 ;
     RECT  21.157 21.648 21.308 23.88 ;
     RECT  20.837 25.728 21.395 25.752 ;
     RECT  20.869 0.144 21.445 0.168 ;
     RECT  21.308 1.92 21.604 23.88 ;
     RECT  21.604 19.056 21.629 20.136 ;
     RECT  21.445 0.048 21.683 0.168 ;
     RECT  21.629 19.776 21.701 20.136 ;
     RECT  21.604 22.8 21.733 23.88 ;
     RECT  21.701 19.824 21.845 20.136 ;
     RECT  21.604 1.92 21.869 17.112 ;
     RECT  21.733 22.8 21.923 23.928 ;
     RECT  21.845 19.824 21.953 19.848 ;
     RECT  21.869 1.728 22.115 17.112 ;
     RECT  21.923 23.328 22.205 23.928 ;
     RECT  22.205 23.328 22.241 23.352 ;
     RECT  22.115 1.728 22.277 14.424 ;
     RECT  22.115 15.408 22.349 17.112 ;
     RECT  22.349 15.984 22.357 17.112 ;
     RECT  22.357 16.272 22.693 17.112 ;
     RECT  22.277 1.728 22.781 14.28 ;
     RECT  22.781 1.728 22.853 13.752 ;
     RECT  22.22 25.104 22.988 25.128 ;
     RECT  22.693 16.272 23.077 17.16 ;
     RECT  22.988 25.104 23.26 25.224 ;
     RECT  21.683 0.144 23.365 0.168 ;
     RECT  23.365 25.728 23.501 25.8 ;
     RECT  23.365 0.144 23.557 0.264 ;
     RECT  23.497 21.648 23.641 21.672 ;
     RECT  23.077 16.272 23.713 17.688 ;
     RECT  23.557 0.096 23.941 0.264 ;
     RECT  22.853 1.728 23.941 13.656 ;
     RECT  23.941 0.096 24.008 13.656 ;
     RECT  23.713 16.272 24.008 18.264 ;
     RECT  23.641 21.648 24.008 22.248 ;
     RECT  24.008 0.096 24.133 23.772 ;
     RECT  24.133 0.096 24.304 24.504 ;
     RECT  24.304 23.328 24.365 24.504 ;
     RECT  24.304 0.096 24.419 13.752 ;
     RECT  24.304 22.224 24.419 22.248 ;
     RECT  23.501 25.728 24.419 25.752 ;
     RECT  24.365 23.328 24.467 23.88 ;
     RECT  24.304 15.408 24.563 17.16 ;
     RECT  24.419 1.728 24.581 9.192 ;
     RECT  24.419 0.096 24.613 0.312 ;
     RECT  24.467 23.328 24.725 23.352 ;
     RECT  24.563 15.456 24.755 17.16 ;
     RECT  24.613 0.048 24.851 0.312 ;
     RECT  24.62 25.104 25.397 25.176 ;
     RECT  25.397 25.104 25.481 25.8 ;
     RECT  24.755 16.272 25.597 17.16 ;
     RECT  24.581 2.208 25.657 9.192 ;
     RECT  24.419 10.176 25.657 13.752 ;
     RECT  25.481 25.104 25.667 25.128 ;
     RECT  25.657 2.208 25.765 13.752 ;
     RECT  24.851 0.048 25.861 0.216 ;
     RECT  25.765 21.648 25.981 21.672 ;
     RECT  25.861 0.048 26.129 0.552 ;
     RECT  26.005 23.328 26.3 23.352 ;
     RECT  25.981 21.648 26.521 22.248 ;
     RECT  26.3 23.328 26.521 23.4 ;
     RECT  26.521 21.648 26.533 23.4 ;
     RECT  25.597 16.272 26.581 16.296 ;
     RECT  26.533 21.648 26.581 23.928 ;
     RECT  25.765 2.208 26.708 13.848 ;
     RECT  26.581 16.272 26.708 16.584 ;
     RECT  26.581 21.648 26.708 24.024 ;
     RECT  26.708 2.148 26.771 24.024 ;
     RECT  26.771 2.148 26.812 23.88 ;
     RECT  26.812 2.256 27.004 23.88 ;
     RECT  27.004 23.856 27.065 23.88 ;
     RECT  26.129 0.048 27.155 0.456 ;
     RECT  27.155 0.048 27.251 0.408 ;
     RECT  27.251 0.144 27.347 0.408 ;
     RECT  27.004 16.56 27.425 17.688 ;
     RECT  27.068 25.104 27.538 25.128 ;
     RECT  27.347 0.144 27.641 0.312 ;
     RECT  27.425 17.136 27.749 17.688 ;
     RECT  27.749 17.616 27.965 17.688 ;
     RECT  27.538 25.104 27.989 25.176 ;
     RECT  27.004 2.256 28.021 14.136 ;
     RECT  27.989 25.104 28.073 25.8 ;
     RECT  27.965 17.664 28.249 17.688 ;
     RECT  28.073 25.104 28.259 25.128 ;
     RECT  28.249 17.664 28.333 18.264 ;
     RECT  28.105 22.8 28.537 22.824 ;
     RECT  28.357 15.984 28.645 16.008 ;
     RECT  28.645 15.984 28.837 16.056 ;
     RECT  28.021 1.728 28.901 14.136 ;
     RECT  28.901 1.776 28.973 14.136 ;
     RECT  28.537 22.224 29.125 22.824 ;
     RECT  28.385 23.904 29.125 23.928 ;
     RECT  27.641 0.144 29.221 0.216 ;
     RECT  29.221 0.096 29.269 0.216 ;
     RECT  29.125 22.224 29.369 23.928 ;
     RECT  28.973 2.148 29.408 14.136 ;
     RECT  28.837 15.984 29.408 16.584 ;
     RECT  28.333 17.664 29.408 17.688 ;
     RECT  29.369 22.224 29.408 23.772 ;
     RECT  29.408 2.148 29.512 23.772 ;
     RECT  29.269 0.096 29.555 0.552 ;
     RECT  29.512 2.256 29.704 23.502 ;
     RECT  29.501 25.776 29.852 25.8 ;
     RECT  29.704 16.56 29.917 18.264 ;
     RECT  29.704 21.648 29.945 22.824 ;
     RECT  29.555 0.096 29.948 0.12 ;
     RECT  29.917 17.088 30.125 18.264 ;
     RECT  29.852 25.104 30.131 25.8 ;
     RECT  30.125 17.136 30.305 18.264 ;
     RECT  29.945 21.648 30.323 22.2 ;
     RECT  30.229 1.152 30.371 1.176 ;
     RECT  30.323 22.176 30.557 22.2 ;
     RECT  29.948 0.048 30.625 0.12 ;
     RECT  30.305 17.664 30.665 18.264 ;
     RECT  29.704 2.256 30.697 13.896 ;
     RECT  30.665 17.952 30.709 18.264 ;
     RECT  30.131 25.776 30.755 25.8 ;
     RECT  30.697 2.208 30.841 13.896 ;
     RECT  30.709 18.048 30.881 18.264 ;
     RECT  30.805 24.48 30.953 24.504 ;
     RECT  30.881 18.24 30.989 18.264 ;
     RECT  30.997 22.224 31.084 22.248 ;
     RECT  30.841 1.728 31.241 13.896 ;
     RECT  31.241 2.016 31.381 13.896 ;
     RECT  31.34 22.8 31.426 22.824 ;
     RECT  31.453 15.984 31.517 16.008 ;
     RECT  31.597 23.952 31.811 23.976 ;
     RECT  30.625 0.048 31.849 0.168 ;
     RECT  31.517 15.408 31.909 16.008 ;
     RECT  31.741 25.104 31.957 25.128 ;
     RECT  31.381 2.016 31.993 13.992 ;
     RECT  31.909 15.408 31.993 16.824 ;
     RECT  31.957 25.104 32.029 25.176 ;
     RECT  31.849 0.048 32.065 0.216 ;
     RECT  31.993 2.016 32.108 16.824 ;
     RECT  31.189 19.92 32.108 19.944 ;
     RECT  31.426 22.8 32.108 22.872 ;
     RECT  32.108 2.016 32.212 23.772 ;
     RECT  32.212 2.016 32.293 23.502 ;
     RECT  32.293 1.728 32.404 23.502 ;
     RECT  32.029 25.104 32.453 25.224 ;
     RECT  32.065 0.048 32.57 0.312 ;
     RECT  32.404 16.56 32.579 16.68 ;
     RECT  32.57 0.048 32.675 0.264 ;
     RECT  32.579 16.56 32.723 16.584 ;
     RECT  32.675 0.048 32.771 0.216 ;
     RECT  32.404 17.76 32.897 17.784 ;
     RECT  32.771 0.048 33.011 0.12 ;
     RECT  32.404 1.728 33.059 14.856 ;
     RECT  32.453 25.104 33.148 25.8 ;
     RECT  33.059 8.4 33.257 14.856 ;
     RECT  32.404 18.816 33.265 18.84 ;
     RECT  33.257 14.256 33.293 14.856 ;
     RECT  33.148 25.104 33.299 25.752 ;
     RECT  33.293 14.256 33.517 14.76 ;
     RECT  33.433 18.192 33.587 18.216 ;
     RECT  33.299 25.728 33.587 25.752 ;
     RECT  33.469 23.376 33.635 23.4 ;
     RECT  33.059 1.728 34.057 7.224 ;
     RECT  34.057 1.968 34.153 7.224 ;
     RECT  33.257 8.4 34.153 12.936 ;
     RECT  33.011 0.048 34.165 0.072 ;
     RECT  33.74 23.952 34.211 23.976 ;
     RECT  34.253 16.56 34.405 16.584 ;
     RECT  34.165 0.048 34.499 0.12 ;
     RECT  34.153 1.968 34.513 12.936 ;
     RECT  34.357 25.632 34.549 25.656 ;
     RECT  34.405 16.56 34.693 17.208 ;
     RECT  34.549 25.632 34.694 25.752 ;
     RECT  34.694 25.68 34.701 25.752 ;
     RECT  34.701 25.68 34.805 25.8 ;
     RECT  34.513 1.968 34.808 12.984 ;
     RECT  33.517 14.304 34.808 14.76 ;
     RECT  34.693 16.56 34.808 17.64 ;
     RECT  33.973 19.68 34.808 19.704 ;
     RECT  34.441 22.8 34.808 22.824 ;
     RECT  34.808 1.968 35.104 23.928 ;
     RECT  34.499 0.096 35.219 0.12 ;
     RECT  35.104 17.664 35.267 17.688 ;
     RECT  35.104 22.8 35.345 23.928 ;
     RECT  35.104 1.968 35.363 14.808 ;
     RECT  35.363 1.968 35.453 14.424 ;
     RECT  35.345 22.8 35.699 23.4 ;
     RECT  35.453 1.968 35.845 13.8 ;
     RECT  35.699 23.328 35.891 23.4 ;
     RECT  35.845 1.728 36.101 13.8 ;
     RECT  35.891 23.328 36.245 23.352 ;
     RECT  36.101 4.992 36.419 13.8 ;
     RECT  36.101 1.728 36.461 3.864 ;
     RECT  36.419 4.992 36.467 12.504 ;
     RECT  36.229 24.48 36.497 24.504 ;
     RECT  36.467 5.04 36.533 12.504 ;
     RECT  36.421 19.68 36.565 19.704 ;
     RECT  36.565 16.56 36.949 16.584 ;
     RECT  36.461 2.256 37.285 3.864 ;
     RECT  37.285 2.256 37.508 4.008 ;
     RECT  36.533 5.04 37.508 10.344 ;
     RECT  36.533 11.424 37.508 12.504 ;
     RECT  36.419 13.68 37.508 13.8 ;
     RECT  36.949 16.56 37.508 17.112 ;
     RECT  37.333 18.192 37.508 18.216 ;
     RECT  36.565 19.68 37.508 19.944 ;
     RECT  37.465 23.904 37.508 23.928 ;
     RECT  34.805 25.776 37.717 25.8 ;
     RECT  37.508 2.148 37.804 23.928 ;
     RECT  37.717 25.584 37.955 25.8 ;
     RECT  37.804 23.328 37.981 23.4 ;
     RECT  37.285 0.144 38.003 0.168 ;
     RECT  37.804 2.148 38.033 4.008 ;
     RECT  37.981 23.376 38.099 23.4 ;
     RECT  37.955 25.776 38.153 25.8 ;
     RECT  37.804 4.992 38.261 13.08 ;
     RECT  38.033 1.728 38.405 4.008 ;
     RECT  38.405 2.16 38.441 4.008 ;
     RECT  38.245 24.432 38.657 24.504 ;
     RECT  38.657 24.432 38.765 24.456 ;
     RECT  38.261 8.4 38.797 13.08 ;
     RECT  38.441 2.256 38.801 4.008 ;
     RECT  38.797 8.4 38.837 13.32 ;
     RECT  38.837 8.4 39.017 10.104 ;
     RECT  37.804 19.92 39.053 19.944 ;
     RECT  38.801 2.304 39.125 4.008 ;
     RECT  38.821 16.56 39.161 16.584 ;
     RECT  39.125 2.784 39.301 4.008 ;
     RECT  38.261 4.992 39.301 7.368 ;
     RECT  39.301 2.784 39.349 7.368 ;
     RECT  39.017 8.4 39.349 9.816 ;
     RECT  39.205 25.776 39.376 25.8 ;
     RECT  38.837 11.376 39.98 13.32 ;
     RECT  39.98 11.376 40.021 14.136 ;
     RECT  40.021 0.096 40.069 0.12 ;
     RECT  39.349 2.784 40.069 9.816 ;
     RECT  40.021 10.896 40.069 14.136 ;
     RECT  39.376 25.728 40.133 25.8 ;
     RECT  40.069 0.096 40.163 0.216 ;
     RECT  38.821 23.808 40.165 23.928 ;
     RECT  40.069 2.784 40.208 14.136 ;
     RECT  39.589 17.664 40.208 17.688 ;
     RECT  39.541 22.752 40.208 22.776 ;
     RECT  40.165 23.808 40.208 23.976 ;
     RECT  40.163 0.192 40.355 0.216 ;
     RECT  40.208 2.148 40.501 23.976 ;
     RECT  40.501 1.728 40.504 23.976 ;
     RECT  40.504 1.728 40.883 14.088 ;
     RECT  40.501 25.056 40.889 25.08 ;
     RECT  40.504 23.808 40.997 23.976 ;
     RECT  40.997 23.904 41.029 23.976 ;
     RECT  40.883 1.728 41.033 9.672 ;
     RECT  40.883 10.704 41.069 14.088 ;
     RECT  41.033 1.728 41.116 6.888 ;
     RECT  41.033 7.92 41.141 9.672 ;
     RECT  41.069 10.704 41.285 13.224 ;
     RECT  41.029 23.904 41.429 24.504 ;
     RECT  41.116 2.256 41.501 6.888 ;
     RECT  40.504 19.68 41.645 19.944 ;
     RECT  41.597 17.088 41.681 17.112 ;
     RECT  41.605 25.776 42.077 25.8 ;
     RECT  41.501 2.256 42.181 4.008 ;
     RECT  41.285 10.704 42.181 13.08 ;
     RECT  41.501 4.992 42.389 6.888 ;
     RECT  41.141 7.92 42.389 9.336 ;
     RECT  42.181 1.728 42.505 4.008 ;
     RECT  42.389 4.992 42.505 9.336 ;
     RECT  42.505 1.728 42.721 9.336 ;
     RECT  42.181 10.608 42.721 13.08 ;
     RECT  42.721 1.728 42.908 13.08 ;
     RECT  42.073 14.784 42.908 14.808 ;
     RECT  41.645 19.92 42.908 19.944 ;
     RECT  42.181 22.752 42.908 22.776 ;
     RECT  41.429 23.904 42.908 23.928 ;
     RECT  42.908 1.728 43.093 23.928 ;
     RECT  43.093 1.728 43.139 24.024 ;
     RECT  43.139 2.418 43.204 24.024 ;
     RECT  43.204 2.832 43.301 3.912 ;
     RECT  43.204 22.8 43.301 24.024 ;
     RECT  43.301 2.832 43.379 3.864 ;
     RECT  43.204 4.992 43.409 13.176 ;
     RECT  43.409 8.496 43.445 13.176 ;
     RECT  43.409 4.992 43.517 7.32 ;
     RECT  43.445 9.024 43.517 13.176 ;
     RECT  43.204 19.68 43.553 19.944 ;
     RECT  43.517 9.072 43.733 13.176 ;
     RECT  43.301 22.8 43.733 23.928 ;
     RECT  44.005 25.776 44.197 25.8 ;
     RECT  43.733 11.136 44.309 13.176 ;
     RECT  43.733 22.8 44.435 23.4 ;
     RECT  44.197 25.728 44.453 25.8 ;
     RECT  43.517 5.136 44.701 7.32 ;
     RECT  44.701 5.136 44.809 7.416 ;
     RECT  43.733 9.072 44.821 10.152 ;
     RECT  44.309 11.136 44.821 12.312 ;
     RECT  44.821 9.072 44.845 12.312 ;
     RECT  43.379 2.88 44.917 3.864 ;
     RECT  44.809 4.896 44.917 7.416 ;
     RECT  44.917 2.832 44.945 3.864 ;
     RECT  44.917 4.896 44.945 7.464 ;
     RECT  44.485 0.048 45.107 0.072 ;
     RECT  44.945 2.832 45.205 7.464 ;
     RECT  44.845 9.024 45.241 12.312 ;
     RECT  45.205 2.256 45.341 7.464 ;
     RECT  45.241 8.496 45.457 12.312 ;
     RECT  44.581 22.752 45.485 22.776 ;
     RECT  44.773 23.904 45.485 23.928 ;
     RECT  45.457 8.496 45.601 12.36 ;
     RECT  45.341 1.728 45.608 7.464 ;
     RECT  45.601 8.496 45.608 12.6 ;
     RECT  43.553 19.92 45.608 19.944 ;
     RECT  45.485 22.752 45.608 23.928 ;
     RECT  44.453 25.776 45.685 25.8 ;
     RECT  45.608 1.728 45.904 23.928 ;
     RECT  45.904 9.072 46.073 13.848 ;
     RECT  45.685 25.056 46.073 25.8 ;
     RECT  45.904 1.728 46.115 7.416 ;
     RECT  45.904 23.328 46.145 23.928 ;
     RECT  45.685 0.288 46.163 0.312 ;
     RECT  46.073 9.072 46.217 13.08 ;
     RECT  45.904 19.92 46.217 19.944 ;
     RECT  45.904 16.56 46.693 17.112 ;
     RECT  46.115 2.256 46.897 7.416 ;
     RECT  46.693 17.088 46.933 17.112 ;
     RECT  45.904 18.192 46.933 18.216 ;
     RECT  46.897 2.256 46.969 7.464 ;
     RECT  46.933 17.088 47.017 18.216 ;
     RECT  46.94 22.224 47.027 22.248 ;
     RECT  47.017 18.192 47.045 18.216 ;
     RECT  47.017 17.088 47.161 17.112 ;
     RECT  46.217 11.904 47.329 13.08 ;
     RECT  46.217 9.072 47.473 10.632 ;
     RECT  47.329 11.904 47.473 13.128 ;
     RECT  46.969 2.256 47.509 7.752 ;
     RECT  46.073 25.776 47.557 25.8 ;
     RECT  47.509 2.208 47.941 7.752 ;
     RECT  47.473 9.072 47.941 13.128 ;
     RECT  46.145 23.328 48.085 23.352 ;
     RECT  47.941 1.728 48.089 13.128 ;
     RECT  47.797 0.144 48.181 0.168 ;
     RECT  48.089 2.148 48.308 13.128 ;
     RECT  47.749 19.68 48.308 19.704 ;
     RECT  48.085 23.328 48.308 23.976 ;
     RECT  48.308 2.148 48.371 23.976 ;
     RECT  47.557 25.728 48.469 25.8 ;
     RECT  48.181 0.144 48.553 0.264 ;
     RECT  48.371 2.148 48.604 23.928 ;
     RECT  48.604 2.148 48.737 13.704 ;
     RECT  48.469 25.056 48.809 25.8 ;
     RECT  48.553 0.144 48.908 0.552 ;
     RECT  48.604 18.768 48.917 18.792 ;
     RECT  48.908 0.048 48.956 0.552 ;
     RECT  48.956 0.048 48.995 1.176 ;
     RECT  48.995 0.528 49.043 1.176 ;
     RECT  49.043 1.152 49.069 1.176 ;
     RECT  48.737 2.148 49.093 13.128 ;
     RECT  48.809 25.728 49.169 25.8 ;
     RECT  48.604 16.56 49.235 17.688 ;
     RECT  49.169 25.728 49.241 25.752 ;
     RECT  49.235 17.136 49.357 17.688 ;
     RECT  49.093 1.68 49.385 13.128 ;
     RECT  48.604 22.176 49.529 22.2 ;
     RECT  49.357 17.664 49.571 17.688 ;
     RECT  48.604 23.904 49.621 23.928 ;
     RECT  50.129 0.576 50.213 0.6 ;
     RECT  49.621 23.904 50.501 24.504 ;
     RECT  50.501 23.904 50.533 23.928 ;
     RECT  50.533 23.856 50.749 23.928 ;
     RECT  49.385 1.728 50.753 13.128 ;
     RECT  50.773 0.24 50.821 0.312 ;
     RECT  50.749 23.376 50.821 23.928 ;
     RECT  49.957 19.92 50.869 19.944 ;
     RECT  50.821 0.096 50.963 0.312 ;
     RECT  50.753 2.016 50.963 13.128 ;
     RECT  50.725 25.056 50.969 25.08 ;
     RECT  50.963 2.148 51.008 13.128 ;
     RECT  50.821 14.4 51.008 14.424 ;
     RECT  50.629 15.984 51.008 16.008 ;
     RECT  50.869 19.104 51.008 19.944 ;
     RECT  50.821 22.8 51.008 23.928 ;
     RECT  51.008 2.148 51.112 23.928 ;
     RECT  51.112 2.304 51.155 23.928 ;
     RECT  51.155 2.304 51.257 23.592 ;
     RECT  51.257 2.304 51.304 23.502 ;
     RECT  51.253 25.728 51.797 25.8 ;
     RECT  50.963 0.144 51.893 0.312 ;
     RECT  51.304 2.304 51.923 14.232 ;
     RECT  51.797 25.728 51.977 25.752 ;
     RECT  51.893 0.144 52.076 0.552 ;
     RECT  51.304 15.984 52.093 17.064 ;
     RECT  51.304 23.328 52.229 23.352 ;
     RECT  52.093 16.56 52.405 17.064 ;
     RECT  51.923 14.16 52.453 14.232 ;
     RECT  51.923 2.304 52.549 13.128 ;
     RECT  52.453 14.16 52.549 14.424 ;
     RECT  52.549 1.728 52.697 13.128 ;
     RECT  52.549 14.16 52.789 14.952 ;
     RECT  53.009 22.8 53.305 22.824 ;
     RECT  52.721 23.904 53.305 23.928 ;
     RECT  53.305 22.8 53.317 23.928 ;
     RECT  53.125 25.056 53.317 25.08 ;
     RECT  52.076 0.048 53.459 0.552 ;
     RECT  52.405 16.56 53.461 17.64 ;
     RECT  53.459 0.144 53.507 0.552 ;
     RECT  53.317 22.8 53.525 25.08 ;
     RECT  53.525 25.056 53.561 25.08 ;
     RECT  53.507 0.192 53.633 0.552 ;
     RECT  52.697 1.728 53.708 12.552 ;
     RECT  52.789 14.16 53.708 15.24 ;
     RECT  53.461 16.56 53.708 17.688 ;
     RECT  53.525 22.8 53.708 23.928 ;
     RECT  53.708 1.728 54.004 23.928 ;
     RECT  54.004 16.8 54.065 18.264 ;
     RECT  53.701 25.728 54.101 25.8 ;
     RECT  53.633 0.192 54.131 0.312 ;
     RECT  54.065 16.8 54.131 16.92 ;
     RECT  54.065 18.24 54.131 18.264 ;
     RECT  54.101 25.728 54.173 25.752 ;
     RECT  54.131 16.896 54.227 16.92 ;
     RECT  54.004 23.328 55.109 23.928 ;
     RECT  54.709 0.096 55.139 0.12 ;
     RECT  55.109 23.376 55.253 23.928 ;
     RECT  54.004 1.728 55.397 15.24 ;
     RECT  55.381 25.056 55.532 25.08 ;
     RECT  55.532 24.528 55.619 25.08 ;
     RECT  55.619 25.056 55.897 25.08 ;
     RECT  55.397 2.16 55.969 15.24 ;
     RECT  55.141 16.56 55.969 16.584 ;
     RECT  55.897 25.056 56.101 25.128 ;
     RECT  55.969 2.16 56.245 16.584 ;
     RECT  55.189 17.616 56.245 17.64 ;
     RECT  56.101 25.056 56.339 25.8 ;
     RECT  56.245 2.16 56.408 17.64 ;
     RECT  55.253 23.376 56.408 23.4 ;
     RECT  56.408 2.148 56.485 23.772 ;
     RECT  56.005 0.528 56.581 0.552 ;
     RECT  56.485 2.016 56.704 23.772 ;
     RECT  56.581 0.048 56.819 0.552 ;
     RECT  56.819 0.144 56.867 0.552 ;
     RECT  56.339 25.776 57.017 25.8 ;
     RECT  56.704 2.016 57.133 14.856 ;
     RECT  57.133 14.112 57.347 14.856 ;
     RECT  57.133 2.016 57.413 13.128 ;
     RECT  57.413 2.016 57.481 12.024 ;
     RECT  57.347 14.112 57.485 14.664 ;
     RECT  57.061 23.808 57.557 24.504 ;
     RECT  57.481 1.728 57.635 12.024 ;
     RECT  57.635 1.728 57.665 11.928 ;
     RECT  57.413 13.104 57.701 13.128 ;
     RECT  57.485 14.112 57.701 14.184 ;
     RECT  56.867 0.528 57.737 0.552 ;
     RECT  57.665 9.216 57.737 11.928 ;
     RECT  57.737 11.568 57.809 11.928 ;
     RECT  57.701 14.112 57.809 14.136 ;
     RECT  57.665 1.728 57.827 7.56 ;
     RECT  57.827 1.728 57.845 4.344 ;
     RECT  57.557 23.904 57.845 24.504 ;
     RECT  57.845 2.832 57.971 4.296 ;
     RECT  57.827 5.712 57.971 7.56 ;
     RECT  57.737 9.216 57.989 10.248 ;
     RECT  57.971 5.712 58.019 7.368 ;
     RECT  58.019 6.336 58.061 7.368 ;
     RECT  58.061 6.336 58.097 6.888 ;
     RECT  58.097 6.864 58.115 6.888 ;
     RECT  57.781 19.68 58.133 19.704 ;
     RECT  57.971 2.832 58.141 2.856 ;
     RECT  57.971 4.272 58.169 4.296 ;
     RECT  57.989 9.216 58.169 9.24 ;
     RECT  57.989 10.224 58.169 10.248 ;
     RECT  57.845 23.904 58.169 23.928 ;
     RECT  58.157 25.776 58.241 25.8 ;
     RECT  57.845 1.728 58.277 1.752 ;
     RECT  57.809 11.904 58.349 11.928 ;
    LAYER M5 ;
     RECT  2.208 0.016 58.2 1.763 ;
     RECT  2.304 1.763 58.008 1.811 ;
     RECT  4.224 1.811 58.008 2.821 ;
     RECT  2.304 1.811 2.952 3.397 ;
     RECT  4.224 2.821 58.104 3.443 ;
     RECT  4.992 3.443 58.104 3.491 ;
     RECT  2.304 3.397 3.048 4.595 ;
     RECT  4.992 3.491 43.368 4.595 ;
     RECT  6.768 4.595 43.368 5.173 ;
     RECT  6.768 5.173 43.464 5.269 ;
     RECT  4.992 4.595 5.412 5.603 ;
     RECT  6.768 5.269 43.56 5.747 ;
     RECT  6.768 5.747 43.464 6.323 ;
     RECT  44.832 3.491 58.104 6.899 ;
     RECT  2.4 4.595 3.048 7.139 ;
     RECT  44.832 6.899 57.96 7.571 ;
     RECT  5.1 5.603 5.412 7.909 ;
     RECT  2.4 7.139 2.712 8.485 ;
     RECT  7.152 6.323 43.464 8.821 ;
     RECT  5.1 7.909 5.784 9.109 ;
     RECT  6.864 8.821 43.464 9.109 ;
     RECT  2.4 8.485 3.432 9.731 ;
     RECT  5.1 9.109 43.464 9.731 ;
     RECT  44.832 7.571 57.768 9.731 ;
     RECT  46.944 9.731 57.768 10.067 ;
     RECT  5.1 9.731 38.856 10.355 ;
     RECT  44.832 9.731 45.912 10.883 ;
     RECT  44.88 10.883 45.912 11.029 ;
     RECT  46.944 10.067 57.624 11.029 ;
     RECT  2.4 9.731 2.904 11.459 ;
     RECT  6.816 10.355 38.856 11.459 ;
     RECT  44.88 11.029 57.624 11.459 ;
     RECT  39.84 9.731 43.464 11.891 ;
     RECT  7.152 11.459 8.112 12.035 ;
     RECT  44.976 11.459 57.624 12.035 ;
     RECT  45.6 12.035 57.384 12.467 ;
     RECT  9.12 11.459 38.856 12.611 ;
     RECT  9.12 12.611 37.812 12.707 ;
     RECT  45.6 12.467 57.336 12.755 ;
     RECT  41.616 11.891 43.464 12.803 ;
     RECT  42.768 12.803 43.464 12.995 ;
     RECT  42.768 12.995 43.212 13.091 ;
     RECT  48.3 12.755 57.336 13.139 ;
     RECT  9.504 12.707 37.812 13.187 ;
     RECT  9.552 13.187 37.812 13.715 ;
     RECT  36.384 13.715 37.812 13.811 ;
     RECT  9.552 13.715 35.352 14.291 ;
     RECT  34.272 14.291 35.352 14.819 ;
     RECT  50.64 13.139 57.336 14.867 ;
     RECT  9.552 14.291 13.752 15.443 ;
     RECT  7.8 12.035 8.112 15.781 ;
     RECT  12.576 15.443 13.752 16.019 ;
     RECT  14.976 14.291 33.24 16.019 ;
     RECT  50.64 14.867 56.712 16.019 ;
     RECT  7.68 15.781 8.112 16.069 ;
     RECT  14.976 16.019 30.696 16.307 ;
     RECT  2.4 11.459 2.712 16.501 ;
     RECT  14.976 16.307 25.56 16.595 ;
     RECT  26.592 16.307 30.696 16.595 ;
     RECT  34.272 14.819 35.256 16.595 ;
     RECT  36.576 13.811 37.812 16.595 ;
     RECT  38.832 12.611 38.856 16.595 ;
     RECT  51 16.019 55.224 16.595 ;
     RECT  56.208 16.019 56.712 16.595 ;
     RECT  31.92 16.019 33.24 16.835 ;
     RECT  5.1 10.355 5.784 16.931 ;
     RECT  15.312 16.595 16.488 16.931 ;
     RECT  51 16.595 54.216 16.931 ;
     RECT  15.312 16.931 16.212 17.075 ;
     RECT  12.816 16.019 13.752 17.123 ;
     RECT  15.744 17.075 16.212 17.123 ;
     RECT  17.568 16.595 25.56 17.123 ;
     RECT  41.616 12.803 41.64 17.123 ;
     RECT  45.6 12.755 47.112 17.123 ;
     RECT  56.256 16.595 56.712 17.123 ;
     RECT  22.704 17.123 25.56 17.171 ;
     RECT  34.416 16.595 35.256 17.219 ;
     RECT  5.1 16.931 5.736 17.411 ;
     RECT  2.208 16.501 2.712 17.509 ;
     RECT  5.1 17.411 5.412 17.605 ;
     RECT  55.2 16.595 55.224 17.651 ;
     RECT  13.2 17.123 13.752 17.699 ;
     RECT  18.192 17.123 21.612 17.699 ;
     RECT  23.088 17.171 24.312 17.699 ;
     RECT  26.7 16.595 30.696 17.699 ;
     RECT  34.704 17.219 35.256 17.699 ;
     RECT  39.84 11.891 40.512 17.699 ;
     RECT  45.6 17.123 46.968 17.699 ;
     RECT  48.3 13.139 49.56 17.699 ;
     RECT  20.64 17.699 21.612 17.795 ;
     RECT  7.68 16.069 8.328 17.989 ;
     RECT  29.4 17.699 30.696 18.037 ;
     RECT  7.2 17.989 8.328 18.133 ;
     RECT  32.1 16.835 33.24 18.181 ;
     RECT  18.192 17.699 18.912 18.275 ;
     RECT  23.76 17.699 24.312 18.275 ;
     RECT  26.7 17.699 28.296 18.275 ;
     RECT  29.4 18.037 30.744 18.275 ;
     RECT  51 16.931 54.12 18.275 ;
     RECT  9.552 15.443 11.304 18.851 ;
     RECT  32.1 18.181 33.576 18.851 ;
     RECT  51 18.275 54.012 19.093 ;
     RECT  7.008 18.133 8.328 19.621 ;
     RECT  4.992 17.605 5.412 19.669 ;
     RECT  7.008 19.621 8.376 19.669 ;
     RECT  33.552 18.851 33.576 19.669 ;
     RECT  34.704 17.699 35.112 19.669 ;
     RECT  36.96 16.595 37.812 19.669 ;
     RECT  40.2 17.699 40.512 19.669 ;
     RECT  42.9 13.091 43.212 19.669 ;
     RECT  48.3 17.699 48.612 19.669 ;
     RECT  30.72 18.275 30.744 19.909 ;
     RECT  32.1 18.851 32.412 19.909 ;
     RECT  36.432 19.669 37.812 19.909 ;
     RECT  40.2 19.669 41.256 19.909 ;
     RECT  42.9 19.669 43.32 19.909 ;
     RECT  45.6 17.699 46.68 19.909 ;
     RECT  50.88 19.093 54.012 19.909 ;
     RECT  4.992 19.669 8.376 20.053 ;
     RECT  9.552 18.851 10.812 21.109 ;
     RECT  15.9 17.123 16.212 21.109 ;
     RECT  9.552 21.109 11.352 21.637 ;
     RECT  13.2 17.699 13.512 21.637 ;
     RECT  18.6 18.275 18.912 21.637 ;
     RECT  21.168 17.795 21.612 21.637 ;
     RECT  24 18.275 24.312 21.637 ;
     RECT  26.7 18.275 27.864 21.637 ;
     RECT  29.4 18.275 29.712 21.637 ;
     RECT  30.72 19.909 32.412 21.637 ;
     RECT  9.552 21.637 11.688 22.021 ;
     RECT  18.432 21.637 19.128 22.117 ;
     RECT  15.792 21.109 16.212 22.165 ;
     RECT  47.76 19.669 48.612 22.165 ;
     RECT  49.968 19.909 54.012 22.165 ;
     RECT  15.792 22.165 16.344 22.213 ;
     RECT  23.568 21.637 24.312 22.213 ;
     RECT  25.824 21.637 27.864 22.213 ;
     RECT  29.4 21.637 32.412 22.213 ;
     RECT  44.976 19.909 46.68 22.213 ;
     RECT  47.76 22.165 54.012 22.213 ;
     RECT  9.456 22.021 11.688 22.693 ;
     RECT  13.2 21.637 13.752 22.693 ;
     RECT  2.208 17.509 2.808 22.741 ;
     RECT  36.432 19.909 38.664 22.741 ;
     RECT  40.2 19.909 41.448 22.741 ;
     RECT  42.528 19.909 43.704 22.741 ;
     RECT  44.976 22.213 54.012 22.741 ;
     RECT  9.456 22.693 12.072 22.789 ;
     RECT  13.2 22.693 13.944 22.789 ;
     RECT  15.792 22.213 16.728 22.789 ;
     RECT  20.976 21.637 21.612 22.789 ;
     RECT  33.552 19.669 35.112 22.789 ;
     RECT  36.432 22.741 54.012 22.789 ;
     RECT  9.456 22.789 14.472 22.837 ;
     RECT  2.208 22.741 2.952 23.317 ;
     RECT  20.976 22.789 21.912 23.317 ;
     RECT  23.568 22.213 24.408 23.317 ;
     RECT  33.552 22.789 54.012 23.317 ;
     RECT  2.208 23.317 3.144 23.365 ;
     RECT  4.416 20.053 8.376 23.365 ;
     RECT  9.456 22.837 14.664 23.365 ;
     RECT  15.792 22.789 17.304 23.365 ;
     RECT  33.552 23.317 54.84 23.365 ;
     RECT  56.4 17.123 56.712 23.365 ;
     RECT  25.824 22.213 32.412 23.769 ;
     RECT  9.456 23.365 17.304 23.783 ;
     RECT  25.824 23.769 32.22 23.783 ;
     RECT  33.552 23.365 56.712 23.783 ;
     RECT  57.792 19.669 57.816 23.797 ;
     RECT  2.208 23.365 8.376 23.845 ;
     RECT  9.456 23.783 12.456 23.845 ;
     RECT  57.072 23.797 57.816 23.893 ;
     RECT  33.552 23.783 55.752 25.045 ;
     RECT  2.208 23.845 12.456 25.093 ;
     RECT  13.536 23.783 17.304 25.093 ;
     RECT  18.432 22.117 19.704 25.093 ;
     RECT  20.976 23.317 22.104 25.093 ;
     RECT  23.568 23.317 24.552 25.093 ;
     RECT  25.824 23.783 31.8 25.093 ;
     RECT  33.552 25.045 55.944 25.093 ;
     RECT  57.072 23.893 58.008 25.093 ;
     RECT  2.208 25.093 58.008 25.765 ;
     RECT  2.208 25.765 58.2 25.872 ;
  END
END dsfd_qbank_S
END LIBRARY
